VERSION 5.8 ;
BUSBITCHARS "[]" ;
DIVIDERCHAR "/" ;
UNITS
    DATABASE MICRONS 1000 ;
END UNITS

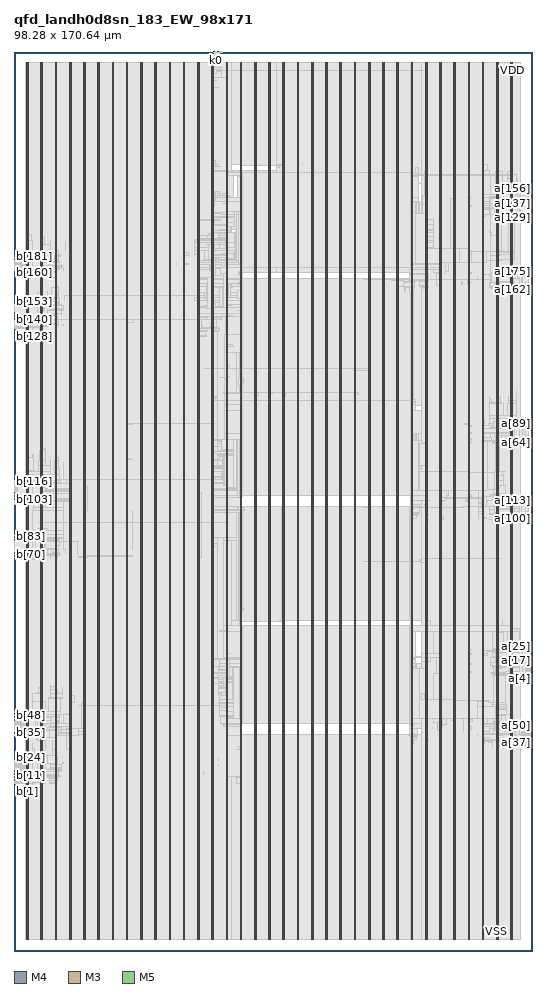
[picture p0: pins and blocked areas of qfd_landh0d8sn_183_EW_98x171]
MACRO qfd_landh0d8sn_183_EW_98x171
  FOREIGN qfd_landh0d8sn_183_EW_98x171 0 0 ;
  CLASS BLOCK ;
  SIZE 98.28 BY 170.64 ;
  PIN a[0]
    DIRECTION INPUT ;
    USE SIGNAL ;
    PORT
      LAYER M4 ;
        RECT  98.196 52.56 98.28 52.584 ;
    END
  END a[0]
  PIN a[100]
    DIRECTION INPUT ;
    USE SIGNAL ;
    PORT
      LAYER M4 ;
        RECT  98.196 81.936 98.28 81.96 ;
    END
  END a[100]
  PIN a[101]
    DIRECTION INPUT ;
    USE SIGNAL ;
    PORT
      LAYER M4 ;
        RECT  98.196 82.08 98.28 82.104 ;
    END
  END a[101]
  PIN a[102]
    DIRECTION INPUT ;
    USE SIGNAL ;
    PORT
      LAYER M4 ;
        RECT  98.196 82.224 98.28 82.248 ;
    END
  END a[102]
  PIN a[103]
    DIRECTION INPUT ;
    USE SIGNAL ;
    PORT
      LAYER M4 ;
        RECT  98.196 82.368 98.28 82.392 ;
    END
  END a[103]
  PIN a[104]
    DIRECTION INPUT ;
    USE SIGNAL ;
    PORT
      LAYER M4 ;
        RECT  98.196 82.512 98.28 82.536 ;
    END
  END a[104]
  PIN a[105]
    DIRECTION INPUT ;
    USE SIGNAL ;
    PORT
      LAYER M4 ;
        RECT  98.196 82.656 98.28 82.68 ;
    END
  END a[105]
  PIN a[106]
    DIRECTION INPUT ;
    USE SIGNAL ;
    PORT
      LAYER M4 ;
        RECT  98.196 82.8 98.28 82.824 ;
    END
  END a[106]
  PIN a[107]
    DIRECTION INPUT ;
    USE SIGNAL ;
    PORT
      LAYER M4 ;
        RECT  98.196 82.944 98.28 82.968 ;
    END
  END a[107]
  PIN a[108]
    DIRECTION INPUT ;
    USE SIGNAL ;
    PORT
      LAYER M4 ;
        RECT  98.196 83.088 98.28 83.112 ;
    END
  END a[108]
  PIN a[109]
    DIRECTION INPUT ;
    USE SIGNAL ;
    PORT
      LAYER M4 ;
        RECT  98.196 83.232 98.28 83.256 ;
    END
  END a[109]
  PIN a[10]
    DIRECTION INPUT ;
    USE SIGNAL ;
    PORT
      LAYER M4 ;
        RECT  98.196 54 98.28 54.024 ;
    END
  END a[10]
  PIN a[110]
    DIRECTION INPUT ;
    USE SIGNAL ;
    PORT
      LAYER M4 ;
        RECT  98.196 83.376 98.28 83.4 ;
    END
  END a[110]
  PIN a[111]
    DIRECTION INPUT ;
    USE SIGNAL ;
    PORT
      LAYER M4 ;
        RECT  98.196 83.52 98.28 83.544 ;
    END
  END a[111]
  PIN a[112]
    DIRECTION INPUT ;
    USE SIGNAL ;
    PORT
      LAYER M4 ;
        RECT  98.196 83.664 98.28 83.688 ;
    END
  END a[112]
  PIN a[113]
    DIRECTION INPUT ;
    USE SIGNAL ;
    PORT
      LAYER M4 ;
        RECT  98.196 83.808 98.28 83.832 ;
    END
  END a[113]
  PIN a[114]
    DIRECTION INPUT ;
    USE SIGNAL ;
    PORT
      LAYER M4 ;
        RECT  98.196 83.952 98.28 83.976 ;
    END
  END a[114]
  PIN a[115]
    DIRECTION INPUT ;
    USE SIGNAL ;
    PORT
      LAYER M4 ;
        RECT  98.196 84.096 98.28 84.12 ;
    END
  END a[115]
  PIN a[116]
    DIRECTION INPUT ;
    USE SIGNAL ;
    PORT
      LAYER M4 ;
        RECT  98.196 84.24 98.28 84.264 ;
    END
  END a[116]
  PIN a[117]
    DIRECTION INPUT ;
    USE SIGNAL ;
    PORT
      LAYER M4 ;
        RECT  98.196 84.384 98.28 84.408 ;
    END
  END a[117]
  PIN a[118]
    DIRECTION INPUT ;
    USE SIGNAL ;
    PORT
      LAYER M4 ;
        RECT  98.196 84.528 98.28 84.552 ;
    END
  END a[118]
  PIN a[119]
    DIRECTION INPUT ;
    USE SIGNAL ;
    PORT
      LAYER M4 ;
        RECT  98.196 84.672 98.28 84.696 ;
    END
  END a[119]
  PIN a[11]
    DIRECTION INPUT ;
    USE SIGNAL ;
    PORT
      LAYER M4 ;
        RECT  98.196 54.144 98.28 54.168 ;
    END
  END a[11]
  PIN a[120]
    DIRECTION INPUT ;
    USE SIGNAL ;
    PORT
      LAYER M4 ;
        RECT  98.196 84.816 98.28 84.84 ;
    END
  END a[120]
  PIN a[121]
    DIRECTION INPUT ;
    USE SIGNAL ;
    PORT
      LAYER M4 ;
        RECT  98.196 84.96 98.28 84.984 ;
    END
  END a[121]
  PIN a[122]
    DIRECTION INPUT ;
    USE SIGNAL ;
    PORT
      LAYER M4 ;
        RECT  98.196 85.104 98.28 85.128 ;
    END
  END a[122]
  PIN a[123]
    DIRECTION INPUT ;
    USE SIGNAL ;
    PORT
      LAYER M4 ;
        RECT  98.196 85.248 98.28 85.272 ;
    END
  END a[123]
  PIN a[124]
    DIRECTION INPUT ;
    USE SIGNAL ;
    PORT
      LAYER M4 ;
        RECT  98.196 85.392 98.28 85.416 ;
    END
  END a[124]
  PIN a[125]
    DIRECTION INPUT ;
    USE SIGNAL ;
    PORT
      LAYER M4 ;
        RECT  98.196 85.536 98.28 85.56 ;
    END
  END a[125]
  PIN a[126]
    DIRECTION INPUT ;
    USE SIGNAL ;
    PORT
      LAYER M4 ;
        RECT  98.196 85.68 98.28 85.704 ;
    END
  END a[126]
  PIN a[127]
    DIRECTION INPUT ;
    USE SIGNAL ;
    PORT
      LAYER M4 ;
        RECT  98.196 85.824 98.28 85.848 ;
    END
  END a[127]
  PIN a[128]
    DIRECTION INPUT ;
    USE SIGNAL ;
    PORT
      LAYER M4 ;
        RECT  98.196 138.96 98.28 138.984 ;
    END
  END a[128]
  PIN a[129]
    DIRECTION INPUT ;
    USE SIGNAL ;
    PORT
      LAYER M4 ;
        RECT  98.196 139.104 98.28 139.128 ;
    END
  END a[129]
  PIN a[12]
    DIRECTION INPUT ;
    USE SIGNAL ;
    PORT
      LAYER M4 ;
        RECT  98.196 54.288 98.28 54.312 ;
    END
  END a[12]
  PIN a[130]
    DIRECTION INPUT ;
    USE SIGNAL ;
    PORT
      LAYER M4 ;
        RECT  98.196 139.248 98.28 139.272 ;
    END
  END a[130]
  PIN a[131]
    DIRECTION INPUT ;
    USE SIGNAL ;
    PORT
      LAYER M4 ;
        RECT  98.196 139.392 98.28 139.416 ;
    END
  END a[131]
  PIN a[132]
    DIRECTION INPUT ;
    USE SIGNAL ;
    PORT
      LAYER M4 ;
        RECT  98.196 139.536 98.28 139.56 ;
    END
  END a[132]
  PIN a[133]
    DIRECTION INPUT ;
    USE SIGNAL ;
    PORT
      LAYER M4 ;
        RECT  98.196 139.68 98.28 139.704 ;
    END
  END a[133]
  PIN a[134]
    DIRECTION INPUT ;
    USE SIGNAL ;
    PORT
      LAYER M4 ;
        RECT  98.196 139.824 98.28 139.848 ;
    END
  END a[134]
  PIN a[135]
    DIRECTION INPUT ;
    USE SIGNAL ;
    PORT
      LAYER M4 ;
        RECT  98.196 139.968 98.28 139.992 ;
    END
  END a[135]
  PIN a[136]
    DIRECTION INPUT ;
    USE SIGNAL ;
    PORT
      LAYER M4 ;
        RECT  98.196 140.112 98.28 140.136 ;
    END
  END a[136]
  PIN a[137]
    DIRECTION INPUT ;
    USE SIGNAL ;
    PORT
      LAYER M4 ;
        RECT  98.196 140.256 98.28 140.28 ;
    END
  END a[137]
  PIN a[138]
    DIRECTION INPUT ;
    USE SIGNAL ;
    PORT
      LAYER M4 ;
        RECT  98.196 140.4 98.28 140.424 ;
    END
  END a[138]
  PIN a[139]
    DIRECTION INPUT ;
    USE SIGNAL ;
    PORT
      LAYER M4 ;
        RECT  98.196 140.544 98.28 140.568 ;
    END
  END a[139]
  PIN a[13]
    DIRECTION INPUT ;
    USE SIGNAL ;
    PORT
      LAYER M4 ;
        RECT  98.196 54.432 98.28 54.456 ;
    END
  END a[13]
  PIN a[140]
    DIRECTION INPUT ;
    USE SIGNAL ;
    PORT
      LAYER M4 ;
        RECT  98.196 140.688 98.28 140.712 ;
    END
  END a[140]
  PIN a[141]
    DIRECTION INPUT ;
    USE SIGNAL ;
    PORT
      LAYER M4 ;
        RECT  98.196 140.832 98.28 140.856 ;
    END
  END a[141]
  PIN a[142]
    DIRECTION INPUT ;
    USE SIGNAL ;
    PORT
      LAYER M4 ;
        RECT  98.196 140.976 98.28 141 ;
    END
  END a[142]
  PIN a[143]
    DIRECTION INPUT ;
    USE SIGNAL ;
    PORT
      LAYER M4 ;
        RECT  98.196 141.12 98.28 141.144 ;
    END
  END a[143]
  PIN a[144]
    DIRECTION INPUT ;
    USE SIGNAL ;
    PORT
      LAYER M4 ;
        RECT  98.196 141.264 98.28 141.288 ;
    END
  END a[144]
  PIN a[145]
    DIRECTION INPUT ;
    USE SIGNAL ;
    PORT
      LAYER M4 ;
        RECT  98.196 141.408 98.28 141.432 ;
    END
  END a[145]
  PIN a[146]
    DIRECTION INPUT ;
    USE SIGNAL ;
    PORT
      LAYER M4 ;
        RECT  98.196 141.552 98.28 141.576 ;
    END
  END a[146]
  PIN a[147]
    DIRECTION INPUT ;
    USE SIGNAL ;
    PORT
      LAYER M4 ;
        RECT  98.196 141.696 98.28 141.72 ;
    END
  END a[147]
  PIN a[148]
    DIRECTION INPUT ;
    USE SIGNAL ;
    PORT
      LAYER M4 ;
        RECT  98.196 141.84 98.28 141.864 ;
    END
  END a[148]
  PIN a[149]
    DIRECTION INPUT ;
    USE SIGNAL ;
    PORT
      LAYER M4 ;
        RECT  98.196 141.984 98.28 142.008 ;
    END
  END a[149]
  PIN a[14]
    DIRECTION INPUT ;
    USE SIGNAL ;
    PORT
      LAYER M4 ;
        RECT  98.196 54.576 98.28 54.6 ;
    END
  END a[14]
  PIN a[150]
    DIRECTION INPUT ;
    USE SIGNAL ;
    PORT
      LAYER M4 ;
        RECT  98.196 142.128 98.28 142.152 ;
    END
  END a[150]
  PIN a[151]
    DIRECTION INPUT ;
    USE SIGNAL ;
    PORT
      LAYER M4 ;
        RECT  98.196 142.272 98.28 142.296 ;
    END
  END a[151]
  PIN a[152]
    DIRECTION INPUT ;
    USE SIGNAL ;
    PORT
      LAYER M4 ;
        RECT  98.196 142.416 98.28 142.44 ;
    END
  END a[152]
  PIN a[153]
    DIRECTION INPUT ;
    USE SIGNAL ;
    PORT
      LAYER M4 ;
        RECT  98.196 142.56 98.28 142.584 ;
    END
  END a[153]
  PIN a[154]
    DIRECTION INPUT ;
    USE SIGNAL ;
    PORT
      LAYER M4 ;
        RECT  98.196 142.704 98.28 142.728 ;
    END
  END a[154]
  PIN a[155]
    DIRECTION INPUT ;
    USE SIGNAL ;
    PORT
      LAYER M4 ;
        RECT  98.196 142.848 98.28 142.872 ;
    END
  END a[155]
  PIN a[156]
    DIRECTION INPUT ;
    USE SIGNAL ;
    PORT
      LAYER M4 ;
        RECT  98.196 142.992 98.28 143.016 ;
    END
  END a[156]
  PIN a[157]
    DIRECTION INPUT ;
    USE SIGNAL ;
    PORT
      LAYER M4 ;
        RECT  98.196 143.136 98.28 143.16 ;
    END
  END a[157]
  PIN a[158]
    DIRECTION INPUT ;
    USE SIGNAL ;
    PORT
      LAYER M4 ;
        RECT  98.196 143.28 98.28 143.304 ;
    END
  END a[158]
  PIN a[159]
    DIRECTION INPUT ;
    USE SIGNAL ;
    PORT
      LAYER M4 ;
        RECT  98.196 143.424 98.28 143.448 ;
    END
  END a[159]
  PIN a[15]
    DIRECTION INPUT ;
    USE SIGNAL ;
    PORT
      LAYER M4 ;
        RECT  98.196 54.72 98.28 54.744 ;
    END
  END a[15]
  PIN a[160]
    DIRECTION INPUT ;
    USE SIGNAL ;
    PORT
      LAYER M4 ;
        RECT  98.196 125.136 98.28 125.16 ;
    END
  END a[160]
  PIN a[161]
    DIRECTION INPUT ;
    USE SIGNAL ;
    PORT
      LAYER M4 ;
        RECT  98.196 125.28 98.28 125.304 ;
    END
  END a[161]
  PIN a[162]
    DIRECTION INPUT ;
    USE SIGNAL ;
    PORT
      LAYER M4 ;
        RECT  98.196 125.424 98.28 125.448 ;
    END
  END a[162]
  PIN a[163]
    DIRECTION INPUT ;
    USE SIGNAL ;
    PORT
      LAYER M4 ;
        RECT  98.196 125.568 98.28 125.592 ;
    END
  END a[163]
  PIN a[164]
    DIRECTION INPUT ;
    USE SIGNAL ;
    PORT
      LAYER M4 ;
        RECT  98.196 125.712 98.28 125.736 ;
    END
  END a[164]
  PIN a[165]
    DIRECTION INPUT ;
    USE SIGNAL ;
    PORT
      LAYER M4 ;
        RECT  98.196 125.856 98.28 125.88 ;
    END
  END a[165]
  PIN a[166]
    DIRECTION INPUT ;
    USE SIGNAL ;
    PORT
      LAYER M4 ;
        RECT  98.196 126 98.28 126.024 ;
    END
  END a[166]
  PIN a[167]
    DIRECTION INPUT ;
    USE SIGNAL ;
    PORT
      LAYER M4 ;
        RECT  98.196 126.144 98.28 126.168 ;
    END
  END a[167]
  PIN a[168]
    DIRECTION INPUT ;
    USE SIGNAL ;
    PORT
      LAYER M4 ;
        RECT  98.196 126.288 98.28 126.312 ;
    END
  END a[168]
  PIN a[169]
    DIRECTION INPUT ;
    USE SIGNAL ;
    PORT
      LAYER M4 ;
        RECT  98.196 126.432 98.28 126.456 ;
    END
  END a[169]
  PIN a[16]
    DIRECTION INPUT ;
    USE SIGNAL ;
    PORT
      LAYER M4 ;
        RECT  98.196 54.864 98.28 54.888 ;
    END
  END a[16]
  PIN a[170]
    DIRECTION INPUT ;
    USE SIGNAL ;
    PORT
      LAYER M4 ;
        RECT  98.196 126.576 98.28 126.6 ;
    END
  END a[170]
  PIN a[171]
    DIRECTION INPUT ;
    USE SIGNAL ;
    PORT
      LAYER M4 ;
        RECT  98.196 126.72 98.28 126.744 ;
    END
  END a[171]
  PIN a[172]
    DIRECTION INPUT ;
    USE SIGNAL ;
    PORT
      LAYER M4 ;
        RECT  98.196 126.864 98.28 126.888 ;
    END
  END a[172]
  PIN a[173]
    DIRECTION INPUT ;
    USE SIGNAL ;
    PORT
      LAYER M4 ;
        RECT  98.196 127.008 98.28 127.032 ;
    END
  END a[173]
  PIN a[174]
    DIRECTION INPUT ;
    USE SIGNAL ;
    PORT
      LAYER M4 ;
        RECT  98.196 127.152 98.28 127.176 ;
    END
  END a[174]
  PIN a[175]
    DIRECTION INPUT ;
    USE SIGNAL ;
    PORT
      LAYER M4 ;
        RECT  98.196 127.296 98.28 127.32 ;
    END
  END a[175]
  PIN a[176]
    DIRECTION INPUT ;
    USE SIGNAL ;
    PORT
      LAYER M4 ;
        RECT  98.196 127.44 98.28 127.464 ;
    END
  END a[176]
  PIN a[177]
    DIRECTION INPUT ;
    USE SIGNAL ;
    PORT
      LAYER M4 ;
        RECT  98.196 127.584 98.28 127.608 ;
    END
  END a[177]
  PIN a[178]
    DIRECTION INPUT ;
    USE SIGNAL ;
    PORT
      LAYER M4 ;
        RECT  98.196 127.728 98.28 127.752 ;
    END
  END a[178]
  PIN a[179]
    DIRECTION INPUT ;
    USE SIGNAL ;
    PORT
      LAYER M4 ;
        RECT  98.196 127.872 98.28 127.896 ;
    END
  END a[179]
  PIN a[17]
    DIRECTION INPUT ;
    USE SIGNAL ;
    PORT
      LAYER M4 ;
        RECT  98.196 55.008 98.28 55.032 ;
    END
  END a[17]
  PIN a[180]
    DIRECTION INPUT ;
    USE SIGNAL ;
    PORT
      LAYER M4 ;
        RECT  98.196 128.016 98.28 128.04 ;
    END
  END a[180]
  PIN a[181]
    DIRECTION INPUT ;
    USE SIGNAL ;
    PORT
      LAYER M4 ;
        RECT  98.196 128.16 98.28 128.184 ;
    END
  END a[181]
  PIN a[182]
    DIRECTION INPUT ;
    USE SIGNAL ;
    PORT
      LAYER M4 ;
        RECT  98.196 128.304 98.28 128.328 ;
    END
  END a[182]
  PIN a[18]
    DIRECTION INPUT ;
    USE SIGNAL ;
    PORT
      LAYER M4 ;
        RECT  98.196 55.152 98.28 55.176 ;
    END
  END a[18]
  PIN a[19]
    DIRECTION INPUT ;
    USE SIGNAL ;
    PORT
      LAYER M4 ;
        RECT  98.196 55.296 98.28 55.32 ;
    END
  END a[19]
  PIN a[1]
    DIRECTION INPUT ;
    USE SIGNAL ;
    PORT
      LAYER M4 ;
        RECT  98.196 52.704 98.28 52.728 ;
    END
  END a[1]
  PIN a[20]
    DIRECTION INPUT ;
    USE SIGNAL ;
    PORT
      LAYER M4 ;
        RECT  98.196 55.44 98.28 55.464 ;
    END
  END a[20]
  PIN a[21]
    DIRECTION INPUT ;
    USE SIGNAL ;
    PORT
      LAYER M4 ;
        RECT  98.196 55.584 98.28 55.608 ;
    END
  END a[21]
  PIN a[22]
    DIRECTION INPUT ;
    USE SIGNAL ;
    PORT
      LAYER M4 ;
        RECT  98.196 55.728 98.28 55.752 ;
    END
  END a[22]
  PIN a[23]
    DIRECTION INPUT ;
    USE SIGNAL ;
    PORT
      LAYER M4 ;
        RECT  98.196 55.872 98.28 55.896 ;
    END
  END a[23]
  PIN a[24]
    DIRECTION INPUT ;
    USE SIGNAL ;
    PORT
      LAYER M4 ;
        RECT  98.196 56.016 98.28 56.04 ;
    END
  END a[24]
  PIN a[25]
    DIRECTION INPUT ;
    USE SIGNAL ;
    PORT
      LAYER M4 ;
        RECT  98.196 56.16 98.28 56.184 ;
    END
  END a[25]
  PIN a[26]
    DIRECTION INPUT ;
    USE SIGNAL ;
    PORT
      LAYER M4 ;
        RECT  98.196 56.304 98.28 56.328 ;
    END
  END a[26]
  PIN a[27]
    DIRECTION INPUT ;
    USE SIGNAL ;
    PORT
      LAYER M4 ;
        RECT  98.196 56.448 98.28 56.472 ;
    END
  END a[27]
  PIN a[28]
    DIRECTION INPUT ;
    USE SIGNAL ;
    PORT
      LAYER M4 ;
        RECT  98.196 56.592 98.28 56.616 ;
    END
  END a[28]
  PIN a[29]
    DIRECTION INPUT ;
    USE SIGNAL ;
    PORT
      LAYER M4 ;
        RECT  98.196 56.736 98.28 56.76 ;
    END
  END a[29]
  PIN a[2]
    DIRECTION INPUT ;
    USE SIGNAL ;
    PORT
      LAYER M4 ;
        RECT  98.196 52.848 98.28 52.872 ;
    END
  END a[2]
  PIN a[30]
    DIRECTION INPUT ;
    USE SIGNAL ;
    PORT
      LAYER M4 ;
        RECT  98.196 56.88 98.28 56.904 ;
    END
  END a[30]
  PIN a[31]
    DIRECTION INPUT ;
    USE SIGNAL ;
    PORT
      LAYER M4 ;
        RECT  98.196 57.024 98.28 57.048 ;
    END
  END a[31]
  PIN a[32]
    DIRECTION INPUT ;
    USE SIGNAL ;
    PORT
      LAYER M4 ;
        RECT  98.196 38.736 98.28 38.76 ;
    END
  END a[32]
  PIN a[33]
    DIRECTION INPUT ;
    USE SIGNAL ;
    PORT
      LAYER M4 ;
        RECT  98.196 38.88 98.28 38.904 ;
    END
  END a[33]
  PIN a[34]
    DIRECTION INPUT ;
    USE SIGNAL ;
    PORT
      LAYER M4 ;
        RECT  98.196 39.024 98.28 39.048 ;
    END
  END a[34]
  PIN a[35]
    DIRECTION INPUT ;
    USE SIGNAL ;
    PORT
      LAYER M4 ;
        RECT  98.196 39.168 98.28 39.192 ;
    END
  END a[35]
  PIN a[36]
    DIRECTION INPUT ;
    USE SIGNAL ;
    PORT
      LAYER M4 ;
        RECT  98.196 39.312 98.28 39.336 ;
    END
  END a[36]
  PIN a[37]
    DIRECTION INPUT ;
    USE SIGNAL ;
    PORT
      LAYER M4 ;
        RECT  98.196 39.456 98.28 39.48 ;
    END
  END a[37]
  PIN a[38]
    DIRECTION INPUT ;
    USE SIGNAL ;
    PORT
      LAYER M4 ;
        RECT  98.196 39.6 98.28 39.624 ;
    END
  END a[38]
  PIN a[39]
    DIRECTION INPUT ;
    USE SIGNAL ;
    PORT
      LAYER M4 ;
        RECT  98.196 39.744 98.28 39.768 ;
    END
  END a[39]
  PIN a[3]
    DIRECTION INPUT ;
    USE SIGNAL ;
    PORT
      LAYER M4 ;
        RECT  98.196 52.992 98.28 53.016 ;
    END
  END a[3]
  PIN a[40]
    DIRECTION INPUT ;
    USE SIGNAL ;
    PORT
      LAYER M4 ;
        RECT  98.196 39.888 98.28 39.912 ;
    END
  END a[40]
  PIN a[41]
    DIRECTION INPUT ;
    USE SIGNAL ;
    PORT
      LAYER M4 ;
        RECT  98.196 40.032 98.28 40.056 ;
    END
  END a[41]
  PIN a[42]
    DIRECTION INPUT ;
    USE SIGNAL ;
    PORT
      LAYER M4 ;
        RECT  98.196 40.176 98.28 40.2 ;
    END
  END a[42]
  PIN a[43]
    DIRECTION INPUT ;
    USE SIGNAL ;
    PORT
      LAYER M4 ;
        RECT  98.196 40.32 98.28 40.344 ;
    END
  END a[43]
  PIN a[44]
    DIRECTION INPUT ;
    USE SIGNAL ;
    PORT
      LAYER M4 ;
        RECT  98.196 40.464 98.28 40.488 ;
    END
  END a[44]
  PIN a[45]
    DIRECTION INPUT ;
    USE SIGNAL ;
    PORT
      LAYER M4 ;
        RECT  98.196 40.608 98.28 40.632 ;
    END
  END a[45]
  PIN a[46]
    DIRECTION INPUT ;
    USE SIGNAL ;
    PORT
      LAYER M4 ;
        RECT  98.196 40.752 98.28 40.776 ;
    END
  END a[46]
  PIN a[47]
    DIRECTION INPUT ;
    USE SIGNAL ;
    PORT
      LAYER M4 ;
        RECT  98.196 40.896 98.28 40.92 ;
    END
  END a[47]
  PIN a[48]
    DIRECTION INPUT ;
    USE SIGNAL ;
    PORT
      LAYER M4 ;
        RECT  98.196 41.04 98.28 41.064 ;
    END
  END a[48]
  PIN a[49]
    DIRECTION INPUT ;
    USE SIGNAL ;
    PORT
      LAYER M4 ;
        RECT  98.196 41.184 98.28 41.208 ;
    END
  END a[49]
  PIN a[4]
    DIRECTION INPUT ;
    USE SIGNAL ;
    PORT
      LAYER M4 ;
        RECT  98.196 53.136 98.28 53.16 ;
    END
  END a[4]
  PIN a[50]
    DIRECTION INPUT ;
    USE SIGNAL ;
    PORT
      LAYER M4 ;
        RECT  98.196 41.328 98.28 41.352 ;
    END
  END a[50]
  PIN a[51]
    DIRECTION INPUT ;
    USE SIGNAL ;
    PORT
      LAYER M4 ;
        RECT  98.196 41.472 98.28 41.496 ;
    END
  END a[51]
  PIN a[52]
    DIRECTION INPUT ;
    USE SIGNAL ;
    PORT
      LAYER M4 ;
        RECT  98.196 41.616 98.28 41.64 ;
    END
  END a[52]
  PIN a[53]
    DIRECTION INPUT ;
    USE SIGNAL ;
    PORT
      LAYER M4 ;
        RECT  98.196 41.76 98.28 41.784 ;
    END
  END a[53]
  PIN a[54]
    DIRECTION INPUT ;
    USE SIGNAL ;
    PORT
      LAYER M4 ;
        RECT  98.196 41.904 98.28 41.928 ;
    END
  END a[54]
  PIN a[55]
    DIRECTION INPUT ;
    USE SIGNAL ;
    PORT
      LAYER M4 ;
        RECT  98.196 42.048 98.28 42.072 ;
    END
  END a[55]
  PIN a[56]
    DIRECTION INPUT ;
    USE SIGNAL ;
    PORT
      LAYER M4 ;
        RECT  98.196 42.192 98.28 42.216 ;
    END
  END a[56]
  PIN a[57]
    DIRECTION INPUT ;
    USE SIGNAL ;
    PORT
      LAYER M4 ;
        RECT  98.196 42.336 98.28 42.36 ;
    END
  END a[57]
  PIN a[58]
    DIRECTION INPUT ;
    USE SIGNAL ;
    PORT
      LAYER M4 ;
        RECT  98.196 42.48 98.28 42.504 ;
    END
  END a[58]
  PIN a[59]
    DIRECTION INPUT ;
    USE SIGNAL ;
    PORT
      LAYER M4 ;
        RECT  98.196 42.624 98.28 42.648 ;
    END
  END a[59]
  PIN a[5]
    DIRECTION INPUT ;
    USE SIGNAL ;
    PORT
      LAYER M4 ;
        RECT  98.196 53.28 98.28 53.304 ;
    END
  END a[5]
  PIN a[60]
    DIRECTION INPUT ;
    USE SIGNAL ;
    PORT
      LAYER M4 ;
        RECT  98.196 42.768 98.28 42.792 ;
    END
  END a[60]
  PIN a[61]
    DIRECTION INPUT ;
    USE SIGNAL ;
    PORT
      LAYER M4 ;
        RECT  98.196 42.912 98.28 42.936 ;
    END
  END a[61]
  PIN a[62]
    DIRECTION INPUT ;
    USE SIGNAL ;
    PORT
      LAYER M4 ;
        RECT  98.196 43.056 98.28 43.08 ;
    END
  END a[62]
  PIN a[63]
    DIRECTION INPUT ;
    USE SIGNAL ;
    PORT
      LAYER M4 ;
        RECT  98.196 43.2 98.28 43.224 ;
    END
  END a[63]
  PIN a[64]
    DIRECTION INPUT ;
    USE SIGNAL ;
    PORT
      LAYER M4 ;
        RECT  98.196 96.336 98.28 96.36 ;
    END
  END a[64]
  PIN a[65]
    DIRECTION INPUT ;
    USE SIGNAL ;
    PORT
      LAYER M4 ;
        RECT  98.196 96.48 98.28 96.504 ;
    END
  END a[65]
  PIN a[66]
    DIRECTION INPUT ;
    USE SIGNAL ;
    PORT
      LAYER M4 ;
        RECT  98.196 96.624 98.28 96.648 ;
    END
  END a[66]
  PIN a[67]
    DIRECTION INPUT ;
    USE SIGNAL ;
    PORT
      LAYER M4 ;
        RECT  98.196 96.768 98.28 96.792 ;
    END
  END a[67]
  PIN a[68]
    DIRECTION INPUT ;
    USE SIGNAL ;
    PORT
      LAYER M4 ;
        RECT  98.196 96.912 98.28 96.936 ;
    END
  END a[68]
  PIN a[69]
    DIRECTION INPUT ;
    USE SIGNAL ;
    PORT
      LAYER M4 ;
        RECT  98.196 97.056 98.28 97.08 ;
    END
  END a[69]
  PIN a[6]
    DIRECTION INPUT ;
    USE SIGNAL ;
    PORT
      LAYER M4 ;
        RECT  98.196 53.424 98.28 53.448 ;
    END
  END a[6]
  PIN a[70]
    DIRECTION INPUT ;
    USE SIGNAL ;
    PORT
      LAYER M4 ;
        RECT  98.196 97.2 98.28 97.224 ;
    END
  END a[70]
  PIN a[71]
    DIRECTION INPUT ;
    USE SIGNAL ;
    PORT
      LAYER M4 ;
        RECT  98.196 97.344 98.28 97.368 ;
    END
  END a[71]
  PIN a[72]
    DIRECTION INPUT ;
    USE SIGNAL ;
    PORT
      LAYER M4 ;
        RECT  98.196 97.488 98.28 97.512 ;
    END
  END a[72]
  PIN a[73]
    DIRECTION INPUT ;
    USE SIGNAL ;
    PORT
      LAYER M4 ;
        RECT  98.196 97.632 98.28 97.656 ;
    END
  END a[73]
  PIN a[74]
    DIRECTION INPUT ;
    USE SIGNAL ;
    PORT
      LAYER M4 ;
        RECT  98.196 97.776 98.28 97.8 ;
    END
  END a[74]
  PIN a[75]
    DIRECTION INPUT ;
    USE SIGNAL ;
    PORT
      LAYER M4 ;
        RECT  98.196 97.92 98.28 97.944 ;
    END
  END a[75]
  PIN a[76]
    DIRECTION INPUT ;
    USE SIGNAL ;
    PORT
      LAYER M4 ;
        RECT  98.196 98.064 98.28 98.088 ;
    END
  END a[76]
  PIN a[77]
    DIRECTION INPUT ;
    USE SIGNAL ;
    PORT
      LAYER M4 ;
        RECT  98.196 98.208 98.28 98.232 ;
    END
  END a[77]
  PIN a[78]
    DIRECTION INPUT ;
    USE SIGNAL ;
    PORT
      LAYER M4 ;
        RECT  98.196 98.352 98.28 98.376 ;
    END
  END a[78]
  PIN a[79]
    DIRECTION INPUT ;
    USE SIGNAL ;
    PORT
      LAYER M4 ;
        RECT  98.196 98.496 98.28 98.52 ;
    END
  END a[79]
  PIN a[7]
    DIRECTION INPUT ;
    USE SIGNAL ;
    PORT
      LAYER M4 ;
        RECT  98.196 53.568 98.28 53.592 ;
    END
  END a[7]
  PIN a[80]
    DIRECTION INPUT ;
    USE SIGNAL ;
    PORT
      LAYER M4 ;
        RECT  98.196 98.64 98.28 98.664 ;
    END
  END a[80]
  PIN a[81]
    DIRECTION INPUT ;
    USE SIGNAL ;
    PORT
      LAYER M4 ;
        RECT  98.196 98.784 98.28 98.808 ;
    END
  END a[81]
  PIN a[82]
    DIRECTION INPUT ;
    USE SIGNAL ;
    PORT
      LAYER M4 ;
        RECT  98.196 98.928 98.28 98.952 ;
    END
  END a[82]
  PIN a[83]
    DIRECTION INPUT ;
    USE SIGNAL ;
    PORT
      LAYER M4 ;
        RECT  98.196 99.072 98.28 99.096 ;
    END
  END a[83]
  PIN a[84]
    DIRECTION INPUT ;
    USE SIGNAL ;
    PORT
      LAYER M4 ;
        RECT  98.196 99.216 98.28 99.24 ;
    END
  END a[84]
  PIN a[85]
    DIRECTION INPUT ;
    USE SIGNAL ;
    PORT
      LAYER M4 ;
        RECT  98.196 99.36 98.28 99.384 ;
    END
  END a[85]
  PIN a[86]
    DIRECTION INPUT ;
    USE SIGNAL ;
    PORT
      LAYER M4 ;
        RECT  98.196 99.504 98.28 99.528 ;
    END
  END a[86]
  PIN a[87]
    DIRECTION INPUT ;
    USE SIGNAL ;
    PORT
      LAYER M4 ;
        RECT  98.196 99.648 98.28 99.672 ;
    END
  END a[87]
  PIN a[88]
    DIRECTION INPUT ;
    USE SIGNAL ;
    PORT
      LAYER M4 ;
        RECT  98.196 99.792 98.28 99.816 ;
    END
  END a[88]
  PIN a[89]
    DIRECTION INPUT ;
    USE SIGNAL ;
    PORT
      LAYER M4 ;
        RECT  98.196 99.936 98.28 99.96 ;
    END
  END a[89]
  PIN a[8]
    DIRECTION INPUT ;
    USE SIGNAL ;
    PORT
      LAYER M4 ;
        RECT  98.196 53.712 98.28 53.736 ;
    END
  END a[8]
  PIN a[90]
    DIRECTION INPUT ;
    USE SIGNAL ;
    PORT
      LAYER M4 ;
        RECT  98.196 100.08 98.28 100.104 ;
    END
  END a[90]
  PIN a[91]
    DIRECTION INPUT ;
    USE SIGNAL ;
    PORT
      LAYER M4 ;
        RECT  98.196 100.224 98.28 100.248 ;
    END
  END a[91]
  PIN a[92]
    DIRECTION INPUT ;
    USE SIGNAL ;
    PORT
      LAYER M4 ;
        RECT  98.196 100.368 98.28 100.392 ;
    END
  END a[92]
  PIN a[93]
    DIRECTION INPUT ;
    USE SIGNAL ;
    PORT
      LAYER M4 ;
        RECT  98.196 100.512 98.28 100.536 ;
    END
  END a[93]
  PIN a[94]
    DIRECTION INPUT ;
    USE SIGNAL ;
    PORT
      LAYER M4 ;
        RECT  98.196 100.656 98.28 100.68 ;
    END
  END a[94]
  PIN a[95]
    DIRECTION INPUT ;
    USE SIGNAL ;
    PORT
      LAYER M4 ;
        RECT  98.196 100.8 98.28 100.824 ;
    END
  END a[95]
  PIN a[96]
    DIRECTION INPUT ;
    USE SIGNAL ;
    PORT
      LAYER M4 ;
        RECT  98.196 81.36 98.28 81.384 ;
    END
  END a[96]
  PIN a[97]
    DIRECTION INPUT ;
    USE SIGNAL ;
    PORT
      LAYER M4 ;
        RECT  98.196 81.504 98.28 81.528 ;
    END
  END a[97]
  PIN a[98]
    DIRECTION INPUT ;
    USE SIGNAL ;
    PORT
      LAYER M4 ;
        RECT  98.196 81.648 98.28 81.672 ;
    END
  END a[98]
  PIN a[99]
    DIRECTION INPUT ;
    USE SIGNAL ;
    PORT
      LAYER M4 ;
        RECT  98.196 81.792 98.28 81.816 ;
    END
  END a[99]
  PIN a[9]
    DIRECTION INPUT ;
    USE SIGNAL ;
    PORT
      LAYER M4 ;
        RECT  98.196 53.856 98.28 53.88 ;
    END
  END a[9]
  PIN b[0]
    DIRECTION OUTPUT ;
    USE SIGNAL ;
    PORT
      LAYER M4 ;
        RECT  0 31.68 0.084 31.704 ;
    END
  END b[0]
  PIN b[100]
    DIRECTION OUTPUT ;
    USE SIGNAL ;
    PORT
      LAYER M4 ;
        RECT  0 85.248 0.084 85.272 ;
    END
  END b[100]
  PIN b[101]
    DIRECTION OUTPUT ;
    USE SIGNAL ;
    PORT
      LAYER M4 ;
        RECT  0 85.392 0.084 85.416 ;
    END
  END b[101]
  PIN b[102]
    DIRECTION OUTPUT ;
    USE SIGNAL ;
    PORT
      LAYER M4 ;
        RECT  0 85.536 0.084 85.56 ;
    END
  END b[102]
  PIN b[103]
    DIRECTION OUTPUT ;
    USE SIGNAL ;
    PORT
      LAYER M4 ;
        RECT  0 85.68 0.084 85.704 ;
    END
  END b[103]
  PIN b[104]
    DIRECTION OUTPUT ;
    USE SIGNAL ;
    PORT
      LAYER M4 ;
        RECT  0 85.824 0.084 85.848 ;
    END
  END b[104]
  PIN b[105]
    DIRECTION OUTPUT ;
    USE SIGNAL ;
    PORT
      LAYER M4 ;
        RECT  0 85.968 0.084 85.992 ;
    END
  END b[105]
  PIN b[106]
    DIRECTION OUTPUT ;
    USE SIGNAL ;
    PORT
      LAYER M4 ;
        RECT  0 86.112 0.084 86.136 ;
    END
  END b[106]
  PIN b[107]
    DIRECTION OUTPUT ;
    USE SIGNAL ;
    PORT
      LAYER M4 ;
        RECT  0 86.256 0.084 86.28 ;
    END
  END b[107]
  PIN b[108]
    DIRECTION OUTPUT ;
    USE SIGNAL ;
    PORT
      LAYER M4 ;
        RECT  0 86.4 0.084 86.424 ;
    END
  END b[108]
  PIN b[109]
    DIRECTION OUTPUT ;
    USE SIGNAL ;
    PORT
      LAYER M4 ;
        RECT  0 86.544 0.084 86.568 ;
    END
  END b[109]
  PIN b[10]
    DIRECTION OUTPUT ;
    USE SIGNAL ;
    PORT
      LAYER M4 ;
        RECT  0 33.12 0.084 33.144 ;
    END
  END b[10]
  PIN b[110]
    DIRECTION OUTPUT ;
    USE SIGNAL ;
    PORT
      LAYER M4 ;
        RECT  0 86.688 0.084 86.712 ;
    END
  END b[110]
  PIN b[111]
    DIRECTION OUTPUT ;
    USE SIGNAL ;
    PORT
      LAYER M4 ;
        RECT  0 86.832 0.084 86.856 ;
    END
  END b[111]
  PIN b[112]
    DIRECTION OUTPUT ;
    USE SIGNAL ;
    PORT
      LAYER M4 ;
        RECT  0 86.976 0.084 87 ;
    END
  END b[112]
  PIN b[113]
    DIRECTION OUTPUT ;
    USE SIGNAL ;
    PORT
      LAYER M4 ;
        RECT  0 87.12 0.084 87.144 ;
    END
  END b[113]
  PIN b[114]
    DIRECTION OUTPUT ;
    USE SIGNAL ;
    PORT
      LAYER M4 ;
        RECT  0 87.264 0.084 87.288 ;
    END
  END b[114]
  PIN b[115]
    DIRECTION OUTPUT ;
    USE SIGNAL ;
    PORT
      LAYER M4 ;
        RECT  0 87.408 0.084 87.432 ;
    END
  END b[115]
  PIN b[116]
    DIRECTION OUTPUT ;
    USE SIGNAL ;
    PORT
      LAYER M4 ;
        RECT  0 87.552 0.084 87.576 ;
    END
  END b[116]
  PIN b[117]
    DIRECTION OUTPUT ;
    USE SIGNAL ;
    PORT
      LAYER M4 ;
        RECT  0 87.696 0.084 87.72 ;
    END
  END b[117]
  PIN b[118]
    DIRECTION OUTPUT ;
    USE SIGNAL ;
    PORT
      LAYER M4 ;
        RECT  0 87.84 0.084 87.864 ;
    END
  END b[118]
  PIN b[119]
    DIRECTION OUTPUT ;
    USE SIGNAL ;
    PORT
      LAYER M4 ;
        RECT  0 87.984 0.084 88.008 ;
    END
  END b[119]
  PIN b[11]
    DIRECTION OUTPUT ;
    USE SIGNAL ;
    PORT
      LAYER M4 ;
        RECT  0 33.264 0.084 33.288 ;
    END
  END b[11]
  PIN b[120]
    DIRECTION OUTPUT ;
    USE SIGNAL ;
    PORT
      LAYER M4 ;
        RECT  0 88.128 0.084 88.152 ;
    END
  END b[120]
  PIN b[121]
    DIRECTION OUTPUT ;
    USE SIGNAL ;
    PORT
      LAYER M4 ;
        RECT  0 88.272 0.084 88.296 ;
    END
  END b[121]
  PIN b[122]
    DIRECTION OUTPUT ;
    USE SIGNAL ;
    PORT
      LAYER M4 ;
        RECT  0 88.416 0.084 88.44 ;
    END
  END b[122]
  PIN b[123]
    DIRECTION OUTPUT ;
    USE SIGNAL ;
    PORT
      LAYER M4 ;
        RECT  0 88.56 0.084 88.584 ;
    END
  END b[123]
  PIN b[124]
    DIRECTION OUTPUT ;
    USE SIGNAL ;
    PORT
      LAYER M4 ;
        RECT  0 88.704 0.084 88.728 ;
    END
  END b[124]
  PIN b[125]
    DIRECTION OUTPUT ;
    USE SIGNAL ;
    PORT
      LAYER M4 ;
        RECT  0 88.848 0.084 88.872 ;
    END
  END b[125]
  PIN b[126]
    DIRECTION OUTPUT ;
    USE SIGNAL ;
    PORT
      LAYER M4 ;
        RECT  0 88.992 0.084 89.016 ;
    END
  END b[126]
  PIN b[127]
    DIRECTION OUTPUT ;
    USE SIGNAL ;
    PORT
      LAYER M4 ;
        RECT  0 89.136 0.084 89.16 ;
    END
  END b[127]
  PIN b[128]
    DIRECTION OUTPUT ;
    USE SIGNAL ;
    PORT
      LAYER M4 ;
        RECT  0 118.08 0.084 118.104 ;
    END
  END b[128]
  PIN b[129]
    DIRECTION OUTPUT ;
    USE SIGNAL ;
    PORT
      LAYER M4 ;
        RECT  0 118.224 0.084 118.248 ;
    END
  END b[129]
  PIN b[12]
    DIRECTION OUTPUT ;
    USE SIGNAL ;
    PORT
      LAYER M4 ;
        RECT  0 33.408 0.084 33.432 ;
    END
  END b[12]
  PIN b[130]
    DIRECTION OUTPUT ;
    USE SIGNAL ;
    PORT
      LAYER M4 ;
        RECT  0 118.368 0.084 118.392 ;
    END
  END b[130]
  PIN b[131]
    DIRECTION OUTPUT ;
    USE SIGNAL ;
    PORT
      LAYER M4 ;
        RECT  0 118.512 0.084 118.536 ;
    END
  END b[131]
  PIN b[132]
    DIRECTION OUTPUT ;
    USE SIGNAL ;
    PORT
      LAYER M4 ;
        RECT  0 118.656 0.084 118.68 ;
    END
  END b[132]
  PIN b[133]
    DIRECTION OUTPUT ;
    USE SIGNAL ;
    PORT
      LAYER M4 ;
        RECT  0 118.8 0.084 118.824 ;
    END
  END b[133]
  PIN b[134]
    DIRECTION OUTPUT ;
    USE SIGNAL ;
    PORT
      LAYER M4 ;
        RECT  0 118.944 0.084 118.968 ;
    END
  END b[134]
  PIN b[135]
    DIRECTION OUTPUT ;
    USE SIGNAL ;
    PORT
      LAYER M4 ;
        RECT  0 119.088 0.084 119.112 ;
    END
  END b[135]
  PIN b[136]
    DIRECTION OUTPUT ;
    USE SIGNAL ;
    PORT
      LAYER M4 ;
        RECT  0 119.232 0.084 119.256 ;
    END
  END b[136]
  PIN b[137]
    DIRECTION OUTPUT ;
    USE SIGNAL ;
    PORT
      LAYER M4 ;
        RECT  0 119.376 0.084 119.4 ;
    END
  END b[137]
  PIN b[138]
    DIRECTION OUTPUT ;
    USE SIGNAL ;
    PORT
      LAYER M4 ;
        RECT  0 119.52 0.084 119.544 ;
    END
  END b[138]
  PIN b[139]
    DIRECTION OUTPUT ;
    USE SIGNAL ;
    PORT
      LAYER M4 ;
        RECT  0 119.664 0.084 119.688 ;
    END
  END b[139]
  PIN b[13]
    DIRECTION OUTPUT ;
    USE SIGNAL ;
    PORT
      LAYER M4 ;
        RECT  0 33.552 0.084 33.576 ;
    END
  END b[13]
  PIN b[140]
    DIRECTION OUTPUT ;
    USE SIGNAL ;
    PORT
      LAYER M4 ;
        RECT  0 119.808 0.084 119.832 ;
    END
  END b[140]
  PIN b[141]
    DIRECTION OUTPUT ;
    USE SIGNAL ;
    PORT
      LAYER M4 ;
        RECT  0 119.952 0.084 119.976 ;
    END
  END b[141]
  PIN b[142]
    DIRECTION OUTPUT ;
    USE SIGNAL ;
    PORT
      LAYER M4 ;
        RECT  0 120.096 0.084 120.12 ;
    END
  END b[142]
  PIN b[143]
    DIRECTION OUTPUT ;
    USE SIGNAL ;
    PORT
      LAYER M4 ;
        RECT  0 120.24 0.084 120.264 ;
    END
  END b[143]
  PIN b[144]
    DIRECTION OUTPUT ;
    USE SIGNAL ;
    PORT
      LAYER M4 ;
        RECT  0 120.384 0.084 120.408 ;
    END
  END b[144]
  PIN b[145]
    DIRECTION OUTPUT ;
    USE SIGNAL ;
    PORT
      LAYER M4 ;
        RECT  0 120.528 0.084 120.552 ;
    END
  END b[145]
  PIN b[146]
    DIRECTION OUTPUT ;
    USE SIGNAL ;
    PORT
      LAYER M4 ;
        RECT  0 120.672 0.084 120.696 ;
    END
  END b[146]
  PIN b[147]
    DIRECTION OUTPUT ;
    USE SIGNAL ;
    PORT
      LAYER M4 ;
        RECT  0 120.816 0.084 120.84 ;
    END
  END b[147]
  PIN b[148]
    DIRECTION OUTPUT ;
    USE SIGNAL ;
    PORT
      LAYER M4 ;
        RECT  0 120.96 0.084 120.984 ;
    END
  END b[148]
  PIN b[149]
    DIRECTION OUTPUT ;
    USE SIGNAL ;
    PORT
      LAYER M4 ;
        RECT  0 121.104 0.084 121.128 ;
    END
  END b[149]
  PIN b[14]
    DIRECTION OUTPUT ;
    USE SIGNAL ;
    PORT
      LAYER M4 ;
        RECT  0 33.696 0.084 33.72 ;
    END
  END b[14]
  PIN b[150]
    DIRECTION OUTPUT ;
    USE SIGNAL ;
    PORT
      LAYER M4 ;
        RECT  0 121.248 0.084 121.272 ;
    END
  END b[150]
  PIN b[151]
    DIRECTION OUTPUT ;
    USE SIGNAL ;
    PORT
      LAYER M4 ;
        RECT  0 121.392 0.084 121.416 ;
    END
  END b[151]
  PIN b[152]
    DIRECTION OUTPUT ;
    USE SIGNAL ;
    PORT
      LAYER M4 ;
        RECT  0 121.536 0.084 121.56 ;
    END
  END b[152]
  PIN b[153]
    DIRECTION OUTPUT ;
    USE SIGNAL ;
    PORT
      LAYER M4 ;
        RECT  0 121.68 0.084 121.704 ;
    END
  END b[153]
  PIN b[154]
    DIRECTION OUTPUT ;
    USE SIGNAL ;
    PORT
      LAYER M4 ;
        RECT  0 121.824 0.084 121.848 ;
    END
  END b[154]
  PIN b[155]
    DIRECTION OUTPUT ;
    USE SIGNAL ;
    PORT
      LAYER M4 ;
        RECT  0 121.968 0.084 121.992 ;
    END
  END b[155]
  PIN b[156]
    DIRECTION OUTPUT ;
    USE SIGNAL ;
    PORT
      LAYER M4 ;
        RECT  0 122.112 0.084 122.136 ;
    END
  END b[156]
  PIN b[157]
    DIRECTION OUTPUT ;
    USE SIGNAL ;
    PORT
      LAYER M4 ;
        RECT  0 122.256 0.084 122.28 ;
    END
  END b[157]
  PIN b[158]
    DIRECTION OUTPUT ;
    USE SIGNAL ;
    PORT
      LAYER M4 ;
        RECT  0 122.4 0.084 122.424 ;
    END
  END b[158]
  PIN b[159]
    DIRECTION OUTPUT ;
    USE SIGNAL ;
    PORT
      LAYER M4 ;
        RECT  0 122.544 0.084 122.568 ;
    END
  END b[159]
  PIN b[15]
    DIRECTION OUTPUT ;
    USE SIGNAL ;
    PORT
      LAYER M4 ;
        RECT  0 33.84 0.084 33.864 ;
    END
  END b[15]
  PIN b[160]
    DIRECTION OUTPUT ;
    USE SIGNAL ;
    PORT
      LAYER M4 ;
        RECT  0 128.592 0.084 128.616 ;
    END
  END b[160]
  PIN b[161]
    DIRECTION OUTPUT ;
    USE SIGNAL ;
    PORT
      LAYER M4 ;
        RECT  0 128.736 0.084 128.76 ;
    END
  END b[161]
  PIN b[162]
    DIRECTION OUTPUT ;
    USE SIGNAL ;
    PORT
      LAYER M4 ;
        RECT  0 128.88 0.084 128.904 ;
    END
  END b[162]
  PIN b[163]
    DIRECTION OUTPUT ;
    USE SIGNAL ;
    PORT
      LAYER M4 ;
        RECT  0 129.024 0.084 129.048 ;
    END
  END b[163]
  PIN b[164]
    DIRECTION OUTPUT ;
    USE SIGNAL ;
    PORT
      LAYER M4 ;
        RECT  0 129.168 0.084 129.192 ;
    END
  END b[164]
  PIN b[165]
    DIRECTION OUTPUT ;
    USE SIGNAL ;
    PORT
      LAYER M4 ;
        RECT  0 129.312 0.084 129.336 ;
    END
  END b[165]
  PIN b[166]
    DIRECTION OUTPUT ;
    USE SIGNAL ;
    PORT
      LAYER M4 ;
        RECT  0 129.456 0.084 129.48 ;
    END
  END b[166]
  PIN b[167]
    DIRECTION OUTPUT ;
    USE SIGNAL ;
    PORT
      LAYER M4 ;
        RECT  0 129.6 0.084 129.624 ;
    END
  END b[167]
  PIN b[168]
    DIRECTION OUTPUT ;
    USE SIGNAL ;
    PORT
      LAYER M4 ;
        RECT  0 129.744 0.084 129.768 ;
    END
  END b[168]
  PIN b[169]
    DIRECTION OUTPUT ;
    USE SIGNAL ;
    PORT
      LAYER M4 ;
        RECT  0 129.888 0.084 129.912 ;
    END
  END b[169]
  PIN b[16]
    DIRECTION OUTPUT ;
    USE SIGNAL ;
    PORT
      LAYER M4 ;
        RECT  0 33.984 0.084 34.008 ;
    END
  END b[16]
  PIN b[170]
    DIRECTION OUTPUT ;
    USE SIGNAL ;
    PORT
      LAYER M4 ;
        RECT  0 130.032 0.084 130.056 ;
    END
  END b[170]
  PIN b[171]
    DIRECTION OUTPUT ;
    USE SIGNAL ;
    PORT
      LAYER M4 ;
        RECT  0 130.176 0.084 130.2 ;
    END
  END b[171]
  PIN b[172]
    DIRECTION OUTPUT ;
    USE SIGNAL ;
    PORT
      LAYER M4 ;
        RECT  0 130.32 0.084 130.344 ;
    END
  END b[172]
  PIN b[173]
    DIRECTION OUTPUT ;
    USE SIGNAL ;
    PORT
      LAYER M4 ;
        RECT  0 130.464 0.084 130.488 ;
    END
  END b[173]
  PIN b[174]
    DIRECTION OUTPUT ;
    USE SIGNAL ;
    PORT
      LAYER M4 ;
        RECT  0 130.608 0.084 130.632 ;
    END
  END b[174]
  PIN b[175]
    DIRECTION OUTPUT ;
    USE SIGNAL ;
    PORT
      LAYER M4 ;
        RECT  0 130.752 0.084 130.776 ;
    END
  END b[175]
  PIN b[176]
    DIRECTION OUTPUT ;
    USE SIGNAL ;
    PORT
      LAYER M4 ;
        RECT  0 130.896 0.084 130.92 ;
    END
  END b[176]
  PIN b[177]
    DIRECTION OUTPUT ;
    USE SIGNAL ;
    PORT
      LAYER M4 ;
        RECT  0 131.04 0.084 131.064 ;
    END
  END b[177]
  PIN b[178]
    DIRECTION OUTPUT ;
    USE SIGNAL ;
    PORT
      LAYER M4 ;
        RECT  0 131.184 0.084 131.208 ;
    END
  END b[178]
  PIN b[179]
    DIRECTION OUTPUT ;
    USE SIGNAL ;
    PORT
      LAYER M4 ;
        RECT  0 131.328 0.084 131.352 ;
    END
  END b[179]
  PIN b[17]
    DIRECTION OUTPUT ;
    USE SIGNAL ;
    PORT
      LAYER M4 ;
        RECT  0 34.128 0.084 34.152 ;
    END
  END b[17]
  PIN b[180]
    DIRECTION OUTPUT ;
    USE SIGNAL ;
    PORT
      LAYER M4 ;
        RECT  0 131.472 0.084 131.496 ;
    END
  END b[180]
  PIN b[181]
    DIRECTION OUTPUT ;
    USE SIGNAL ;
    PORT
      LAYER M4 ;
        RECT  0 131.616 0.084 131.64 ;
    END
  END b[181]
  PIN b[182]
    DIRECTION OUTPUT ;
    USE SIGNAL ;
    PORT
      LAYER M4 ;
        RECT  0 131.76 0.084 131.784 ;
    END
  END b[182]
  PIN b[18]
    DIRECTION OUTPUT ;
    USE SIGNAL ;
    PORT
      LAYER M4 ;
        RECT  0 34.272 0.084 34.296 ;
    END
  END b[18]
  PIN b[19]
    DIRECTION OUTPUT ;
    USE SIGNAL ;
    PORT
      LAYER M4 ;
        RECT  0 34.416 0.084 34.44 ;
    END
  END b[19]
  PIN b[1]
    DIRECTION OUTPUT ;
    USE SIGNAL ;
    PORT
      LAYER M4 ;
        RECT  0 31.824 0.084 31.848 ;
    END
  END b[1]
  PIN b[20]
    DIRECTION OUTPUT ;
    USE SIGNAL ;
    PORT
      LAYER M4 ;
        RECT  0 34.56 0.084 34.584 ;
    END
  END b[20]
  PIN b[21]
    DIRECTION OUTPUT ;
    USE SIGNAL ;
    PORT
      LAYER M4 ;
        RECT  0 34.704 0.084 34.728 ;
    END
  END b[21]
  PIN b[22]
    DIRECTION OUTPUT ;
    USE SIGNAL ;
    PORT
      LAYER M4 ;
        RECT  0 34.848 0.084 34.872 ;
    END
  END b[22]
  PIN b[23]
    DIRECTION OUTPUT ;
    USE SIGNAL ;
    PORT
      LAYER M4 ;
        RECT  0 34.992 0.084 35.016 ;
    END
  END b[23]
  PIN b[24]
    DIRECTION OUTPUT ;
    USE SIGNAL ;
    PORT
      LAYER M4 ;
        RECT  0 35.136 0.084 35.16 ;
    END
  END b[24]
  PIN b[25]
    DIRECTION OUTPUT ;
    USE SIGNAL ;
    PORT
      LAYER M4 ;
        RECT  0 35.28 0.084 35.304 ;
    END
  END b[25]
  PIN b[26]
    DIRECTION OUTPUT ;
    USE SIGNAL ;
    PORT
      LAYER M4 ;
        RECT  0 35.424 0.084 35.448 ;
    END
  END b[26]
  PIN b[27]
    DIRECTION OUTPUT ;
    USE SIGNAL ;
    PORT
      LAYER M4 ;
        RECT  0 35.568 0.084 35.592 ;
    END
  END b[27]
  PIN b[28]
    DIRECTION OUTPUT ;
    USE SIGNAL ;
    PORT
      LAYER M4 ;
        RECT  0 35.712 0.084 35.736 ;
    END
  END b[28]
  PIN b[29]
    DIRECTION OUTPUT ;
    USE SIGNAL ;
    PORT
      LAYER M4 ;
        RECT  0 35.856 0.084 35.88 ;
    END
  END b[29]
  PIN b[2]
    DIRECTION OUTPUT ;
    USE SIGNAL ;
    PORT
      LAYER M4 ;
        RECT  0 31.968 0.084 31.992 ;
    END
  END b[2]
  PIN b[30]
    DIRECTION OUTPUT ;
    USE SIGNAL ;
    PORT
      LAYER M4 ;
        RECT  0 36 0.084 36.024 ;
    END
  END b[30]
  PIN b[31]
    DIRECTION OUTPUT ;
    USE SIGNAL ;
    PORT
      LAYER M4 ;
        RECT  0 36.144 0.084 36.168 ;
    END
  END b[31]
  PIN b[32]
    DIRECTION OUTPUT ;
    USE SIGNAL ;
    PORT
      LAYER M4 ;
        RECT  0 40.896 0.084 40.92 ;
    END
  END b[32]
  PIN b[33]
    DIRECTION OUTPUT ;
    USE SIGNAL ;
    PORT
      LAYER M4 ;
        RECT  0 41.04 0.084 41.064 ;
    END
  END b[33]
  PIN b[34]
    DIRECTION OUTPUT ;
    USE SIGNAL ;
    PORT
      LAYER M4 ;
        RECT  0 41.184 0.084 41.208 ;
    END
  END b[34]
  PIN b[35]
    DIRECTION OUTPUT ;
    USE SIGNAL ;
    PORT
      LAYER M4 ;
        RECT  0 41.328 0.084 41.352 ;
    END
  END b[35]
  PIN b[36]
    DIRECTION OUTPUT ;
    USE SIGNAL ;
    PORT
      LAYER M4 ;
        RECT  0 41.472 0.084 41.496 ;
    END
  END b[36]
  PIN b[37]
    DIRECTION OUTPUT ;
    USE SIGNAL ;
    PORT
      LAYER M4 ;
        RECT  0 41.616 0.084 41.64 ;
    END
  END b[37]
  PIN b[38]
    DIRECTION OUTPUT ;
    USE SIGNAL ;
    PORT
      LAYER M4 ;
        RECT  0 41.76 0.084 41.784 ;
    END
  END b[38]
  PIN b[39]
    DIRECTION OUTPUT ;
    USE SIGNAL ;
    PORT
      LAYER M4 ;
        RECT  0 41.904 0.084 41.928 ;
    END
  END b[39]
  PIN b[3]
    DIRECTION OUTPUT ;
    USE SIGNAL ;
    PORT
      LAYER M4 ;
        RECT  0 32.112 0.084 32.136 ;
    END
  END b[3]
  PIN b[40]
    DIRECTION OUTPUT ;
    USE SIGNAL ;
    PORT
      LAYER M4 ;
        RECT  0 42.048 0.084 42.072 ;
    END
  END b[40]
  PIN b[41]
    DIRECTION OUTPUT ;
    USE SIGNAL ;
    PORT
      LAYER M4 ;
        RECT  0 42.192 0.084 42.216 ;
    END
  END b[41]
  PIN b[42]
    DIRECTION OUTPUT ;
    USE SIGNAL ;
    PORT
      LAYER M4 ;
        RECT  0 42.336 0.084 42.36 ;
    END
  END b[42]
  PIN b[43]
    DIRECTION OUTPUT ;
    USE SIGNAL ;
    PORT
      LAYER M4 ;
        RECT  0 42.48 0.084 42.504 ;
    END
  END b[43]
  PIN b[44]
    DIRECTION OUTPUT ;
    USE SIGNAL ;
    PORT
      LAYER M4 ;
        RECT  0 42.624 0.084 42.648 ;
    END
  END b[44]
  PIN b[45]
    DIRECTION OUTPUT ;
    USE SIGNAL ;
    PORT
      LAYER M4 ;
        RECT  0 42.768 0.084 42.792 ;
    END
  END b[45]
  PIN b[46]
    DIRECTION OUTPUT ;
    USE SIGNAL ;
    PORT
      LAYER M4 ;
        RECT  0 42.912 0.084 42.936 ;
    END
  END b[46]
  PIN b[47]
    DIRECTION OUTPUT ;
    USE SIGNAL ;
    PORT
      LAYER M4 ;
        RECT  0 43.056 0.084 43.08 ;
    END
  END b[47]
  PIN b[48]
    DIRECTION OUTPUT ;
    USE SIGNAL ;
    PORT
      LAYER M4 ;
        RECT  0 43.2 0.084 43.224 ;
    END
  END b[48]
  PIN b[49]
    DIRECTION OUTPUT ;
    USE SIGNAL ;
    PORT
      LAYER M4 ;
        RECT  0 43.344 0.084 43.368 ;
    END
  END b[49]
  PIN b[4]
    DIRECTION OUTPUT ;
    USE SIGNAL ;
    PORT
      LAYER M4 ;
        RECT  0 32.256 0.084 32.28 ;
    END
  END b[4]
  PIN b[50]
    DIRECTION OUTPUT ;
    USE SIGNAL ;
    PORT
      LAYER M4 ;
        RECT  0 43.488 0.084 43.512 ;
    END
  END b[50]
  PIN b[51]
    DIRECTION OUTPUT ;
    USE SIGNAL ;
    PORT
      LAYER M4 ;
        RECT  0 43.632 0.084 43.656 ;
    END
  END b[51]
  PIN b[52]
    DIRECTION OUTPUT ;
    USE SIGNAL ;
    PORT
      LAYER M4 ;
        RECT  0 43.776 0.084 43.8 ;
    END
  END b[52]
  PIN b[53]
    DIRECTION OUTPUT ;
    USE SIGNAL ;
    PORT
      LAYER M4 ;
        RECT  0 43.92 0.084 43.944 ;
    END
  END b[53]
  PIN b[54]
    DIRECTION OUTPUT ;
    USE SIGNAL ;
    PORT
      LAYER M4 ;
        RECT  0 44.064 0.084 44.088 ;
    END
  END b[54]
  PIN b[55]
    DIRECTION OUTPUT ;
    USE SIGNAL ;
    PORT
      LAYER M4 ;
        RECT  0 44.208 0.084 44.232 ;
    END
  END b[55]
  PIN b[56]
    DIRECTION OUTPUT ;
    USE SIGNAL ;
    PORT
      LAYER M4 ;
        RECT  0 44.352 0.084 44.376 ;
    END
  END b[56]
  PIN b[57]
    DIRECTION OUTPUT ;
    USE SIGNAL ;
    PORT
      LAYER M4 ;
        RECT  0 44.496 0.084 44.52 ;
    END
  END b[57]
  PIN b[58]
    DIRECTION OUTPUT ;
    USE SIGNAL ;
    PORT
      LAYER M4 ;
        RECT  0 44.64 0.084 44.664 ;
    END
  END b[58]
  PIN b[59]
    DIRECTION OUTPUT ;
    USE SIGNAL ;
    PORT
      LAYER M4 ;
        RECT  0 44.784 0.084 44.808 ;
    END
  END b[59]
  PIN b[5]
    DIRECTION OUTPUT ;
    USE SIGNAL ;
    PORT
      LAYER M4 ;
        RECT  0 32.4 0.084 32.424 ;
    END
  END b[5]
  PIN b[60]
    DIRECTION OUTPUT ;
    USE SIGNAL ;
    PORT
      LAYER M4 ;
        RECT  0 44.928 0.084 44.952 ;
    END
  END b[60]
  PIN b[61]
    DIRECTION OUTPUT ;
    USE SIGNAL ;
    PORT
      LAYER M4 ;
        RECT  0 45.072 0.084 45.096 ;
    END
  END b[61]
  PIN b[62]
    DIRECTION OUTPUT ;
    USE SIGNAL ;
    PORT
      LAYER M4 ;
        RECT  0 45.216 0.084 45.24 ;
    END
  END b[62]
  PIN b[63]
    DIRECTION OUTPUT ;
    USE SIGNAL ;
    PORT
      LAYER M4 ;
        RECT  0 45.36 0.084 45.384 ;
    END
  END b[63]
  PIN b[64]
    DIRECTION OUTPUT ;
    USE SIGNAL ;
    PORT
      LAYER M4 ;
        RECT  0 74.304 0.084 74.328 ;
    END
  END b[64]
  PIN b[65]
    DIRECTION OUTPUT ;
    USE SIGNAL ;
    PORT
      LAYER M4 ;
        RECT  0 74.448 0.084 74.472 ;
    END
  END b[65]
  PIN b[66]
    DIRECTION OUTPUT ;
    USE SIGNAL ;
    PORT
      LAYER M4 ;
        RECT  0 74.592 0.084 74.616 ;
    END
  END b[66]
  PIN b[67]
    DIRECTION OUTPUT ;
    USE SIGNAL ;
    PORT
      LAYER M4 ;
        RECT  0 74.736 0.084 74.76 ;
    END
  END b[67]
  PIN b[68]
    DIRECTION OUTPUT ;
    USE SIGNAL ;
    PORT
      LAYER M4 ;
        RECT  0 74.88 0.084 74.904 ;
    END
  END b[68]
  PIN b[69]
    DIRECTION OUTPUT ;
    USE SIGNAL ;
    PORT
      LAYER M4 ;
        RECT  0 75.024 0.084 75.048 ;
    END
  END b[69]
  PIN b[6]
    DIRECTION OUTPUT ;
    USE SIGNAL ;
    PORT
      LAYER M4 ;
        RECT  0 32.544 0.084 32.568 ;
    END
  END b[6]
  PIN b[70]
    DIRECTION OUTPUT ;
    USE SIGNAL ;
    PORT
      LAYER M4 ;
        RECT  0 75.168 0.084 75.192 ;
    END
  END b[70]
  PIN b[71]
    DIRECTION OUTPUT ;
    USE SIGNAL ;
    PORT
      LAYER M4 ;
        RECT  0 75.312 0.084 75.336 ;
    END
  END b[71]
  PIN b[72]
    DIRECTION OUTPUT ;
    USE SIGNAL ;
    PORT
      LAYER M4 ;
        RECT  0 75.456 0.084 75.48 ;
    END
  END b[72]
  PIN b[73]
    DIRECTION OUTPUT ;
    USE SIGNAL ;
    PORT
      LAYER M4 ;
        RECT  0 75.6 0.084 75.624 ;
    END
  END b[73]
  PIN b[74]
    DIRECTION OUTPUT ;
    USE SIGNAL ;
    PORT
      LAYER M4 ;
        RECT  0 75.744 0.084 75.768 ;
    END
  END b[74]
  PIN b[75]
    DIRECTION OUTPUT ;
    USE SIGNAL ;
    PORT
      LAYER M4 ;
        RECT  0 75.888 0.084 75.912 ;
    END
  END b[75]
  PIN b[76]
    DIRECTION OUTPUT ;
    USE SIGNAL ;
    PORT
      LAYER M4 ;
        RECT  0 76.032 0.084 76.056 ;
    END
  END b[76]
  PIN b[77]
    DIRECTION OUTPUT ;
    USE SIGNAL ;
    PORT
      LAYER M4 ;
        RECT  0 76.176 0.084 76.2 ;
    END
  END b[77]
  PIN b[78]
    DIRECTION OUTPUT ;
    USE SIGNAL ;
    PORT
      LAYER M4 ;
        RECT  0 76.32 0.084 76.344 ;
    END
  END b[78]
  PIN b[79]
    DIRECTION OUTPUT ;
    USE SIGNAL ;
    PORT
      LAYER M4 ;
        RECT  0 76.464 0.084 76.488 ;
    END
  END b[79]
  PIN b[7]
    DIRECTION OUTPUT ;
    USE SIGNAL ;
    PORT
      LAYER M4 ;
        RECT  0 32.688 0.084 32.712 ;
    END
  END b[7]
  PIN b[80]
    DIRECTION OUTPUT ;
    USE SIGNAL ;
    PORT
      LAYER M4 ;
        RECT  0 76.608 0.084 76.632 ;
    END
  END b[80]
  PIN b[81]
    DIRECTION OUTPUT ;
    USE SIGNAL ;
    PORT
      LAYER M4 ;
        RECT  0 76.752 0.084 76.776 ;
    END
  END b[81]
  PIN b[82]
    DIRECTION OUTPUT ;
    USE SIGNAL ;
    PORT
      LAYER M4 ;
        RECT  0 76.896 0.084 76.92 ;
    END
  END b[82]
  PIN b[83]
    DIRECTION OUTPUT ;
    USE SIGNAL ;
    PORT
      LAYER M4 ;
        RECT  0 77.04 0.084 77.064 ;
    END
  END b[83]
  PIN b[84]
    DIRECTION OUTPUT ;
    USE SIGNAL ;
    PORT
      LAYER M4 ;
        RECT  0 77.184 0.084 77.208 ;
    END
  END b[84]
  PIN b[85]
    DIRECTION OUTPUT ;
    USE SIGNAL ;
    PORT
      LAYER M4 ;
        RECT  0 77.328 0.084 77.352 ;
    END
  END b[85]
  PIN b[86]
    DIRECTION OUTPUT ;
    USE SIGNAL ;
    PORT
      LAYER M4 ;
        RECT  0 77.472 0.084 77.496 ;
    END
  END b[86]
  PIN b[87]
    DIRECTION OUTPUT ;
    USE SIGNAL ;
    PORT
      LAYER M4 ;
        RECT  0 77.616 0.084 77.64 ;
    END
  END b[87]
  PIN b[88]
    DIRECTION OUTPUT ;
    USE SIGNAL ;
    PORT
      LAYER M4 ;
        RECT  0 77.76 0.084 77.784 ;
    END
  END b[88]
  PIN b[89]
    DIRECTION OUTPUT ;
    USE SIGNAL ;
    PORT
      LAYER M4 ;
        RECT  0 77.904 0.084 77.928 ;
    END
  END b[89]
  PIN b[8]
    DIRECTION OUTPUT ;
    USE SIGNAL ;
    PORT
      LAYER M4 ;
        RECT  0 32.832 0.084 32.856 ;
    END
  END b[8]
  PIN b[90]
    DIRECTION OUTPUT ;
    USE SIGNAL ;
    PORT
      LAYER M4 ;
        RECT  0 78.048 0.084 78.072 ;
    END
  END b[90]
  PIN b[91]
    DIRECTION OUTPUT ;
    USE SIGNAL ;
    PORT
      LAYER M4 ;
        RECT  0 78.192 0.084 78.216 ;
    END
  END b[91]
  PIN b[92]
    DIRECTION OUTPUT ;
    USE SIGNAL ;
    PORT
      LAYER M4 ;
        RECT  0 78.336 0.084 78.36 ;
    END
  END b[92]
  PIN b[93]
    DIRECTION OUTPUT ;
    USE SIGNAL ;
    PORT
      LAYER M4 ;
        RECT  0 78.48 0.084 78.504 ;
    END
  END b[93]
  PIN b[94]
    DIRECTION OUTPUT ;
    USE SIGNAL ;
    PORT
      LAYER M4 ;
        RECT  0 78.624 0.084 78.648 ;
    END
  END b[94]
  PIN b[95]
    DIRECTION OUTPUT ;
    USE SIGNAL ;
    PORT
      LAYER M4 ;
        RECT  0 78.768 0.084 78.792 ;
    END
  END b[95]
  PIN b[96]
    DIRECTION OUTPUT ;
    USE SIGNAL ;
    PORT
      LAYER M4 ;
        RECT  0 84.672 0.084 84.696 ;
    END
  END b[96]
  PIN b[97]
    DIRECTION OUTPUT ;
    USE SIGNAL ;
    PORT
      LAYER M4 ;
        RECT  0 84.816 0.084 84.84 ;
    END
  END b[97]
  PIN b[98]
    DIRECTION OUTPUT ;
    USE SIGNAL ;
    PORT
      LAYER M4 ;
        RECT  0 84.96 0.084 84.984 ;
    END
  END b[98]
  PIN b[99]
    DIRECTION OUTPUT ;
    USE SIGNAL ;
    PORT
      LAYER M4 ;
        RECT  0 85.104 0.084 85.128 ;
    END
  END b[99]
  PIN b[9]
    DIRECTION OUTPUT ;
    USE SIGNAL ;
    PORT
      LAYER M4 ;
        RECT  0 32.976 0.084 33 ;
    END
  END b[9]
  PIN ck
    DIRECTION INPUT ;
    USE SIGNAL ;
    PORT
      LAYER M3 ;
        RECT  37.908 170.603 37.926 170.64 ;
    END
  END ck
  PIN ck_s
    DIRECTION INPUT ;
    USE SIGNAL ;
    PORT
      LAYER M3 ;
        RECT  38.016 170.603 38.034 170.64 ;
    END
  END ck_s
  PIN en
    DIRECTION INPUT ;
    USE SIGNAL ;
    PORT
      LAYER M3 ;
        RECT  38.124 170.603 38.142 170.64 ;
    END
  END en
  PIN fault
    DIRECTION OUTPUT ;
    USE SIGNAL ;
    PORT
      LAYER M3 ;
        RECT  38.232 170.603 38.25 170.64 ;
    END
  END fault
  PIN k0
    DIRECTION INPUT ;
    USE SIGNAL ;
    PORT
      LAYER M3 ;
        RECT  38.34 170.603 38.358 170.64 ;
    END
  END k0
  PIN k1
    DIRECTION INPUT ;
    USE SIGNAL ;
    PORT
      LAYER M3 ;
        RECT  38.448 170.603 38.466 170.64 ;
    END
  END k1
  PIN k2
    DIRECTION INPUT ;
    USE SIGNAL ;
    PORT
      LAYER M3 ;
        RECT  38.556 170.603 38.574 170.64 ;
    END
  END k2
  PIN k3
    DIRECTION INPUT ;
    USE SIGNAL ;
    PORT
      LAYER M3 ;
        RECT  38.664 170.603 38.682 170.64 ;
    END
  END k3
  PIN rs
    DIRECTION INPUT ;
    USE SIGNAL ;
    PORT
      LAYER M3 ;
        RECT  38.772 170.603 38.79 170.64 ;
    END
  END rs
  PIN tie_hi
    DIRECTION OUTPUT ;
    USE SIGNAL ;
    PORT
      LAYER M3 ;
        RECT  38.88 170.603 38.898 170.64 ;
    END
  END tie_hi
  PIN tie_lo
    DIRECTION OUTPUT ;
    USE SIGNAL ;
    PORT
      LAYER M3 ;
        RECT  38.988 170.603 39.006 170.64 ;
    END
  END tie_lo
  PIN VDD
    DIRECTION INOUT ;
    USE POWER ;
    PORT
      LAYER M5 ;
        RECT  94.392 2.151 94.512 168.489 ;
        RECT  91.692 2.151 91.812 168.489 ;
        RECT  88.992 2.151 89.112 168.489 ;
        RECT  86.292 2.151 86.412 168.489 ;
        RECT  83.592 2.151 83.712 168.489 ;
        RECT  80.892 2.151 81.012 168.489 ;
        RECT  78.192 2.151 78.312 168.489 ;
        RECT  75.492 2.151 75.612 168.489 ;
        RECT  72.792 2.151 72.912 168.489 ;
        RECT  70.092 2.151 70.212 168.489 ;
        RECT  67.392 2.151 67.512 168.489 ;
        RECT  64.692 2.151 64.812 168.489 ;
        RECT  61.992 2.151 62.112 168.489 ;
        RECT  59.292 2.151 59.412 168.489 ;
        RECT  56.592 2.151 56.712 168.489 ;
        RECT  53.892 2.151 54.012 168.489 ;
        RECT  51.192 2.151 51.312 168.489 ;
        RECT  48.492 2.151 48.612 168.489 ;
        RECT  45.792 2.151 45.912 168.489 ;
        RECT  43.092 2.151 43.212 168.489 ;
        RECT  40.392 2.151 40.512 168.489 ;
        RECT  37.692 2.151 37.812 168.489 ;
        RECT  34.992 2.151 35.112 168.489 ;
        RECT  32.292 2.151 32.412 168.489 ;
        RECT  29.592 2.151 29.712 168.489 ;
        RECT  26.892 2.151 27.012 168.489 ;
        RECT  24.192 2.151 24.312 168.489 ;
        RECT  21.492 2.151 21.612 168.489 ;
        RECT  18.792 2.151 18.912 168.489 ;
        RECT  16.092 2.151 16.212 168.489 ;
        RECT  13.392 2.151 13.512 168.489 ;
        RECT  10.692 2.151 10.812 168.489 ;
        RECT  7.992 2.151 8.112 168.489 ;
        RECT  5.292 2.151 5.412 168.489 ;
        RECT  2.592 2.151 2.712 168.489 ;
    END
  END VDD
  PIN VSS
    DIRECTION INOUT ;
    USE GROUND ;
    PORT
      LAYER M5 ;
        RECT  94.2 2.137 94.32 168.503 ;
        RECT  91.5 2.137 91.62 168.503 ;
        RECT  88.8 2.137 88.92 168.503 ;
        RECT  86.1 2.137 86.22 168.503 ;
        RECT  83.4 2.137 83.52 168.503 ;
        RECT  80.7 2.137 80.82 168.503 ;
        RECT  78 2.137 78.12 168.503 ;
        RECT  75.3 2.137 75.42 168.503 ;
        RECT  72.6 2.137 72.72 168.503 ;
        RECT  69.9 2.137 70.02 168.503 ;
        RECT  67.2 2.137 67.32 168.503 ;
        RECT  64.5 2.137 64.62 168.503 ;
        RECT  61.8 2.137 61.92 168.503 ;
        RECT  59.1 2.137 59.22 168.503 ;
        RECT  56.4 2.137 56.52 168.503 ;
        RECT  53.7 2.137 53.82 168.503 ;
        RECT  51 2.137 51.12 168.503 ;
        RECT  48.3 2.137 48.42 168.503 ;
        RECT  45.6 2.137 45.72 168.503 ;
        RECT  42.9 2.137 43.02 168.503 ;
        RECT  40.2 2.137 40.32 168.503 ;
        RECT  37.5 2.137 37.62 168.503 ;
        RECT  34.8 2.137 34.92 168.503 ;
        RECT  32.1 2.137 32.22 168.503 ;
        RECT  29.4 2.137 29.52 168.503 ;
        RECT  26.7 2.137 26.82 168.503 ;
        RECT  24 2.137 24.12 168.503 ;
        RECT  21.3 2.137 21.42 168.503 ;
        RECT  18.6 2.137 18.72 168.503 ;
        RECT  15.9 2.137 16.02 168.503 ;
        RECT  13.2 2.137 13.32 168.503 ;
        RECT  10.5 2.137 10.62 168.503 ;
        RECT  7.8 2.137 7.92 168.503 ;
        RECT  5.1 2.137 5.22 168.503 ;
        RECT  2.4 2.137 2.52 168.503 ;
    END
  END VSS
  # OT_OBS_CLOSED layer=M5 d_um=1.536 added=70
  OBS
    LAYER RVTN ;
     RECT  2.16 2.16 96.12 2.295 ;
     RECT  2.16 2.565 96.12 2.835 ;
     RECT  2.16 3.105 96.12 3.375 ;
     RECT  2.16 3.645 96.12 3.915 ;
     RECT  2.16 4.185 96.12 4.455 ;
     RECT  2.16 4.725 96.12 4.995 ;
     RECT  2.16 5.265 96.12 5.535 ;
     RECT  2.16 5.805 96.12 6.075 ;
     RECT  2.16 6.345 96.12 6.615 ;
     RECT  2.16 6.885 96.12 7.155 ;
     RECT  2.16 7.425 96.12 7.695 ;
     RECT  2.16 7.965 96.12 8.235 ;
     RECT  2.16 8.505 96.12 8.775 ;
     RECT  2.16 9.045 96.12 9.315 ;
     RECT  2.16 9.585 96.12 9.855 ;
     RECT  2.16 10.125 96.12 10.395 ;
     RECT  2.16 10.665 96.12 10.935 ;
     RECT  2.16 11.205 96.12 11.475 ;
     RECT  2.16 11.745 96.12 12.015 ;
     RECT  2.16 12.285 96.12 12.555 ;
     RECT  2.16 12.825 96.12 13.095 ;
     RECT  2.16 13.365 96.12 13.635 ;
     RECT  2.16 13.905 96.12 14.175 ;
     RECT  2.16 14.445 96.12 14.715 ;
     RECT  2.16 14.985 96.12 15.255 ;
     RECT  2.16 15.525 96.12 15.795 ;
     RECT  2.16 16.065 96.12 16.335 ;
     RECT  2.16 16.605 96.12 16.875 ;
     RECT  2.16 17.145 96.12 17.415 ;
     RECT  2.16 17.685 96.12 17.955 ;
     RECT  2.16 18.225 96.12 18.495 ;
     RECT  2.16 18.765 96.12 19.035 ;
     RECT  2.16 19.305 96.12 19.575 ;
     RECT  2.16 19.845 96.12 20.115 ;
     RECT  2.16 20.385 96.12 20.655 ;
     RECT  2.16 20.925 96.12 21.195 ;
     RECT  2.16 21.465 96.12 21.735 ;
     RECT  2.16 22.005 96.12 22.275 ;
     RECT  2.16 22.545 96.12 22.815 ;
     RECT  2.16 23.085 96.12 23.355 ;
     RECT  2.16 23.625 96.12 23.895 ;
     RECT  2.16 24.165 96.12 24.435 ;
     RECT  2.16 24.705 96.12 24.975 ;
     RECT  2.16 25.245 96.12 25.515 ;
     RECT  2.16 25.785 96.12 26.055 ;
     RECT  2.16 26.325 96.12 26.595 ;
     RECT  2.16 26.865 96.12 27.135 ;
     RECT  2.16 27.405 96.12 27.675 ;
     RECT  2.16 27.945 96.12 28.215 ;
     RECT  2.16 28.485 96.12 28.755 ;
     RECT  2.16 29.025 96.12 29.295 ;
     RECT  2.16 29.565 96.12 29.835 ;
     RECT  2.16 30.105 96.12 30.375 ;
     RECT  2.16 30.645 96.12 30.915 ;
     RECT  2.16 31.185 96.12 31.455 ;
     RECT  2.16 31.725 96.12 31.995 ;
     RECT  2.16 32.265 96.12 32.535 ;
     RECT  2.16 32.805 96.12 33.075 ;
     RECT  2.16 33.345 96.12 33.615 ;
     RECT  2.16 33.885 96.12 34.155 ;
     RECT  2.16 34.425 96.12 34.695 ;
     RECT  2.16 34.965 96.12 35.235 ;
     RECT  2.16 35.505 96.12 35.775 ;
     RECT  2.16 36.045 96.12 36.315 ;
     RECT  2.16 36.585 96.12 36.855 ;
     RECT  2.16 37.125 96.12 37.395 ;
     RECT  2.16 37.665 96.12 37.935 ;
     RECT  2.16 38.205 96.12 38.475 ;
     RECT  2.16 38.745 96.12 39.015 ;
     RECT  2.16 39.285 96.12 39.555 ;
     RECT  2.16 39.825 96.12 40.095 ;
     RECT  2.16 40.365 96.12 40.635 ;
     RECT  2.16 40.905 96.12 41.04 ;
     RECT  2.16 41.04 41.148 41.175 ;
     RECT  77.22 41.04 96.12 41.175 ;
     RECT  2.16 41.445 41.148 41.715 ;
     RECT  77.22 41.445 96.12 41.715 ;
     RECT  2.16 41.985 41.148 42.255 ;
     RECT  77.22 41.985 96.12 42.255 ;
     RECT  2.16 42.525 41.148 42.795 ;
     RECT  77.22 42.525 96.12 42.795 ;
     RECT  2.16 43.065 41.148 43.335 ;
     RECT  77.22 43.065 96.12 43.335 ;
     RECT  2.16 43.605 41.148 43.875 ;
     RECT  77.22 43.605 96.12 43.875 ;
     RECT  2.16 44.145 41.148 44.415 ;
     RECT  77.22 44.145 96.12 44.415 ;
     RECT  2.16 44.685 41.148 44.955 ;
     RECT  77.22 44.685 96.12 44.955 ;
     RECT  2.16 45.225 41.148 45.495 ;
     RECT  77.22 45.225 96.12 45.495 ;
     RECT  2.16 45.765 41.148 46.035 ;
     RECT  77.22 45.765 96.12 46.035 ;
     RECT  2.16 46.305 41.148 46.575 ;
     RECT  77.22 46.305 96.12 46.575 ;
     RECT  2.16 46.845 41.148 47.115 ;
     RECT  77.22 46.845 96.12 47.115 ;
     RECT  2.16 47.385 41.148 47.655 ;
     RECT  77.22 47.385 96.12 47.655 ;
     RECT  2.16 47.925 41.148 48.195 ;
     RECT  77.22 47.925 96.12 48.195 ;
     RECT  2.16 48.465 41.148 48.735 ;
     RECT  77.22 48.465 96.12 48.735 ;
     RECT  2.16 49.005 41.148 49.275 ;
     RECT  77.22 49.005 96.12 49.275 ;
     RECT  2.16 49.545 41.148 49.815 ;
     RECT  77.22 49.545 96.12 49.815 ;
     RECT  2.16 50.085 41.148 50.355 ;
     RECT  77.22 50.085 96.12 50.355 ;
     RECT  2.16 50.625 41.148 50.895 ;
     RECT  77.22 50.625 96.12 50.895 ;
     RECT  2.16 51.165 41.148 51.435 ;
     RECT  77.22 51.165 96.12 51.435 ;
     RECT  2.16 51.705 41.148 51.975 ;
     RECT  77.22 51.705 96.12 51.975 ;
     RECT  2.16 52.245 41.148 52.515 ;
     RECT  77.22 52.245 96.12 52.515 ;
     RECT  2.16 52.785 41.148 53.055 ;
     RECT  77.22 52.785 96.12 53.055 ;
     RECT  2.16 53.325 41.148 53.595 ;
     RECT  77.22 53.325 96.12 53.595 ;
     RECT  2.16 53.865 41.148 54.135 ;
     RECT  77.22 53.865 96.12 54.135 ;
     RECT  2.16 54.405 41.148 54.675 ;
     RECT  77.22 54.405 96.12 54.675 ;
     RECT  2.16 54.945 41.148 55.215 ;
     RECT  77.22 54.945 96.12 55.215 ;
     RECT  2.16 55.485 41.148 55.755 ;
     RECT  77.22 55.485 96.12 55.755 ;
     RECT  2.16 56.025 41.148 56.295 ;
     RECT  77.22 56.025 96.12 56.295 ;
     RECT  2.16 56.565 41.148 56.835 ;
     RECT  77.22 56.565 96.12 56.835 ;
     RECT  2.16 57.105 41.148 57.375 ;
     RECT  77.22 57.105 96.12 57.375 ;
     RECT  2.16 57.645 41.148 57.915 ;
     RECT  77.22 57.645 96.12 57.915 ;
     RECT  2.16 58.185 41.148 58.455 ;
     RECT  77.22 58.185 96.12 58.455 ;
     RECT  2.16 58.725 41.148 58.995 ;
     RECT  77.22 58.725 96.12 58.995 ;
     RECT  2.16 59.265 41.148 59.535 ;
     RECT  77.22 59.265 96.12 59.535 ;
     RECT  2.16 59.805 41.148 60.075 ;
     RECT  77.22 59.805 96.12 60.075 ;
     RECT  2.16 60.345 41.148 60.615 ;
     RECT  77.22 60.345 96.12 60.615 ;
     RECT  2.16 60.885 41.148 61.155 ;
     RECT  77.22 60.885 96.12 61.155 ;
     RECT  2.16 61.425 41.148 61.695 ;
     RECT  77.22 61.425 96.12 61.695 ;
     RECT  2.16 61.965 41.148 62.235 ;
     RECT  77.22 61.965 96.12 62.235 ;
     RECT  2.16 62.505 41.148 62.64 ;
     RECT  77.22 62.505 96.12 62.64 ;
     RECT  2.16 62.64 96.12 62.775 ;
     RECT  2.16 63.045 96.12 63.315 ;
     RECT  2.16 63.585 96.12 63.855 ;
     RECT  2.16 64.125 96.12 64.395 ;
     RECT  2.16 64.665 96.12 64.935 ;
     RECT  2.16 65.205 96.12 65.475 ;
     RECT  2.16 65.745 96.12 66.015 ;
     RECT  2.16 66.285 96.12 66.555 ;
     RECT  2.16 66.825 96.12 67.095 ;
     RECT  2.16 67.365 96.12 67.635 ;
     RECT  2.16 67.905 96.12 68.175 ;
     RECT  2.16 68.445 96.12 68.715 ;
     RECT  2.16 68.985 96.12 69.255 ;
     RECT  2.16 69.525 96.12 69.795 ;
     RECT  2.16 70.065 96.12 70.335 ;
     RECT  2.16 70.605 96.12 70.875 ;
     RECT  2.16 71.145 96.12 71.415 ;
     RECT  2.16 71.685 96.12 71.955 ;
     RECT  2.16 72.225 96.12 72.495 ;
     RECT  2.16 72.765 96.12 73.035 ;
     RECT  2.16 73.305 96.12 73.575 ;
     RECT  2.16 73.845 96.12 74.115 ;
     RECT  2.16 74.385 96.12 74.655 ;
     RECT  2.16 74.925 96.12 75.195 ;
     RECT  2.16 75.465 96.12 75.735 ;
     RECT  2.16 76.005 96.12 76.275 ;
     RECT  2.16 76.545 96.12 76.815 ;
     RECT  2.16 77.085 96.12 77.355 ;
     RECT  2.16 77.625 96.12 77.895 ;
     RECT  2.16 78.165 96.12 78.435 ;
     RECT  2.16 78.705 96.12 78.975 ;
     RECT  2.16 79.245 96.12 79.515 ;
     RECT  2.16 79.785 96.12 80.055 ;
     RECT  2.16 80.325 96.12 80.595 ;
     RECT  2.16 80.865 96.12 81.135 ;
     RECT  2.16 81.405 96.12 81.675 ;
     RECT  2.16 81.945 96.12 82.215 ;
     RECT  2.16 82.485 96.12 82.755 ;
     RECT  2.16 83.025 96.12 83.295 ;
     RECT  2.16 83.565 96.12 83.835 ;
     RECT  2.16 84.105 96.12 84.24 ;
     RECT  2.16 84.24 41.148 84.375 ;
     RECT  77.22 84.24 96.12 84.375 ;
     RECT  2.16 84.645 41.148 84.915 ;
     RECT  77.22 84.645 96.12 84.915 ;
     RECT  2.16 85.185 41.148 85.455 ;
     RECT  77.22 85.185 96.12 85.455 ;
     RECT  2.16 85.725 41.148 85.995 ;
     RECT  77.22 85.725 96.12 85.995 ;
     RECT  2.16 86.265 41.148 86.535 ;
     RECT  77.22 86.265 96.12 86.535 ;
     RECT  2.16 86.805 41.148 87.075 ;
     RECT  77.22 86.805 96.12 87.075 ;
     RECT  2.16 87.345 41.148 87.615 ;
     RECT  77.22 87.345 96.12 87.615 ;
     RECT  2.16 87.885 41.148 88.155 ;
     RECT  77.22 87.885 96.12 88.155 ;
     RECT  2.16 88.425 41.148 88.695 ;
     RECT  77.22 88.425 96.12 88.695 ;
     RECT  2.16 88.965 41.148 89.235 ;
     RECT  77.22 88.965 96.12 89.235 ;
     RECT  2.16 89.505 41.148 89.775 ;
     RECT  77.22 89.505 96.12 89.775 ;
     RECT  2.16 90.045 41.148 90.315 ;
     RECT  77.22 90.045 96.12 90.315 ;
     RECT  2.16 90.585 41.148 90.855 ;
     RECT  77.22 90.585 96.12 90.855 ;
     RECT  2.16 91.125 41.148 91.395 ;
     RECT  77.22 91.125 96.12 91.395 ;
     RECT  2.16 91.665 41.148 91.935 ;
     RECT  77.22 91.665 96.12 91.935 ;
     RECT  2.16 92.205 41.148 92.475 ;
     RECT  77.22 92.205 96.12 92.475 ;
     RECT  2.16 92.745 41.148 93.015 ;
     RECT  77.22 92.745 96.12 93.015 ;
     RECT  2.16 93.285 41.148 93.555 ;
     RECT  77.22 93.285 96.12 93.555 ;
     RECT  2.16 93.825 41.148 94.095 ;
     RECT  77.22 93.825 96.12 94.095 ;
     RECT  2.16 94.365 41.148 94.635 ;
     RECT  77.22 94.365 96.12 94.635 ;
     RECT  2.16 94.905 41.148 95.175 ;
     RECT  77.22 94.905 96.12 95.175 ;
     RECT  2.16 95.445 41.148 95.715 ;
     RECT  77.22 95.445 96.12 95.715 ;
     RECT  2.16 95.985 41.148 96.255 ;
     RECT  77.22 95.985 96.12 96.255 ;
     RECT  2.16 96.525 41.148 96.795 ;
     RECT  77.22 96.525 96.12 96.795 ;
     RECT  2.16 97.065 41.148 97.335 ;
     RECT  77.22 97.065 96.12 97.335 ;
     RECT  2.16 97.605 41.148 97.875 ;
     RECT  77.22 97.605 96.12 97.875 ;
     RECT  2.16 98.145 41.148 98.415 ;
     RECT  77.22 98.145 96.12 98.415 ;
     RECT  2.16 98.685 41.148 98.955 ;
     RECT  77.22 98.685 96.12 98.955 ;
     RECT  2.16 99.225 41.148 99.495 ;
     RECT  77.22 99.225 96.12 99.495 ;
     RECT  2.16 99.765 41.148 100.035 ;
     RECT  77.22 99.765 96.12 100.035 ;
     RECT  2.16 100.305 41.148 100.575 ;
     RECT  77.22 100.305 96.12 100.575 ;
     RECT  2.16 100.845 41.148 101.115 ;
     RECT  77.22 100.845 96.12 101.115 ;
     RECT  2.16 101.385 41.148 101.655 ;
     RECT  77.22 101.385 96.12 101.655 ;
     RECT  2.16 101.925 41.148 102.195 ;
     RECT  77.22 101.925 96.12 102.195 ;
     RECT  2.16 102.465 41.148 102.735 ;
     RECT  77.22 102.465 96.12 102.735 ;
     RECT  2.16 103.005 41.148 103.275 ;
     RECT  77.22 103.005 96.12 103.275 ;
     RECT  2.16 103.545 41.148 103.815 ;
     RECT  77.22 103.545 96.12 103.815 ;
     RECT  2.16 104.085 41.148 104.355 ;
     RECT  77.22 104.085 96.12 104.355 ;
     RECT  2.16 104.625 41.148 104.895 ;
     RECT  77.22 104.625 96.12 104.895 ;
     RECT  2.16 105.165 41.148 105.435 ;
     RECT  77.22 105.165 96.12 105.435 ;
     RECT  2.16 105.705 41.148 105.84 ;
     RECT  77.22 105.705 96.12 105.84 ;
     RECT  2.16 105.84 96.12 105.975 ;
     RECT  2.16 106.245 96.12 106.515 ;
     RECT  2.16 106.785 96.12 107.055 ;
     RECT  2.16 107.325 96.12 107.595 ;
     RECT  2.16 107.865 96.12 108.135 ;
     RECT  2.16 108.405 96.12 108.675 ;
     RECT  2.16 108.945 96.12 109.215 ;
     RECT  2.16 109.485 96.12 109.755 ;
     RECT  2.16 110.025 96.12 110.295 ;
     RECT  2.16 110.565 96.12 110.835 ;
     RECT  2.16 111.105 96.12 111.375 ;
     RECT  2.16 111.645 96.12 111.915 ;
     RECT  2.16 112.185 96.12 112.455 ;
     RECT  2.16 112.725 96.12 112.995 ;
     RECT  2.16 113.265 96.12 113.535 ;
     RECT  2.16 113.805 96.12 114.075 ;
     RECT  2.16 114.345 96.12 114.615 ;
     RECT  2.16 114.885 96.12 115.155 ;
     RECT  2.16 115.425 96.12 115.695 ;
     RECT  2.16 115.965 96.12 116.235 ;
     RECT  2.16 116.505 96.12 116.775 ;
     RECT  2.16 117.045 96.12 117.315 ;
     RECT  2.16 117.585 96.12 117.855 ;
     RECT  2.16 118.125 96.12 118.395 ;
     RECT  2.16 118.665 96.12 118.935 ;
     RECT  2.16 119.205 96.12 119.475 ;
     RECT  2.16 119.745 96.12 120.015 ;
     RECT  2.16 120.285 96.12 120.555 ;
     RECT  2.16 120.825 96.12 121.095 ;
     RECT  2.16 121.365 96.12 121.635 ;
     RECT  2.16 121.905 96.12 122.175 ;
     RECT  2.16 122.445 96.12 122.715 ;
     RECT  2.16 122.985 96.12 123.255 ;
     RECT  2.16 123.525 96.12 123.795 ;
     RECT  2.16 124.065 96.12 124.335 ;
     RECT  2.16 124.605 96.12 124.875 ;
     RECT  2.16 125.145 96.12 125.415 ;
     RECT  2.16 125.685 96.12 125.955 ;
     RECT  2.16 126.225 96.12 126.495 ;
     RECT  2.16 126.765 96.12 127.035 ;
     RECT  2.16 127.305 96.12 127.44 ;
     RECT  2.16 127.44 41.148 127.575 ;
     RECT  77.22 127.44 96.12 127.575 ;
     RECT  2.16 127.845 41.148 128.115 ;
     RECT  77.22 127.845 96.12 128.115 ;
     RECT  2.16 128.385 41.148 128.655 ;
     RECT  77.22 128.385 96.12 128.655 ;
     RECT  2.16 128.925 41.148 129.195 ;
     RECT  77.22 128.925 96.12 129.195 ;
     RECT  2.16 129.465 41.148 129.735 ;
     RECT  77.22 129.465 96.12 129.735 ;
     RECT  2.16 130.005 41.148 130.275 ;
     RECT  77.22 130.005 96.12 130.275 ;
     RECT  2.16 130.545 41.148 130.815 ;
     RECT  77.22 130.545 96.12 130.815 ;
     RECT  2.16 131.085 41.148 131.355 ;
     RECT  77.22 131.085 96.12 131.355 ;
     RECT  2.16 131.625 41.148 131.895 ;
     RECT  77.22 131.625 96.12 131.895 ;
     RECT  2.16 132.165 41.148 132.435 ;
     RECT  77.22 132.165 96.12 132.435 ;
     RECT  2.16 132.705 41.148 132.975 ;
     RECT  77.22 132.705 96.12 132.975 ;
     RECT  2.16 133.245 41.148 133.515 ;
     RECT  77.22 133.245 96.12 133.515 ;
     RECT  2.16 133.785 41.148 134.055 ;
     RECT  77.22 133.785 96.12 134.055 ;
     RECT  2.16 134.325 41.148 134.595 ;
     RECT  77.22 134.325 96.12 134.595 ;
     RECT  2.16 134.865 41.148 135.135 ;
     RECT  77.22 134.865 96.12 135.135 ;
     RECT  2.16 135.405 41.148 135.675 ;
     RECT  77.22 135.405 96.12 135.675 ;
     RECT  2.16 135.945 41.148 136.215 ;
     RECT  77.22 135.945 96.12 136.215 ;
     RECT  2.16 136.485 41.148 136.755 ;
     RECT  77.22 136.485 96.12 136.755 ;
     RECT  2.16 137.025 41.148 137.295 ;
     RECT  77.22 137.025 96.12 137.295 ;
     RECT  2.16 137.565 41.148 137.835 ;
     RECT  77.22 137.565 96.12 137.835 ;
     RECT  2.16 138.105 41.148 138.375 ;
     RECT  77.22 138.105 96.12 138.375 ;
     RECT  2.16 138.645 41.148 138.915 ;
     RECT  77.22 138.645 96.12 138.915 ;
     RECT  2.16 139.185 41.148 139.455 ;
     RECT  77.22 139.185 96.12 139.455 ;
     RECT  2.16 139.725 41.148 139.995 ;
     RECT  77.22 139.725 96.12 139.995 ;
     RECT  2.16 140.265 41.148 140.535 ;
     RECT  77.22 140.265 96.12 140.535 ;
     RECT  2.16 140.805 41.148 141.075 ;
     RECT  77.22 140.805 96.12 141.075 ;
     RECT  2.16 141.345 41.148 141.615 ;
     RECT  77.22 141.345 96.12 141.615 ;
     RECT  2.16 141.885 41.148 142.155 ;
     RECT  77.22 141.885 96.12 142.155 ;
     RECT  2.16 142.425 41.148 142.695 ;
     RECT  77.22 142.425 96.12 142.695 ;
     RECT  2.16 142.965 41.148 143.235 ;
     RECT  77.22 142.965 96.12 143.235 ;
     RECT  2.16 143.505 41.148 143.775 ;
     RECT  77.22 143.505 96.12 143.775 ;
     RECT  2.16 144.045 41.148 144.315 ;
     RECT  77.22 144.045 96.12 144.315 ;
     RECT  2.16 144.585 41.148 144.855 ;
     RECT  77.22 144.585 96.12 144.855 ;
     RECT  2.16 145.125 41.148 145.395 ;
     RECT  77.22 145.125 96.12 145.395 ;
     RECT  2.16 145.665 41.148 145.935 ;
     RECT  77.22 145.665 96.12 145.935 ;
     RECT  2.16 146.205 41.148 146.475 ;
     RECT  77.22 146.205 96.12 146.475 ;
     RECT  2.16 146.745 41.148 147.015 ;
     RECT  77.22 146.745 96.12 147.015 ;
     RECT  2.16 147.285 41.148 147.555 ;
     RECT  77.22 147.285 96.12 147.555 ;
     RECT  2.16 147.825 41.148 148.095 ;
     RECT  77.22 147.825 96.12 148.095 ;
     RECT  2.16 148.365 41.148 148.635 ;
     RECT  77.22 148.365 96.12 148.635 ;
     RECT  2.16 148.905 41.148 149.04 ;
     RECT  77.22 148.905 96.12 149.04 ;
     RECT  2.16 149.04 96.12 149.175 ;
     RECT  2.16 149.445 96.12 149.715 ;
     RECT  2.16 149.985 96.12 150.255 ;
     RECT  2.16 150.525 96.12 150.795 ;
     RECT  2.16 151.065 96.12 151.335 ;
     RECT  2.16 151.605 96.12 151.875 ;
     RECT  2.16 152.145 96.12 152.415 ;
     RECT  2.16 152.685 96.12 152.955 ;
     RECT  2.16 153.225 96.12 153.495 ;
     RECT  2.16 153.765 96.12 154.035 ;
     RECT  2.16 154.305 96.12 154.575 ;
     RECT  2.16 154.845 96.12 155.115 ;
     RECT  2.16 155.385 96.12 155.655 ;
     RECT  2.16 155.925 96.12 156.195 ;
     RECT  2.16 156.465 96.12 156.735 ;
     RECT  2.16 157.005 96.12 157.275 ;
     RECT  2.16 157.545 96.12 157.815 ;
     RECT  2.16 158.085 96.12 158.355 ;
     RECT  2.16 158.625 96.12 158.895 ;
     RECT  2.16 159.165 96.12 159.435 ;
     RECT  2.16 159.705 96.12 159.975 ;
     RECT  2.16 160.245 96.12 160.515 ;
     RECT  2.16 160.785 96.12 161.055 ;
     RECT  2.16 161.325 96.12 161.595 ;
     RECT  2.16 161.865 96.12 162.135 ;
     RECT  2.16 162.405 96.12 162.675 ;
     RECT  2.16 162.945 96.12 163.215 ;
     RECT  2.16 163.485 96.12 163.755 ;
     RECT  2.16 164.025 96.12 164.295 ;
     RECT  2.16 164.565 96.12 164.835 ;
     RECT  2.16 165.105 96.12 165.375 ;
     RECT  2.16 165.645 96.12 165.915 ;
     RECT  2.16 166.185 96.12 166.455 ;
     RECT  2.16 166.725 96.12 166.995 ;
     RECT  2.16 167.265 96.12 167.535 ;
     RECT  2.16 167.805 96.12 168.075 ;
     RECT  2.16 168.345 96.12 168.48 ;
    LAYER RVTP ;
     RECT  2.16 2.295 96.12 2.565 ;
     RECT  2.16 2.835 96.12 3.105 ;
     RECT  2.16 3.375 96.12 3.645 ;
     RECT  2.16 3.915 96.12 4.185 ;
     RECT  2.16 4.455 96.12 4.725 ;
     RECT  2.16 4.995 96.12 5.265 ;
     RECT  2.16 5.535 96.12 5.805 ;
     RECT  2.16 6.075 96.12 6.345 ;
     RECT  2.16 6.615 96.12 6.885 ;
     RECT  2.16 7.155 96.12 7.425 ;
     RECT  2.16 7.695 96.12 7.965 ;
     RECT  2.16 8.235 96.12 8.505 ;
     RECT  2.16 8.775 96.12 9.045 ;
     RECT  2.16 9.315 96.12 9.585 ;
     RECT  2.16 9.855 96.12 10.125 ;
     RECT  2.16 10.395 96.12 10.665 ;
     RECT  2.16 10.935 96.12 11.205 ;
     RECT  2.16 11.475 96.12 11.745 ;
     RECT  2.16 12.015 96.12 12.285 ;
     RECT  2.16 12.555 96.12 12.825 ;
     RECT  2.16 13.095 96.12 13.365 ;
     RECT  2.16 13.635 96.12 13.905 ;
     RECT  2.16 14.175 96.12 14.445 ;
     RECT  2.16 14.715 96.12 14.985 ;
     RECT  2.16 15.255 96.12 15.525 ;
     RECT  2.16 15.795 96.12 16.065 ;
     RECT  2.16 16.335 96.12 16.605 ;
     RECT  2.16 16.875 96.12 17.145 ;
     RECT  2.16 17.415 96.12 17.685 ;
     RECT  2.16 17.955 96.12 18.225 ;
     RECT  2.16 18.495 96.12 18.765 ;
     RECT  2.16 19.035 96.12 19.305 ;
     RECT  2.16 19.575 96.12 19.845 ;
     RECT  2.16 20.115 96.12 20.385 ;
     RECT  2.16 20.655 96.12 20.925 ;
     RECT  2.16 21.195 96.12 21.465 ;
     RECT  2.16 21.735 96.12 22.005 ;
     RECT  2.16 22.275 96.12 22.545 ;
     RECT  2.16 22.815 96.12 23.085 ;
     RECT  2.16 23.355 96.12 23.625 ;
     RECT  2.16 23.895 96.12 24.165 ;
     RECT  2.16 24.435 96.12 24.705 ;
     RECT  2.16 24.975 96.12 25.245 ;
     RECT  2.16 25.515 96.12 25.785 ;
     RECT  2.16 26.055 96.12 26.325 ;
     RECT  2.16 26.595 96.12 26.865 ;
     RECT  2.16 27.135 96.12 27.405 ;
     RECT  2.16 27.675 96.12 27.945 ;
     RECT  2.16 28.215 96.12 28.485 ;
     RECT  2.16 28.755 96.12 29.025 ;
     RECT  2.16 29.295 96.12 29.565 ;
     RECT  2.16 29.835 96.12 30.105 ;
     RECT  2.16 30.375 96.12 30.645 ;
     RECT  2.16 30.915 96.12 31.185 ;
     RECT  2.16 31.455 96.12 31.725 ;
     RECT  2.16 31.995 96.12 32.265 ;
     RECT  2.16 32.535 96.12 32.805 ;
     RECT  2.16 33.075 96.12 33.345 ;
     RECT  2.16 33.615 96.12 33.885 ;
     RECT  2.16 34.155 96.12 34.425 ;
     RECT  2.16 34.695 96.12 34.965 ;
     RECT  2.16 35.235 96.12 35.505 ;
     RECT  2.16 35.775 96.12 36.045 ;
     RECT  2.16 36.315 96.12 36.585 ;
     RECT  2.16 36.855 96.12 37.125 ;
     RECT  2.16 37.395 96.12 37.665 ;
     RECT  2.16 37.935 96.12 38.205 ;
     RECT  2.16 38.475 96.12 38.745 ;
     RECT  2.16 39.015 96.12 39.285 ;
     RECT  2.16 39.555 96.12 39.825 ;
     RECT  2.16 40.095 96.12 40.365 ;
     RECT  2.16 40.635 96.12 40.905 ;
     RECT  2.16 41.175 41.148 41.445 ;
     RECT  77.22 41.175 96.12 41.445 ;
     RECT  2.16 41.715 41.148 41.985 ;
     RECT  77.22 41.715 96.12 41.985 ;
     RECT  2.16 42.255 41.148 42.525 ;
     RECT  77.22 42.255 96.12 42.525 ;
     RECT  2.16 42.795 41.148 43.065 ;
     RECT  77.22 42.795 96.12 43.065 ;
     RECT  2.16 43.335 41.148 43.605 ;
     RECT  77.22 43.335 96.12 43.605 ;
     RECT  2.16 43.875 41.148 44.145 ;
     RECT  77.22 43.875 96.12 44.145 ;
     RECT  2.16 44.415 41.148 44.685 ;
     RECT  77.22 44.415 96.12 44.685 ;
     RECT  2.16 44.955 41.148 45.225 ;
     RECT  77.22 44.955 96.12 45.225 ;
     RECT  2.16 45.495 41.148 45.765 ;
     RECT  77.22 45.495 96.12 45.765 ;
     RECT  2.16 46.035 41.148 46.305 ;
     RECT  77.22 46.035 96.12 46.305 ;
     RECT  2.16 46.575 41.148 46.845 ;
     RECT  77.22 46.575 96.12 46.845 ;
     RECT  2.16 47.115 41.148 47.385 ;
     RECT  77.22 47.115 96.12 47.385 ;
     RECT  2.16 47.655 41.148 47.925 ;
     RECT  77.22 47.655 96.12 47.925 ;
     RECT  2.16 48.195 41.148 48.465 ;
     RECT  77.22 48.195 96.12 48.465 ;
     RECT  2.16 48.735 41.148 49.005 ;
     RECT  77.22 48.735 96.12 49.005 ;
     RECT  2.16 49.275 41.148 49.545 ;
     RECT  77.22 49.275 96.12 49.545 ;
     RECT  2.16 49.815 41.148 50.085 ;
     RECT  77.22 49.815 96.12 50.085 ;
     RECT  2.16 50.355 41.148 50.625 ;
     RECT  77.22 50.355 96.12 50.625 ;
     RECT  2.16 50.895 41.148 51.165 ;
     RECT  77.22 50.895 96.12 51.165 ;
     RECT  2.16 51.435 41.148 51.705 ;
     RECT  77.22 51.435 96.12 51.705 ;
     RECT  2.16 51.975 41.148 52.245 ;
     RECT  77.22 51.975 96.12 52.245 ;
     RECT  2.16 52.515 41.148 52.785 ;
     RECT  77.22 52.515 96.12 52.785 ;
     RECT  2.16 53.055 41.148 53.325 ;
     RECT  77.22 53.055 96.12 53.325 ;
     RECT  2.16 53.595 41.148 53.865 ;
     RECT  77.22 53.595 96.12 53.865 ;
     RECT  2.16 54.135 41.148 54.405 ;
     RECT  77.22 54.135 96.12 54.405 ;
     RECT  2.16 54.675 41.148 54.945 ;
     RECT  77.22 54.675 96.12 54.945 ;
     RECT  2.16 55.215 41.148 55.485 ;
     RECT  77.22 55.215 96.12 55.485 ;
     RECT  2.16 55.755 41.148 56.025 ;
     RECT  77.22 55.755 96.12 56.025 ;
     RECT  2.16 56.295 41.148 56.565 ;
     RECT  77.22 56.295 96.12 56.565 ;
     RECT  2.16 56.835 41.148 57.105 ;
     RECT  77.22 56.835 96.12 57.105 ;
     RECT  2.16 57.375 41.148 57.645 ;
     RECT  77.22 57.375 96.12 57.645 ;
     RECT  2.16 57.915 41.148 58.185 ;
     RECT  77.22 57.915 96.12 58.185 ;
     RECT  2.16 58.455 41.148 58.725 ;
     RECT  77.22 58.455 96.12 58.725 ;
     RECT  2.16 58.995 41.148 59.265 ;
     RECT  77.22 58.995 96.12 59.265 ;
     RECT  2.16 59.535 41.148 59.805 ;
     RECT  77.22 59.535 96.12 59.805 ;
     RECT  2.16 60.075 41.148 60.345 ;
     RECT  77.22 60.075 96.12 60.345 ;
     RECT  2.16 60.615 41.148 60.885 ;
     RECT  77.22 60.615 96.12 60.885 ;
     RECT  2.16 61.155 41.148 61.425 ;
     RECT  77.22 61.155 96.12 61.425 ;
     RECT  2.16 61.695 41.148 61.965 ;
     RECT  77.22 61.695 96.12 61.965 ;
     RECT  2.16 62.235 41.148 62.505 ;
     RECT  77.22 62.235 96.12 62.505 ;
     RECT  2.16 62.775 96.12 63.045 ;
     RECT  2.16 63.315 96.12 63.585 ;
     RECT  2.16 63.855 96.12 64.125 ;
     RECT  2.16 64.395 96.12 64.665 ;
     RECT  2.16 64.935 96.12 65.205 ;
     RECT  2.16 65.475 96.12 65.745 ;
     RECT  2.16 66.015 96.12 66.285 ;
     RECT  2.16 66.555 96.12 66.825 ;
     RECT  2.16 67.095 96.12 67.365 ;
     RECT  2.16 67.635 96.12 67.905 ;
     RECT  2.16 68.175 96.12 68.445 ;
     RECT  2.16 68.715 96.12 68.985 ;
     RECT  2.16 69.255 96.12 69.525 ;
     RECT  2.16 69.795 96.12 70.065 ;
     RECT  2.16 70.335 96.12 70.605 ;
     RECT  2.16 70.875 96.12 71.145 ;
     RECT  2.16 71.415 96.12 71.685 ;
     RECT  2.16 71.955 96.12 72.225 ;
     RECT  2.16 72.495 96.12 72.765 ;
     RECT  2.16 73.035 96.12 73.305 ;
     RECT  2.16 73.575 96.12 73.845 ;
     RECT  2.16 74.115 96.12 74.385 ;
     RECT  2.16 74.655 96.12 74.925 ;
     RECT  2.16 75.195 96.12 75.465 ;
     RECT  2.16 75.735 96.12 76.005 ;
     RECT  2.16 76.275 96.12 76.545 ;
     RECT  2.16 76.815 96.12 77.085 ;
     RECT  2.16 77.355 96.12 77.625 ;
     RECT  2.16 77.895 96.12 78.165 ;
     RECT  2.16 78.435 96.12 78.705 ;
     RECT  2.16 78.975 96.12 79.245 ;
     RECT  2.16 79.515 96.12 79.785 ;
     RECT  2.16 80.055 96.12 80.325 ;
     RECT  2.16 80.595 96.12 80.865 ;
     RECT  2.16 81.135 96.12 81.405 ;
     RECT  2.16 81.675 96.12 81.945 ;
     RECT  2.16 82.215 96.12 82.485 ;
     RECT  2.16 82.755 96.12 83.025 ;
     RECT  2.16 83.295 96.12 83.565 ;
     RECT  2.16 83.835 96.12 84.105 ;
     RECT  2.16 84.375 41.148 84.645 ;
     RECT  77.22 84.375 96.12 84.645 ;
     RECT  2.16 84.915 41.148 85.185 ;
     RECT  77.22 84.915 96.12 85.185 ;
     RECT  2.16 85.455 41.148 85.725 ;
     RECT  77.22 85.455 96.12 85.725 ;
     RECT  2.16 85.995 41.148 86.265 ;
     RECT  77.22 85.995 96.12 86.265 ;
     RECT  2.16 86.535 41.148 86.805 ;
     RECT  77.22 86.535 96.12 86.805 ;
     RECT  2.16 87.075 41.148 87.345 ;
     RECT  77.22 87.075 96.12 87.345 ;
     RECT  2.16 87.615 41.148 87.885 ;
     RECT  77.22 87.615 96.12 87.885 ;
     RECT  2.16 88.155 41.148 88.425 ;
     RECT  77.22 88.155 96.12 88.425 ;
     RECT  2.16 88.695 41.148 88.965 ;
     RECT  77.22 88.695 96.12 88.965 ;
     RECT  2.16 89.235 41.148 89.505 ;
     RECT  77.22 89.235 96.12 89.505 ;
     RECT  2.16 89.775 41.148 90.045 ;
     RECT  77.22 89.775 96.12 90.045 ;
     RECT  2.16 90.315 41.148 90.585 ;
     RECT  77.22 90.315 96.12 90.585 ;
     RECT  2.16 90.855 41.148 91.125 ;
     RECT  77.22 90.855 96.12 91.125 ;
     RECT  2.16 91.395 41.148 91.665 ;
     RECT  77.22 91.395 96.12 91.665 ;
     RECT  2.16 91.935 41.148 92.205 ;
     RECT  77.22 91.935 96.12 92.205 ;
     RECT  2.16 92.475 41.148 92.745 ;
     RECT  77.22 92.475 96.12 92.745 ;
     RECT  2.16 93.015 41.148 93.285 ;
     RECT  77.22 93.015 96.12 93.285 ;
     RECT  2.16 93.555 41.148 93.825 ;
     RECT  77.22 93.555 96.12 93.825 ;
     RECT  2.16 94.095 41.148 94.365 ;
     RECT  77.22 94.095 96.12 94.365 ;
     RECT  2.16 94.635 41.148 94.905 ;
     RECT  77.22 94.635 96.12 94.905 ;
     RECT  2.16 95.175 41.148 95.445 ;
     RECT  77.22 95.175 96.12 95.445 ;
     RECT  2.16 95.715 41.148 95.985 ;
     RECT  77.22 95.715 96.12 95.985 ;
     RECT  2.16 96.255 41.148 96.525 ;
     RECT  77.22 96.255 96.12 96.525 ;
     RECT  2.16 96.795 41.148 97.065 ;
     RECT  77.22 96.795 96.12 97.065 ;
     RECT  2.16 97.335 41.148 97.605 ;
     RECT  77.22 97.335 96.12 97.605 ;
     RECT  2.16 97.875 41.148 98.145 ;
     RECT  77.22 97.875 96.12 98.145 ;
     RECT  2.16 98.415 41.148 98.685 ;
     RECT  77.22 98.415 96.12 98.685 ;
     RECT  2.16 98.955 41.148 99.225 ;
     RECT  77.22 98.955 96.12 99.225 ;
     RECT  2.16 99.495 41.148 99.765 ;
     RECT  77.22 99.495 96.12 99.765 ;
     RECT  2.16 100.035 41.148 100.305 ;
     RECT  77.22 100.035 96.12 100.305 ;
     RECT  2.16 100.575 41.148 100.845 ;
     RECT  77.22 100.575 96.12 100.845 ;
     RECT  2.16 101.115 41.148 101.385 ;
     RECT  77.22 101.115 96.12 101.385 ;
     RECT  2.16 101.655 41.148 101.925 ;
     RECT  77.22 101.655 96.12 101.925 ;
     RECT  2.16 102.195 41.148 102.465 ;
     RECT  77.22 102.195 96.12 102.465 ;
     RECT  2.16 102.735 41.148 103.005 ;
     RECT  77.22 102.735 96.12 103.005 ;
     RECT  2.16 103.275 41.148 103.545 ;
     RECT  77.22 103.275 96.12 103.545 ;
     RECT  2.16 103.815 41.148 104.085 ;
     RECT  77.22 103.815 96.12 104.085 ;
     RECT  2.16 104.355 41.148 104.625 ;
     RECT  77.22 104.355 96.12 104.625 ;
     RECT  2.16 104.895 41.148 105.165 ;
     RECT  77.22 104.895 96.12 105.165 ;
     RECT  2.16 105.435 41.148 105.705 ;
     RECT  77.22 105.435 96.12 105.705 ;
     RECT  2.16 105.975 96.12 106.245 ;
     RECT  2.16 106.515 96.12 106.785 ;
     RECT  2.16 107.055 96.12 107.325 ;
     RECT  2.16 107.595 96.12 107.865 ;
     RECT  2.16 108.135 96.12 108.405 ;
     RECT  2.16 108.675 96.12 108.945 ;
     RECT  2.16 109.215 96.12 109.485 ;
     RECT  2.16 109.755 96.12 110.025 ;
     RECT  2.16 110.295 96.12 110.565 ;
     RECT  2.16 110.835 96.12 111.105 ;
     RECT  2.16 111.375 96.12 111.645 ;
     RECT  2.16 111.915 96.12 112.185 ;
     RECT  2.16 112.455 96.12 112.725 ;
     RECT  2.16 112.995 96.12 113.265 ;
     RECT  2.16 113.535 96.12 113.805 ;
     RECT  2.16 114.075 96.12 114.345 ;
     RECT  2.16 114.615 96.12 114.885 ;
     RECT  2.16 115.155 96.12 115.425 ;
     RECT  2.16 115.695 96.12 115.965 ;
     RECT  2.16 116.235 96.12 116.505 ;
     RECT  2.16 116.775 96.12 117.045 ;
     RECT  2.16 117.315 96.12 117.585 ;
     RECT  2.16 117.855 96.12 118.125 ;
     RECT  2.16 118.395 96.12 118.665 ;
     RECT  2.16 118.935 96.12 119.205 ;
     RECT  2.16 119.475 96.12 119.745 ;
     RECT  2.16 120.015 96.12 120.285 ;
     RECT  2.16 120.555 96.12 120.825 ;
     RECT  2.16 121.095 96.12 121.365 ;
     RECT  2.16 121.635 96.12 121.905 ;
     RECT  2.16 122.175 96.12 122.445 ;
     RECT  2.16 122.715 96.12 122.985 ;
     RECT  2.16 123.255 96.12 123.525 ;
     RECT  2.16 123.795 96.12 124.065 ;
     RECT  2.16 124.335 96.12 124.605 ;
     RECT  2.16 124.875 96.12 125.145 ;
     RECT  2.16 125.415 96.12 125.685 ;
     RECT  2.16 125.955 96.12 126.225 ;
     RECT  2.16 126.495 96.12 126.765 ;
     RECT  2.16 127.035 96.12 127.305 ;
     RECT  2.16 127.575 41.148 127.845 ;
     RECT  77.22 127.575 96.12 127.845 ;
     RECT  2.16 128.115 41.148 128.385 ;
     RECT  77.22 128.115 96.12 128.385 ;
     RECT  2.16 128.655 41.148 128.925 ;
     RECT  77.22 128.655 96.12 128.925 ;
     RECT  2.16 129.195 41.148 129.465 ;
     RECT  77.22 129.195 96.12 129.465 ;
     RECT  2.16 129.735 41.148 130.005 ;
     RECT  77.22 129.735 96.12 130.005 ;
     RECT  2.16 130.275 41.148 130.545 ;
     RECT  77.22 130.275 96.12 130.545 ;
     RECT  2.16 130.815 41.148 131.085 ;
     RECT  77.22 130.815 96.12 131.085 ;
     RECT  2.16 131.355 41.148 131.625 ;
     RECT  77.22 131.355 96.12 131.625 ;
     RECT  2.16 131.895 41.148 132.165 ;
     RECT  77.22 131.895 96.12 132.165 ;
     RECT  2.16 132.435 41.148 132.705 ;
     RECT  77.22 132.435 96.12 132.705 ;
     RECT  2.16 132.975 41.148 133.245 ;
     RECT  77.22 132.975 96.12 133.245 ;
     RECT  2.16 133.515 41.148 133.785 ;
     RECT  77.22 133.515 96.12 133.785 ;
     RECT  2.16 134.055 41.148 134.325 ;
     RECT  77.22 134.055 96.12 134.325 ;
     RECT  2.16 134.595 41.148 134.865 ;
     RECT  77.22 134.595 96.12 134.865 ;
     RECT  2.16 135.135 41.148 135.405 ;
     RECT  77.22 135.135 96.12 135.405 ;
     RECT  2.16 135.675 41.148 135.945 ;
     RECT  77.22 135.675 96.12 135.945 ;
     RECT  2.16 136.215 41.148 136.485 ;
     RECT  77.22 136.215 96.12 136.485 ;
     RECT  2.16 136.755 41.148 137.025 ;
     RECT  77.22 136.755 96.12 137.025 ;
     RECT  2.16 137.295 41.148 137.565 ;
     RECT  77.22 137.295 96.12 137.565 ;
     RECT  2.16 137.835 41.148 138.105 ;
     RECT  77.22 137.835 96.12 138.105 ;
     RECT  2.16 138.375 41.148 138.645 ;
     RECT  77.22 138.375 96.12 138.645 ;
     RECT  2.16 138.915 41.148 139.185 ;
     RECT  77.22 138.915 96.12 139.185 ;
     RECT  2.16 139.455 41.148 139.725 ;
     RECT  77.22 139.455 96.12 139.725 ;
     RECT  2.16 139.995 41.148 140.265 ;
     RECT  77.22 139.995 96.12 140.265 ;
     RECT  2.16 140.535 41.148 140.805 ;
     RECT  77.22 140.535 96.12 140.805 ;
     RECT  2.16 141.075 41.148 141.345 ;
     RECT  77.22 141.075 96.12 141.345 ;
     RECT  2.16 141.615 41.148 141.885 ;
     RECT  77.22 141.615 96.12 141.885 ;
     RECT  2.16 142.155 41.148 142.425 ;
     RECT  77.22 142.155 96.12 142.425 ;
     RECT  2.16 142.695 41.148 142.965 ;
     RECT  77.22 142.695 96.12 142.965 ;
     RECT  2.16 143.235 41.148 143.505 ;
     RECT  77.22 143.235 96.12 143.505 ;
     RECT  2.16 143.775 41.148 144.045 ;
     RECT  77.22 143.775 96.12 144.045 ;
     RECT  2.16 144.315 41.148 144.585 ;
     RECT  77.22 144.315 96.12 144.585 ;
     RECT  2.16 144.855 41.148 145.125 ;
     RECT  77.22 144.855 96.12 145.125 ;
     RECT  2.16 145.395 41.148 145.665 ;
     RECT  77.22 145.395 96.12 145.665 ;
     RECT  2.16 145.935 41.148 146.205 ;
     RECT  77.22 145.935 96.12 146.205 ;
     RECT  2.16 146.475 41.148 146.745 ;
     RECT  77.22 146.475 96.12 146.745 ;
     RECT  2.16 147.015 41.148 147.285 ;
     RECT  77.22 147.015 96.12 147.285 ;
     RECT  2.16 147.555 41.148 147.825 ;
     RECT  77.22 147.555 96.12 147.825 ;
     RECT  2.16 148.095 41.148 148.365 ;
     RECT  77.22 148.095 96.12 148.365 ;
     RECT  2.16 148.635 41.148 148.905 ;
     RECT  77.22 148.635 96.12 148.905 ;
     RECT  2.16 149.175 96.12 149.445 ;
     RECT  2.16 149.715 96.12 149.985 ;
     RECT  2.16 150.255 96.12 150.525 ;
     RECT  2.16 150.795 96.12 151.065 ;
     RECT  2.16 151.335 96.12 151.605 ;
     RECT  2.16 151.875 96.12 152.145 ;
     RECT  2.16 152.415 96.12 152.685 ;
     RECT  2.16 152.955 96.12 153.225 ;
     RECT  2.16 153.495 96.12 153.765 ;
     RECT  2.16 154.035 96.12 154.305 ;
     RECT  2.16 154.575 96.12 154.845 ;
     RECT  2.16 155.115 96.12 155.385 ;
     RECT  2.16 155.655 96.12 155.925 ;
     RECT  2.16 156.195 96.12 156.465 ;
     RECT  2.16 156.735 96.12 157.005 ;
     RECT  2.16 157.275 96.12 157.545 ;
     RECT  2.16 157.815 96.12 158.085 ;
     RECT  2.16 158.355 96.12 158.625 ;
     RECT  2.16 158.895 96.12 159.165 ;
     RECT  2.16 159.435 96.12 159.705 ;
     RECT  2.16 159.975 96.12 160.245 ;
     RECT  2.16 160.515 96.12 160.785 ;
     RECT  2.16 161.055 96.12 161.325 ;
     RECT  2.16 161.595 96.12 161.865 ;
     RECT  2.16 162.135 96.12 162.405 ;
     RECT  2.16 162.675 96.12 162.945 ;
     RECT  2.16 163.215 96.12 163.485 ;
     RECT  2.16 163.755 96.12 164.025 ;
     RECT  2.16 164.295 96.12 164.565 ;
     RECT  2.16 164.835 96.12 165.105 ;
     RECT  2.16 165.375 96.12 165.645 ;
     RECT  2.16 165.915 96.12 166.185 ;
     RECT  2.16 166.455 96.12 166.725 ;
     RECT  2.16 166.995 96.12 167.265 ;
     RECT  2.16 167.535 96.12 167.805 ;
     RECT  2.16 168.075 96.12 168.345 ;
    LAYER M1 ;
     RECT  2.16 2.151 96.12 41.049 ;
     RECT  43.2 43.2 75.192 60.504 ;
     RECT  2.16 41.049 41.148 62.631 ;
     RECT  77.22 41.049 96.12 62.631 ;
     RECT  2.16 62.631 96.12 84.249 ;
     RECT  43.2 86.4 75.192 103.704 ;
     RECT  2.16 84.249 41.148 105.831 ;
     RECT  77.22 84.249 96.12 105.831 ;
     RECT  2.16 105.831 96.12 127.449 ;
     RECT  43.2 129.6 75.192 146.904 ;
     RECT  2.16 127.449 41.148 149.031 ;
     RECT  77.22 127.449 96.12 149.031 ;
     RECT  2.16 149.031 96.12 168.489 ;
    LAYER M2 ;
     RECT  0.103 32.346 0.139 33.606 ;
     RECT  0.103 118.206 0.139 118.224 ;
     RECT  0.103 74.736 0.175 74.754 ;
     RECT  0.175 74.628 0.203 74.754 ;
     RECT  0.103 76.086 0.211 76.806 ;
     RECT  0.211 76.086 0.239 76.914 ;
     RECT  0.203 74.628 0.275 74.646 ;
     RECT  0.239 76.896 0.311 76.914 ;
     RECT  0.103 85.536 0.535 85.554 ;
     RECT  0.103 87.156 2.047 88.254 ;
     RECT  0.139 31.806 2.16 33.606 ;
     RECT  0.103 35.316 2.16 35.874 ;
     RECT  0.103 42.426 2.16 42.444 ;
     RECT  0.103 43.308 2.16 44.784 ;
     RECT  1.723 74.628 2.16 74.646 ;
     RECT  0.239 76.086 2.16 76.104 ;
     RECT  0.535 77.166 2.16 77.184 ;
     RECT  0.103 77.976 2.16 78.534 ;
     RECT  0.535 84.726 2.16 84.744 ;
     RECT  0.535 85.536 2.16 85.824 ;
     RECT  2.047 87.156 2.16 88.794 ;
     RECT  0.139 118.026 2.16 118.224 ;
     RECT  0.103 119.556 2.16 120.114 ;
     RECT  0.103 121.176 2.16 121.194 ;
     RECT  0.103 129.276 2.16 129.834 ;
     RECT  0.103 131.058 2.16 131.652 ;
     RECT  37.831 170.586 37.903 170.604 ;
     RECT  37.903 170.514 38.219 170.604 ;
     RECT  2.16 2.151 41.148 168.489 ;
     RECT  41.148 105.831 41.171 127.674 ;
     RECT  41.148 87.156 41.207 93.114 ;
     RECT  41.148 128.466 41.207 129.456 ;
     RECT  41.148 59.706 41.351 59.724 ;
     RECT  41.148 132.678 41.351 135.396 ;
     RECT  41.148 143.676 41.351 143.694 ;
     RECT  41.148 45.162 41.387 45.414 ;
     RECT  41.148 47.628 41.387 56.214 ;
     RECT  41.207 128.466 41.387 129.294 ;
     RECT  41.387 55.656 41.423 56.214 ;
     RECT  41.423 55.926 41.459 56.214 ;
     RECT  41.148 97.416 41.459 99.756 ;
     RECT  41.459 97.416 41.531 99.684 ;
     RECT  41.387 47.628 41.603 54.864 ;
     RECT  41.207 92.718 41.603 93.006 ;
     RECT  41.531 97.416 41.603 99.522 ;
     RECT  41.603 47.628 41.639 54.702 ;
     RECT  41.351 132.75 41.639 135.396 ;
     RECT  41.639 47.7 41.711 54.702 ;
     RECT  41.603 92.952 41.711 93.006 ;
     RECT  41.711 47.7 41.747 48.564 ;
     RECT  41.603 99.504 41.819 99.522 ;
     RECT  41.148 130.32 41.819 131.076 ;
     RECT  41.711 49.788 41.891 54.702 ;
     RECT  41.603 97.416 41.891 98.604 ;
     RECT  41.387 128.664 41.891 129.294 ;
     RECT  41.819 130.32 41.927 130.914 ;
     RECT  41.639 132.75 41.963 135.36 ;
     RECT  41.171 105.831 42.079 127.449 ;
     RECT  41.148 139.896 42.107 142.884 ;
     RECT  41.891 49.788 42.143 54.432 ;
     RECT  41.148 93.906 42.143 96.444 ;
     RECT  41.148 136.764 42.143 139.104 ;
     RECT  42.107 140.166 42.143 142.884 ;
     RECT  42.143 49.788 42.179 52.776 ;
     RECT  42.143 136.764 42.179 137.556 ;
     RECT  42.143 138.546 42.179 139.104 ;
     RECT  42.143 140.706 42.179 142.884 ;
     RECT  41.387 45.162 42.215 45.18 ;
     RECT  41.747 47.7 42.215 48.456 ;
     RECT  42.179 49.788 42.215 52.344 ;
     RECT  41.207 87.156 42.215 91.926 ;
     RECT  42.143 93.906 42.215 96.084 ;
     RECT  41.963 132.75 42.215 133.704 ;
     RECT  41.963 134.64 42.215 135.36 ;
     RECT  42.179 136.764 42.215 136.782 ;
     RECT  42.179 137.538 42.215 137.556 ;
     RECT  42.215 47.862 42.251 48.186 ;
     RECT  42.215 50.022 42.251 52.344 ;
     RECT  42.215 89.208 42.251 91.926 ;
     RECT  42.215 134.64 42.251 135.09 ;
     RECT  42.079 105.831 42.259 127.494 ;
     RECT  42.251 48.168 42.287 48.186 ;
     RECT  42.251 134.874 42.287 135.09 ;
     RECT  42.287 134.874 42.323 134.892 ;
     RECT  42.251 50.436 42.467 52.344 ;
     RECT  42.215 94.914 42.467 96.084 ;
     RECT  42.215 132.75 42.467 133.344 ;
     RECT  42.179 138.996 42.467 139.104 ;
     RECT  41.148 60.552 42.619 61.65 ;
     RECT  41.148 62.631 42.619 84.249 ;
     RECT  41.148 103.752 42.691 104.922 ;
     RECT  42.259 105.831 42.691 127.53 ;
     RECT  42.619 60.552 42.719 84.249 ;
     RECT  41.891 128.736 42.727 129.294 ;
     RECT  41.891 98.046 42.979 98.604 ;
     RECT  42.179 140.976 42.979 142.254 ;
     RECT  41.148 149.031 43.051 168.489 ;
     RECT  43.051 148.986 43.087 168.489 ;
     RECT  41.148 43.146 43.2 43.164 ;
     RECT  42.467 50.436 43.2 52.272 ;
     RECT  42.143 53.766 43.2 54.432 ;
     RECT  41.459 55.926 43.2 55.944 ;
     RECT  41.148 57.276 43.2 57.294 ;
     RECT  42.719 60.552 43.2 61.65 ;
     RECT  42.215 87.156 43.2 88.344 ;
     RECT  42.251 89.856 43.2 89.874 ;
     RECT  42.251 90.864 43.2 91.926 ;
     RECT  41.711 92.988 43.2 93.006 ;
     RECT  42.215 93.906 43.2 93.924 ;
     RECT  42.467 94.914 43.2 95.364 ;
     RECT  42.979 98.046 43.2 98.712 ;
     RECT  42.691 103.752 43.2 127.53 ;
     RECT  42.727 128.736 43.2 129.564 ;
     RECT  41.927 130.32 43.2 130.536 ;
     RECT  42.467 132.75 43.2 132.768 ;
     RECT  43.051 134.496 43.2 134.514 ;
     RECT  42.467 139.086 43.2 139.104 ;
     RECT  42.979 140.976 43.2 142.488 ;
     RECT  41.148 147.06 43.2 147.924 ;
     RECT  43.2 86.4 43.259 127.53 ;
     RECT  43.259 86.4 43.367 127.494 ;
     RECT  43.2 128.736 49.747 147.924 ;
     RECT  43.087 148.878 49.747 168.489 ;
     RECT  42.719 62.514 50.783 84.249 ;
     RECT  43.2 43.146 72.967 61.65 ;
     RECT  50.783 62.586 74.947 84.249 ;
     RECT  43.367 86.4 75.127 127.449 ;
     RECT  72.967 43.074 75.192 61.65 ;
     RECT  75.127 86.076 75.192 127.449 ;
     RECT  49.747 128.736 75.192 168.489 ;
     RECT  41.148 2.151 75.271 41.049 ;
     RECT  74.947 62.586 75.271 84.294 ;
     RECT  75.192 91.296 75.335 91.314 ;
     RECT  75.192 139.194 75.335 140.184 ;
     RECT  75.192 142.506 75.335 142.524 ;
     RECT  75.271 2.151 75.371 41.13 ;
     RECT  75.192 52.83 75.371 54.738 ;
     RECT  75.271 62.55 75.371 84.294 ;
     RECT  75.192 86.076 75.371 86.364 ;
     RECT  75.192 146.448 75.371 168.489 ;
     RECT  75.192 58.698 75.407 58.716 ;
     RECT  75.371 86.076 75.407 86.094 ;
     RECT  75.192 132.786 75.407 134.01 ;
     RECT  75.192 103.446 75.487 127.449 ;
     RECT  75.192 43.074 75.551 43.164 ;
     RECT  75.192 44.388 75.551 45.054 ;
     RECT  75.371 62.586 75.587 84.294 ;
     RECT  75.487 103.446 75.659 127.494 ;
     RECT  75.551 44.658 75.767 45.054 ;
     RECT  75.407 132.786 75.911 133.704 ;
     RECT  75.192 96.3 76.063 97.83 ;
     RECT  75.192 98.586 76.063 98.604 ;
     RECT  75.335 139.194 76.063 139.95 ;
     RECT  75.192 141.012 76.063 141.264 ;
     RECT  75.371 52.83 76.099 54.432 ;
     RECT  76.063 96.3 76.099 98.604 ;
     RECT  76.063 139.194 76.099 141.264 ;
     RECT  76.207 89.856 76.307 89.874 ;
     RECT  75.911 132.876 76.315 133.704 ;
     RECT  76.315 48.132 76.351 48.15 ;
     RECT  75.192 48.906 76.351 50.148 ;
     RECT  76.315 91.476 76.351 91.494 ;
     RECT  75.192 94.032 76.351 95.13 ;
     RECT  76.315 132.876 76.351 134.388 ;
     RECT  75.192 136.692 76.351 137.358 ;
     RECT  76.351 48.132 76.387 50.688 ;
     RECT  76.099 52.83 76.387 54.468 ;
     RECT  76.351 91.476 76.387 91.728 ;
     RECT  76.351 93.798 76.387 95.13 ;
     RECT  76.099 96.3 76.387 99.018 ;
     RECT  76.351 132.876 76.387 137.358 ;
     RECT  76.099 139.194 76.387 141.912 ;
     RECT  75.192 101.736 76.639 101.754 ;
     RECT  76.387 132.876 76.639 141.912 ;
     RECT  75.192 130.482 76.675 130.5 ;
     RECT  76.675 130.482 76.711 130.77 ;
     RECT  75.192 46.656 76.927 46.944 ;
     RECT  76.639 132.876 76.963 142.074 ;
     RECT  75.192 128.736 76.999 129.564 ;
     RECT  76.711 130.356 76.999 130.77 ;
     RECT  76.999 128.736 77.215 130.914 ;
     RECT  75.371 2.151 77.22 41.049 ;
     RECT  77.215 42.156 77.22 42.174 ;
     RECT  75.551 43.146 77.22 43.164 ;
     RECT  75.767 45.036 77.22 45.054 ;
     RECT  76.927 46.116 77.22 46.944 ;
     RECT  76.387 48.132 77.22 51.93 ;
     RECT  76.387 52.686 77.22 54.468 ;
     RECT  76.135 55.728 77.22 55.746 ;
     RECT  75.192 60.552 77.22 61.65 ;
     RECT  75.587 62.586 77.22 84.249 ;
     RECT  77.215 85.428 77.22 85.446 ;
     RECT  75.192 87.156 77.22 87.408 ;
     RECT  75.192 88.776 77.22 88.794 ;
     RECT  76.927 90.252 77.22 90.27 ;
     RECT  76.387 91.476 77.22 99.018 ;
     RECT  75.192 100.206 77.22 100.224 ;
     RECT  76.639 101.736 77.22 102.384 ;
     RECT  75.659 103.446 77.22 127.449 ;
     RECT  77.215 128.196 77.22 130.914 ;
     RECT  76.963 132.516 77.22 142.074 ;
     RECT  76.135 145.566 77.22 145.584 ;
     RECT  75.371 147.06 77.22 168.489 ;
     RECT  77.22 2.151 96.12 168.489 ;
     RECT  96.12 38.718 96.323 39.114 ;
     RECT  96.12 81.378 96.323 86.256 ;
     RECT  96.12 125.226 96.323 127.944 ;
     RECT  96.12 40.068 96.359 43.704 ;
     RECT  96.12 52.326 96.359 52.344 ;
     RECT  96.12 54.954 96.359 57.294 ;
     RECT  96.12 96.066 96.359 96.822 ;
     RECT  96.12 99.576 96.359 101.214 ;
     RECT  96.323 39.096 96.935 39.114 ;
     RECT  96.359 40.068 96.935 43.434 ;
     RECT  96.359 54.954 96.935 56.322 ;
     RECT  96.359 57.078 96.935 57.294 ;
     RECT  96.323 81.648 96.935 86.256 ;
     RECT  96.12 97.848 96.935 98.784 ;
     RECT  96.359 99.576 96.935 100.224 ;
     RECT  96.935 41.454 96.971 42.624 ;
     RECT  96.935 57.15 96.971 57.294 ;
     RECT  96.935 83.07 96.971 83.664 ;
     RECT  96.935 40.068 97.007 40.698 ;
     RECT  96.971 83.07 97.007 83.394 ;
     RECT  97.007 40.068 97.475 40.626 ;
     RECT  96.12 53.334 97.475 54.126 ;
     RECT  96.323 126.738 97.475 127.944 ;
     RECT  96.12 139.158 97.475 141.066 ;
     RECT  96.12 141.858 97.475 142.146 ;
     RECT  96.12 142.938 97.475 143.226 ;
     RECT  97.475 40.176 97.511 40.194 ;
     RECT  96.971 41.796 97.511 42.624 ;
     RECT  96.935 43.416 97.511 43.434 ;
     RECT  97.475 53.334 97.511 53.928 ;
     RECT  96.935 54.954 97.511 55.476 ;
     RECT  96.935 56.268 97.511 56.322 ;
     RECT  96.971 57.276 97.511 57.294 ;
     RECT  96.935 81.648 97.511 82.314 ;
     RECT  97.007 83.106 97.511 83.394 ;
     RECT  96.935 84.582 97.511 85.824 ;
     RECT  96.359 96.804 97.511 96.822 ;
     RECT  96.935 97.884 97.511 98.748 ;
     RECT  96.935 99.846 97.511 100.224 ;
     RECT  96.359 101.196 97.511 101.214 ;
     RECT  96.323 125.226 97.511 125.784 ;
     RECT  97.475 127.044 97.511 127.944 ;
     RECT  97.475 139.536 97.511 140.634 ;
     RECT  97.511 82.296 97.547 82.314 ;
     RECT  97.511 84.582 97.547 85.482 ;
     RECT  97.511 127.044 97.547 127.602 ;
     RECT  97.511 56.304 97.583 56.322 ;
     RECT  97.547 85.464 97.583 85.482 ;
     RECT  97.511 83.106 98.195 83.124 ;
     RECT  98.167 98.766 98.267 98.784 ;
    LAYER M3 ;
     RECT  2.415 2.143 2.505 2.413 ;
     RECT  5.115 2.143 5.205 2.413 ;
     RECT  7.815 2.143 7.905 2.413 ;
     RECT  10.515 2.143 10.605 2.413 ;
     RECT  13.215 2.143 13.305 2.413 ;
     RECT  15.915 2.143 16.005 2.413 ;
     RECT  18.615 2.143 18.705 2.413 ;
     RECT  21.315 2.143 21.405 2.413 ;
     RECT  24.015 2.143 24.105 2.413 ;
     RECT  26.715 2.143 26.805 2.413 ;
     RECT  29.415 2.143 29.505 2.413 ;
     RECT  32.115 2.143 32.205 2.413 ;
     RECT  34.815 2.143 34.905 2.413 ;
     RECT  37.515 2.143 37.605 2.413 ;
     RECT  40.215 2.143 40.305 2.413 ;
     RECT  42.915 2.143 43.005 2.413 ;
     RECT  45.615 2.143 45.705 2.413 ;
     RECT  48.315 2.143 48.405 2.413 ;
     RECT  51.015 2.143 51.105 2.413 ;
     RECT  53.715 2.143 53.805 2.413 ;
     RECT  56.415 2.143 56.505 2.413 ;
     RECT  59.115 2.143 59.205 2.413 ;
     RECT  61.815 2.143 61.905 2.413 ;
     RECT  64.515 2.143 64.605 2.413 ;
     RECT  67.215 2.143 67.305 2.413 ;
     RECT  69.915 2.143 70.005 2.413 ;
     RECT  72.615 2.143 72.705 2.413 ;
     RECT  75.315 2.143 75.405 2.413 ;
     RECT  78.015 2.143 78.105 2.413 ;
     RECT  80.715 2.143 80.805 2.413 ;
     RECT  83.415 2.143 83.505 2.413 ;
     RECT  86.115 2.143 86.205 2.413 ;
     RECT  88.815 2.143 88.905 2.413 ;
     RECT  91.515 2.143 91.605 2.413 ;
     RECT  94.215 2.143 94.305 2.413 ;
     RECT  7.815 2.413 8.097 31.729 ;
     RECT  5.115 2.413 5.397 31.765 ;
     RECT  3.528 31.621 3.618 31.801 ;
     RECT  5.115 31.765 5.994 31.801 ;
     RECT  42.915 2.413 43.197 31.801 ;
     RECT  5.04 31.801 5.994 31.919 ;
     RECT  3.528 31.801 3.87 31.963 ;
     RECT  5.04 31.919 5.922 31.963 ;
     RECT  2.415 2.413 2.697 32.059 ;
     RECT  2.415 32.059 2.79 32.071 ;
     RECT  3.528 31.963 5.922 32.071 ;
     RECT  0.144 31.801 0.162 32.251 ;
     RECT  0.108 32.251 0.162 32.299 ;
     RECT  6.732 31.729 8.097 32.341 ;
     RECT  6.732 32.341 8.226 32.737 ;
     RECT  0.108 32.299 0.198 32.827 ;
     RECT  2.415 32.071 5.922 32.845 ;
     RECT  6.732 32.737 8.262 32.845 ;
     RECT  42.264 31.801 43.197 32.881 ;
     RECT  0.108 32.827 0.342 33.005 ;
     RECT  40.215 2.413 40.497 33.007 ;
     RECT  40.215 33.007 41.094 33.043 ;
     RECT  42.012 32.881 43.197 33.043 ;
     RECT  2.415 32.845 8.262 33.151 ;
     RECT  2.415 33.151 8.802 33.269 ;
     RECT  2.415 33.269 8.478 33.403 ;
     RECT  0.108 33.005 0.126 33.611 ;
     RECT  10.515 2.413 10.797 33.889 ;
     RECT  10.515 33.889 10.818 33.989 ;
     RECT  35.928 33.547 35.946 33.989 ;
     RECT  0.144 33.979 0.162 34.109 ;
     RECT  2.304 33.403 8.478 34.123 ;
     RECT  2.304 34.123 8.982 34.259 ;
     RECT  3.456 34.259 8.982 34.349 ;
     RECT  6.768 34.349 8.982 34.619 ;
     RECT  6.84 34.619 8.982 34.771 ;
     RECT  0.144 34.843 0.162 34.973 ;
     RECT  38.772 34.969 38.79 35.195 ;
     RECT  6.84 34.771 9.018 35.303 ;
     RECT  3.456 34.349 5.994 35.311 ;
     RECT  3.42 35.311 5.994 35.509 ;
     RECT  6.84 35.303 8.298 35.509 ;
     RECT  2.304 34.259 2.697 35.563 ;
     RECT  3.42 35.509 8.298 35.563 ;
     RECT  2.304 35.563 8.298 35.597 ;
     RECT  9.288 35.509 9.306 35.807 ;
     RECT  0.108 35.131 0.126 35.879 ;
     RECT  38.772 36.049 38.79 36.121 ;
     RECT  2.304 35.597 8.154 36.173 ;
     RECT  2.304 36.173 3.87 36.239 ;
     RECT  2.304 36.239 2.697 36.269 ;
     RECT  38.772 36.121 38.826 36.347 ;
     RECT  38.808 36.347 38.826 36.419 ;
     RECT  5.04 36.173 8.154 36.625 ;
     RECT  5.04 36.625 8.262 36.701 ;
     RECT  9.18 36.661 9.198 36.851 ;
     RECT  5.04 36.701 8.097 37.049 ;
     RECT  7.092 37.049 8.097 37.157 ;
     RECT  5.04 37.049 6.246 37.589 ;
     RECT  3.42 36.239 3.87 37.661 ;
     RECT  10.515 33.989 10.797 38.173 ;
     RECT  7.272 37.157 8.097 38.201 ;
     RECT  3.456 37.661 3.87 38.309 ;
     RECT  94.215 2.413 94.497 38.551 ;
     RECT  96.3 38.713 96.318 38.765 ;
     RECT  94.215 38.551 95.202 38.785 ;
     RECT  94.215 38.785 95.31 38.821 ;
     RECT  93.708 38.821 95.382 38.911 ;
     RECT  91.515 2.413 91.797 38.947 ;
     RECT  93.708 38.911 95.922 38.947 ;
     RECT  75.315 2.413 75.597 39.217 ;
     RECT  75.315 39.217 75.726 39.289 ;
     RECT  88.815 2.413 89.097 39.361 ;
     RECT  3.456 38.309 3.474 39.389 ;
     RECT  88.815 39.361 89.19 39.451 ;
     RECT  90.648 38.785 90.666 39.595 ;
     RECT  88.815 39.451 89.262 39.631 ;
     RECT  90 39.595 90.738 39.631 ;
     RECT  7.308 38.201 8.097 39.659 ;
     RECT  91.515 38.947 95.922 39.829 ;
     RECT  75.24 39.289 75.726 39.865 ;
     RECT  88.815 39.631 90.738 39.865 ;
     RECT  91.515 39.829 95.994 39.865 ;
     RECT  88.815 39.865 95.994 39.869 ;
     RECT  96.912 39.091 96.93 39.883 ;
     RECT  88.815 39.869 95.778 39.917 ;
     RECT  5.04 37.589 5.922 39.979 ;
     RECT  78.015 2.413 78.297 39.991 ;
     RECT  78.015 39.991 78.642 40.091 ;
     RECT  88.815 39.917 95.706 40.091 ;
     RECT  75.168 39.865 75.762 40.135 ;
     RECT  4.5 39.979 5.922 40.171 ;
     RECT  96.912 39.883 97.47 40.171 ;
     RECT  4.176 40.171 5.922 40.199 ;
     RECT  96.912 40.171 97.506 40.349 ;
     RECT  75.168 40.135 76.23 40.441 ;
     RECT  75.168 40.441 76.338 40.567 ;
     RECT  38.772 40.603 38.79 40.703 ;
     RECT  75.168 40.567 76.374 40.711 ;
     RECT  40.215 33.043 43.197 40.787 ;
     RECT  45.615 2.413 45.897 40.787 ;
     RECT  48.315 2.413 48.597 40.787 ;
     RECT  51.015 2.413 51.297 40.787 ;
     RECT  53.715 2.413 53.997 40.787 ;
     RECT  56.415 2.413 56.697 40.787 ;
     RECT  59.115 2.413 59.397 40.787 ;
     RECT  61.815 2.413 62.097 40.787 ;
     RECT  64.515 2.413 64.797 40.787 ;
     RECT  67.215 2.413 67.497 40.787 ;
     RECT  69.915 2.413 70.197 40.787 ;
     RECT  72.615 2.413 72.897 40.787 ;
     RECT  78.015 40.091 78.297 40.837 ;
     RECT  75.096 40.711 76.446 40.873 ;
     RECT  96.912 40.349 97.47 40.891 ;
     RECT  78.015 40.837 78.678 40.937 ;
     RECT  96.3 40.891 97.47 40.937 ;
     RECT  74.844 40.873 76.446 40.973 ;
     RECT  3.42 40.891 3.438 40.981 ;
     RECT  4.176 40.199 5.397 40.981 ;
     RECT  12.168 40.843 12.186 40.981 ;
     RECT  13.215 2.413 13.497 40.981 ;
     RECT  75.024 40.973 76.446 40.981 ;
     RECT  88.815 40.091 95.346 40.981 ;
     RECT  12.168 40.981 13.497 41.021 ;
     RECT  2.415 36.269 2.697 41.035 ;
     RECT  45.615 40.787 45.705 41.057 ;
     RECT  48.315 40.787 48.405 41.057 ;
     RECT  51.015 40.787 51.105 41.057 ;
     RECT  53.715 40.787 53.805 41.057 ;
     RECT  56.415 40.787 56.505 41.057 ;
     RECT  59.115 40.787 59.205 41.057 ;
     RECT  61.815 40.787 61.905 41.057 ;
     RECT  64.515 40.787 64.605 41.057 ;
     RECT  67.215 40.787 67.305 41.057 ;
     RECT  69.915 40.787 70.005 41.057 ;
     RECT  72.615 40.787 72.705 41.057 ;
     RECT  7.815 39.659 8.097 41.083 ;
     RECT  12.24 41.021 13.497 41.099 ;
     RECT  7.272 41.083 8.37 41.107 ;
     RECT  87.804 40.837 87.822 41.135 ;
     RECT  3.42 40.981 5.397 41.143 ;
     RECT  7.128 41.107 8.37 41.179 ;
     RECT  96.912 40.937 97.47 41.179 ;
     RECT  7.056 41.179 8.37 41.251 ;
     RECT  9.936 38.173 10.797 41.251 ;
     RECT  88.815 40.981 95.778 41.279 ;
     RECT  2.304 41.035 2.697 41.323 ;
     RECT  3.42 41.143 5.706 41.323 ;
     RECT  2.304 41.323 5.706 41.369 ;
     RECT  6.804 41.251 10.797 41.369 ;
     RECT  3.492 41.369 5.706 41.411 ;
     RECT  12.24 41.099 12.258 41.597 ;
     RECT  3.636 41.411 5.706 41.611 ;
     RECT  80.715 2.413 80.997 41.791 ;
     RECT  2.304 41.369 2.754 41.909 ;
     RECT  3.636 41.611 5.886 41.989 ;
     RECT  6.804 41.369 9.09 41.989 ;
     RECT  9.936 41.369 10.797 41.995 ;
     RECT  86.115 2.413 86.397 42.025 ;
     RECT  90.9 41.279 95.778 42.043 ;
     RECT  13.215 41.099 13.497 42.061 ;
     RECT  75.024 40.981 76.554 42.151 ;
     RECT  9.936 41.995 10.818 42.173 ;
     RECT  90.9 42.043 95.922 42.187 ;
     RECT  96.912 41.179 97.506 42.187 ;
     RECT  79.344 42.151 79.362 42.359 ;
     RECT  0.108 42.331 0.126 42.449 ;
     RECT  3.636 41.989 9.09 42.449 ;
     RECT  85.176 41.647 85.194 42.529 ;
     RECT  86.115 42.025 86.67 42.557 ;
     RECT  40.215 40.787 43.074 42.565 ;
     RECT  80.244 41.791 80.997 42.565 ;
     RECT  6.804 42.449 9.09 42.593 ;
     RECT  6.84 42.593 9.09 42.601 ;
     RECT  9.936 42.173 10.797 42.601 ;
     RECT  88.815 41.279 90.126 42.601 ;
     RECT  90.9 42.187 97.506 42.601 ;
     RECT  2.304 41.909 2.697 42.691 ;
     RECT  3.636 42.449 5.958 42.691 ;
     RECT  80.244 42.565 81.162 42.871 ;
     RECT  80.244 42.871 81.918 42.961 ;
     RECT  80.244 42.961 81.99 42.989 ;
     RECT  88.815 42.601 97.506 42.989 ;
     RECT  39.744 42.565 43.074 43.033 ;
     RECT  6.84 42.601 10.797 43.061 ;
     RECT  39.6 43.033 43.074 43.069 ;
     RECT  88.815 42.989 94.878 43.133 ;
     RECT  95.652 42.989 97.506 43.133 ;
     RECT  2.304 42.691 5.958 43.169 ;
     RECT  39.204 43.069 43.074 43.2 ;
     RECT  72.972 43.069 72.99 43.2 ;
     RECT  75.024 42.151 77.238 43.2 ;
     RECT  90.684 43.133 94.878 43.259 ;
     RECT  79.488 43.141 79.506 43.303 ;
     RECT  80.244 42.989 81.234 43.303 ;
     RECT  90.684 43.259 94.734 43.331 ;
     RECT  6.84 43.061 8.586 43.339 ;
     RECT  97.488 43.133 97.506 43.439 ;
     RECT  6.732 43.339 8.586 43.501 ;
     RECT  86.115 42.557 86.397 43.501 ;
     RECT  90.9 43.331 94.734 43.529 ;
     RECT  95.652 43.133 96.354 43.529 ;
     RECT  2.415 43.169 5.958 43.609 ;
     RECT  6.696 43.501 8.586 43.609 ;
     RECT  83.415 2.413 83.697 43.681 ;
     RECT  96.336 43.529 96.354 43.709 ;
     RECT  86.115 43.501 86.886 43.799 ;
     RECT  93.204 43.529 94.734 43.799 ;
     RECT  86.115 43.799 86.778 43.835 ;
     RECT  93.24 43.799 94.497 43.907 ;
     RECT  90.9 43.529 92.466 44.059 ;
     RECT  88.815 43.133 89.766 44.107 ;
     RECT  2.415 43.609 8.586 44.203 ;
     RECT  2.304 44.203 8.586 44.249 ;
     RECT  78.015 40.937 78.297 44.347 ;
     RECT  78.015 44.347 78.318 44.443 ;
     RECT  88.815 44.107 90.09 44.519 ;
     RECT  2.415 44.249 8.586 44.525 ;
     RECT  39.204 43.2 77.238 44.539 ;
     RECT  78.015 44.443 78.426 44.539 ;
     RECT  39.204 44.539 78.426 44.669 ;
     RECT  88.815 44.519 89.766 44.717 ;
     RECT  39.204 44.669 78.297 44.725 ;
     RECT  3.42 44.525 8.586 44.761 ;
     RECT  9.324 43.061 10.797 44.761 ;
     RECT  90.828 44.059 92.466 44.761 ;
     RECT  93.24 43.907 93.402 44.761 ;
     RECT  0.108 43.195 0.126 44.813 ;
     RECT  3.42 44.761 10.797 44.879 ;
     RECT  9.936 44.879 10.797 45.059 ;
     RECT  0.144 45.067 0.162 45.197 ;
     RECT  2.415 44.525 2.697 45.355 ;
     RECT  2.304 45.355 2.697 45.419 ;
     RECT  3.42 44.879 8.838 45.419 ;
     RECT  39.024 44.725 78.297 45.691 ;
     RECT  86.115 43.835 86.397 45.691 ;
     RECT  90.828 44.761 93.402 45.841 ;
     RECT  90.54 45.841 93.402 45.959 ;
     RECT  86.115 45.691 86.67 45.967 ;
     RECT  81.972 42.989 81.99 45.979 ;
     RECT  82.908 43.681 83.697 45.979 ;
     RECT  86.04 45.967 86.67 46.067 ;
     RECT  81.972 45.979 83.697 46.109 ;
     RECT  39.024 45.691 78.678 46.205 ;
     RECT  88.815 44.717 89.097 46.267 ;
     RECT  85.176 42.529 85.302 46.301 ;
     RECT  90.612 45.959 93.402 46.301 ;
     RECT  88.704 46.267 89.097 46.397 ;
     RECT  76.932 46.205 78.678 46.493 ;
     RECT  85.212 46.301 85.302 46.679 ;
     RECT  77.796 46.493 78.678 46.747 ;
     RECT  79.488 43.303 81.234 46.747 ;
     RECT  90.648 46.301 93.402 46.769 ;
     RECT  77.796 46.747 81.234 46.877 ;
     RECT  86.04 46.067 86.397 46.877 ;
     RECT  39.024 46.205 75.87 46.921 ;
     RECT  79.488 46.877 81.234 46.949 ;
     RECT  90.648 46.769 93.186 47.039 ;
     RECT  10.515 45.059 10.797 47.047 ;
     RECT  90.648 47.039 91.926 47.047 ;
     RECT  87.768 46.777 87.786 47.069 ;
     RECT  90.036 47.047 91.926 47.083 ;
     RECT  12.816 42.061 13.497 47.111 ;
     RECT  38.772 46.921 75.87 47.111 ;
     RECT  81.972 46.109 81.99 47.117 ;
     RECT  89.964 47.083 91.926 47.147 ;
     RECT  85.212 46.679 85.23 47.165 ;
     RECT  3.42 45.419 5.886 47.219 ;
     RECT  77.796 46.877 78.39 47.219 ;
     RECT  79.488 46.949 81.09 47.219 ;
     RECT  94.14 43.907 94.497 47.219 ;
     RECT  89.964 47.147 90.054 47.405 ;
     RECT  90.036 47.405 90.054 47.453 ;
     RECT  38.88 47.111 75.87 47.645 ;
     RECT  82.908 46.109 83.697 47.645 ;
     RECT  6.624 45.419 8.838 47.893 ;
     RECT  6.624 47.893 9.162 48.029 ;
     RECT  43.2 47.645 75.87 48.125 ;
     RECT  76.932 46.493 76.95 48.127 ;
     RECT  10.515 47.047 11.43 48.389 ;
     RECT  38.88 47.645 42.282 48.631 ;
     RECT  76.32 48.127 76.95 48.701 ;
     RECT  3.42 47.219 5.397 48.731 ;
     RECT  38.772 48.631 42.282 48.797 ;
     RECT  6.876 48.029 9.162 48.803 ;
     RECT  77.796 47.219 78.297 48.811 ;
     RECT  4.032 48.731 5.397 48.839 ;
     RECT  43.2 48.125 75.33 48.901 ;
     RECT  76.32 48.701 76.41 48.901 ;
     RECT  34.815 2.413 35.097 49.045 ;
     RECT  4.212 48.839 5.397 49.073 ;
     RECT  77.724 48.811 78.297 49.339 ;
     RECT  34.776 49.045 35.097 49.343 ;
     RECT  77.652 49.339 78.297 49.531 ;
     RECT  77.616 49.531 78.297 49.577 ;
     RECT  6.876 48.803 8.154 49.649 ;
     RECT  38.772 48.797 42.174 49.783 ;
     RECT  4.68 49.073 5.397 49.883 ;
     RECT  9.144 48.803 9.162 49.919 ;
     RECT  38.772 49.783 42.21 50.017 ;
     RECT  6.876 49.649 8.097 50.189 ;
     RECT  6.876 50.189 6.894 50.279 ;
     RECT  43.2 48.901 76.41 50.333 ;
     RECT  38.772 50.017 42.246 50.431 ;
     RECT  43.2 50.333 75.192 50.431 ;
     RECT  77.688 49.577 78.297 50.431 ;
     RECT  38.772 50.431 75.192 50.629 ;
     RECT  77.652 50.431 78.297 50.665 ;
     RECT  38.628 50.629 75.192 50.669 ;
     RECT  76.356 50.333 76.41 50.813 ;
     RECT  38.808 50.669 75.192 50.855 ;
     RECT  38.844 50.855 75.192 51.101 ;
     RECT  38.844 51.101 42.246 51.485 ;
     RECT  37.515 2.413 37.797 51.709 ;
     RECT  38.844 51.485 42.174 51.709 ;
     RECT  77.58 50.665 78.297 51.736 ;
     RECT  37.515 51.709 42.174 51.773 ;
     RECT  43.092 51.101 75.192 51.835 ;
     RECT  43.056 51.835 75.192 52.219 ;
     RECT  38.52 51.773 42.174 52.249 ;
     RECT  43.02 52.219 75.192 52.249 ;
     RECT  90.828 47.147 91.926 52.321 ;
     RECT  93.168 47.039 93.186 52.321 ;
     RECT  94.215 47.219 94.497 52.321 ;
     RECT  95.76 52.249 95.778 52.321 ;
     RECT  77.544 51.736 78.297 52.411 ;
     RECT  90.828 52.321 93.186 52.483 ;
     RECT  90.648 52.483 93.186 52.519 ;
     RECT  94.068 52.321 94.986 52.519 ;
     RECT  95.76 52.321 96.354 52.519 ;
     RECT  37.515 51.773 37.797 52.555 ;
     RECT  38.52 52.249 75.192 52.555 ;
     RECT  90.648 52.519 96.354 52.555 ;
     RECT  90.468 52.555 96.354 52.589 ;
     RECT  79.488 47.219 80.997 52.619 ;
     RECT  77.4 52.411 78.297 52.789 ;
     RECT  86.115 46.877 86.397 52.789 ;
     RECT  37.515 52.555 75.192 52.825 ;
     RECT  86.115 52.789 86.706 52.825 ;
     RECT  90.468 52.589 95.958 52.825 ;
     RECT  90.324 52.825 95.958 52.877 ;
     RECT  86.115 52.825 86.778 52.979 ;
     RECT  76.392 50.813 76.41 52.987 ;
     RECT  77.22 52.789 78.297 52.987 ;
     RECT  76.392 52.987 78.297 53.015 ;
     RECT  37.515 52.825 75.51 53.179 ;
     RECT  37.515 53.179 75.834 53.261 ;
     RECT  38.772 53.261 75.834 53.429 ;
     RECT  76.968 53.015 78.297 53.555 ;
     RECT  97.488 53.275 97.506 53.563 ;
     RECT  96.876 53.563 97.506 53.6 ;
     RECT  90.828 52.877 95.958 53.761 ;
     RECT  38.988 53.429 75.834 53.905 ;
     RECT  97.452 53.6 97.506 53.933 ;
     RECT  90.792 53.761 95.958 53.941 ;
     RECT  97.452 53.933 97.47 54.131 ;
     RECT  90.792 53.941 96.354 54.211 ;
     RECT  86.115 52.979 86.397 54.409 ;
     RECT  38.988 53.905 76.086 54.445 ;
     RECT  86.115 54.409 86.67 54.509 ;
     RECT  90.36 54.211 96.354 54.749 ;
     RECT  77.22 53.555 78.297 54.949 ;
     RECT  37.515 53.261 37.797 55.291 ;
     RECT  38.988 54.445 76.122 55.291 ;
     RECT  37.515 55.291 76.122 55.409 ;
     RECT  37.515 55.409 38.538 55.445 ;
     RECT  90.36 54.749 95.958 55.579 ;
     RECT  90.36 55.579 96.354 55.679 ;
     RECT  77.22 54.949 78.93 55.687 ;
     RECT  80.064 52.619 80.997 55.687 ;
     RECT  90.72 55.679 96.354 55.717 ;
     RECT  97.488 54.859 97.506 55.717 ;
     RECT  39.708 55.409 76.122 55.723 ;
     RECT  90.72 55.717 97.506 55.757 ;
     RECT  88.815 46.397 89.097 56.065 ;
     RECT  97.488 55.757 97.506 56.155 ;
     RECT  86.115 54.509 86.397 56.227 ;
     RECT  86.115 56.227 86.67 56.327 ;
     RECT  97.488 56.155 97.578 56.327 ;
     RECT  88.815 56.065 89.766 56.429 ;
     RECT  77.22 55.687 80.997 56.489 ;
     RECT  90.72 55.757 96.39 56.587 ;
     RECT  97.488 56.327 97.506 56.587 ;
     RECT  90.72 56.587 97.506 57.001 ;
     RECT  90.648 57.001 97.506 57.029 ;
     RECT  88.815 56.429 89.226 57.053 ;
     RECT  86.115 56.327 86.397 57.109 ;
     RECT  90.648 57.029 92.754 57.173 ;
     RECT  93.6 57.029 97.506 57.173 ;
     RECT  86.115 57.109 86.67 57.209 ;
     RECT  93.6 57.173 96.39 57.209 ;
     RECT  90.72 57.173 92.754 57.299 ;
     RECT  97.488 57.173 97.506 57.299 ;
     RECT  93.6 57.209 95.958 58.721 ;
     RECT  91.515 57.299 92.754 60.449 ;
     RECT  39.708 55.723 76.158 60.504 ;
     RECT  93.6 58.721 95.886 60.605 ;
     RECT  91.515 60.449 92.682 60.611 ;
     RECT  70.704 60.504 70.794 60.647 ;
     RECT  70.704 60.647 70.722 60.809 ;
     RECT  86.115 57.209 86.397 61.051 ;
     RECT  93.6 60.605 94.914 61.079 ;
     RECT  95.868 60.605 95.886 61.085 ;
     RECT  93.6 61.079 94.497 61.115 ;
     RECT  91.515 60.611 92.61 61.151 ;
     RECT  74.664 60.504 76.158 61.181 ;
     RECT  86.115 61.051 86.67 61.181 ;
     RECT  77.22 56.489 79.506 61.187 ;
     RECT  75.204 61.181 76.158 61.223 ;
     RECT  75.204 61.223 76.086 61.259 ;
     RECT  75.204 61.259 75.654 61.349 ;
     RECT  77.436 61.187 79.506 61.421 ;
     RECT  75.204 61.349 75.582 61.457 ;
     RECT  90.72 57.299 90.738 61.619 ;
     RECT  39.708 60.504 42.75 61.655 ;
     RECT  78.015 61.421 79.506 61.655 ;
     RECT  93.78 61.115 94.497 61.661 ;
     RECT  50.76 62.509 50.778 62.545 ;
     RECT  41.22 61.655 42.75 62.573 ;
     RECT  50.508 62.545 50.778 62.581 ;
     RECT  78.015 61.655 78.93 62.609 ;
     RECT  50.4 62.581 50.778 62.623 ;
     RECT  75.204 61.457 75.366 62.623 ;
     RECT  50.4 62.623 51.105 62.699 ;
     RECT  92.592 61.151 92.61 62.699 ;
     RECT  50.76 62.699 51.105 62.879 ;
     RECT  42.915 62.623 43.005 62.893 ;
     RECT  45.615 62.623 45.705 62.893 ;
     RECT  48.315 62.623 48.405 62.893 ;
     RECT  51.015 62.879 51.105 62.893 ;
     RECT  53.715 62.623 53.805 62.893 ;
     RECT  56.415 62.623 56.505 62.893 ;
     RECT  59.115 62.623 59.205 62.893 ;
     RECT  61.815 62.623 61.905 62.893 ;
     RECT  64.515 62.623 64.605 62.893 ;
     RECT  67.215 62.623 67.305 62.893 ;
     RECT  69.915 62.623 70.005 62.893 ;
     RECT  72.615 62.623 72.705 62.893 ;
     RECT  75.204 62.623 75.405 62.893 ;
     RECT  75.204 62.893 75.597 63.275 ;
     RECT  42.915 62.893 43.197 64.561 ;
     RECT  42.915 64.561 43.542 64.859 ;
     RECT  42.915 64.859 43.398 70.673 ;
     RECT  77.184 73.723 77.202 73.769 ;
     RECT  3.888 74.083 3.906 74.191 ;
     RECT  2.415 45.419 2.697 74.281 ;
     RECT  3.42 74.191 3.906 74.281 ;
     RECT  76.86 73.813 76.878 74.309 ;
     RECT  2.415 74.281 4.302 74.443 ;
     RECT  5.115 49.883 5.397 74.461 ;
     RECT  2.304 74.443 4.302 74.489 ;
     RECT  5.115 74.461 5.634 74.551 ;
     RECT  7.815 50.189 8.097 74.551 ;
     RECT  34.815 49.343 35.097 74.587 ;
     RECT  0.18 74.587 0.198 74.623 ;
     RECT  2.304 74.489 3.546 74.623 ;
     RECT  4.284 74.489 4.302 74.623 ;
     RECT  5.115 74.551 5.706 74.623 ;
     RECT  42.915 70.673 43.326 74.659 ;
     RECT  0.18 74.623 0.27 74.669 ;
     RECT  13.215 47.111 13.497 74.683 ;
     RECT  0.18 74.669 0.198 74.731 ;
     RECT  0.108 74.731 0.198 74.768 ;
     RECT  13.215 74.683 13.842 74.849 ;
     RECT  1.728 74.623 3.546 74.909 ;
     RECT  4.284 74.623 5.706 74.929 ;
     RECT  6.912 74.461 6.93 74.929 ;
     RECT  4.284 74.929 6.93 74.971 ;
     RECT  7.815 74.551 8.154 74.971 ;
     RECT  4.284 74.971 8.154 75.001 ;
     RECT  0.18 74.768 0.198 75.053 ;
     RECT  2.415 74.909 3.546 75.271 ;
     RECT  4.284 75.001 8.55 75.271 ;
     RECT  2.415 75.271 8.55 75.389 ;
     RECT  7.38 75.389 8.55 75.569 ;
     RECT  0.144 75.595 0.162 75.883 ;
     RECT  0.144 75.883 0.198 76.027 ;
     RECT  9.684 75.361 9.702 76.081 ;
     RECT  9.396 76.081 9.702 76.109 ;
     RECT  2.415 75.389 4.014 76.171 ;
     RECT  4.752 75.389 6.39 76.171 ;
     RECT  2.304 76.171 6.39 76.207 ;
     RECT  7.38 75.569 8.442 76.207 ;
     RECT  2.304 76.207 8.442 76.208 ;
     RECT  0.108 76.027 0.198 76.603 ;
     RECT  37.515 55.445 37.797 76.621 ;
     RECT  38.52 55.445 38.538 76.621 ;
     RECT  0.108 76.603 0.342 76.811 ;
     RECT  2.415 76.208 8.442 76.891 ;
     RECT  0.216 76.811 0.342 76.928 ;
     RECT  2.415 76.891 8.586 76.928 ;
     RECT  0.54 77.161 0.558 77.213 ;
     RECT  37.515 76.621 38.538 77.287 ;
     RECT  2.415 76.928 8.442 77.791 ;
     RECT  39.708 61.655 40.497 77.791 ;
     RECT  41.22 62.573 42.174 77.791 ;
     RECT  11.988 75.091 12.006 77.819 ;
     RECT  0.108 77.755 0.126 77.947 ;
     RECT  2.415 77.791 8.478 77.971 ;
     RECT  2.415 77.971 8.622 78.205 ;
     RECT  9.396 76.109 9.414 78.205 ;
     RECT  37.515 77.287 38.574 78.367 ;
     RECT  39.708 77.791 42.174 78.367 ;
     RECT  2.415 78.205 9.414 78.475 ;
     RECT  0.108 77.947 0.162 78.539 ;
     RECT  0.144 78.539 0.162 78.797 ;
     RECT  2.304 78.475 9.414 78.971 ;
     RECT  2.304 78.971 2.697 79.079 ;
     RECT  3.42 78.971 9.414 79.681 ;
     RECT  94.215 61.661 94.497 81.211 ;
     RECT  91.515 61.151 91.797 81.571 ;
     RECT  78.015 62.609 78.297 81.607 ;
     RECT  90.648 81.067 90.666 81.635 ;
     RECT  93.24 81.607 93.258 81.637 ;
     RECT  91.515 81.571 91.854 81.643 ;
     RECT  96.3 81.355 96.318 81.707 ;
     RECT  91.404 81.643 91.854 81.751 ;
     RECT  92.628 81.637 93.258 81.751 ;
     RECT  94.215 81.211 94.77 81.751 ;
     RECT  78.015 81.607 78.642 81.779 ;
     RECT  94.212 81.751 95.382 81.787 ;
     RECT  94.212 81.787 95.922 81.869 ;
     RECT  80.715 56.489 80.997 81.877 ;
     RECT  90.108 81.739 90.126 81.905 ;
     RECT  91.404 81.751 93.258 81.913 ;
     RECT  97.488 81.499 97.506 81.931 ;
     RECT  94.212 81.869 95.382 81.977 ;
     RECT  75.315 63.275 75.597 82.021 ;
     RECT  88.815 57.053 89.097 82.021 ;
     RECT  91.404 81.913 93.33 82.021 ;
     RECT  94.212 81.977 95.13 82.021 ;
     RECT  86.115 61.181 86.397 82.147 ;
     RECT  88.815 82.021 89.514 82.175 ;
     RECT  96.912 81.931 97.506 82.219 ;
     RECT  86.115 82.147 86.634 82.283 ;
     RECT  91.404 82.021 95.13 82.291 ;
     RECT  80.715 81.877 81.522 82.319 ;
     RECT  96.912 82.219 97.542 82.319 ;
     RECT  96.912 82.319 97.002 82.507 ;
     RECT  75.315 82.021 76.266 82.525 ;
     RECT  96.3 82.507 97.002 82.553 ;
     RECT  42.915 74.659 43.398 82.589 ;
     RECT  75.24 82.525 76.266 82.651 ;
     RECT  78.015 81.779 78.297 82.687 ;
     RECT  90.9 82.291 95.13 82.723 ;
     RECT  78.015 82.687 78.642 82.787 ;
     RECT  75.24 82.651 76.698 82.831 ;
     RECT  90.18 82.723 95.13 82.949 ;
     RECT  75.132 82.831 76.734 82.957 ;
     RECT  88.056 81.751 88.074 82.993 ;
     RECT  88.815 82.175 89.097 82.993 ;
     RECT  75.132 82.957 76.806 83.101 ;
     RECT  95.976 82.831 95.994 83.101 ;
     RECT  98.172 82.939 98.19 83.129 ;
     RECT  37.515 78.367 42.174 83.191 ;
     RECT  42.915 82.589 43.326 83.191 ;
     RECT  75.132 83.101 76.878 83.219 ;
     RECT  95.76 83.101 95.994 83.219 ;
     RECT  96.912 82.553 97.002 83.371 ;
     RECT  88.056 82.993 89.097 83.399 ;
     RECT  13.215 74.849 13.497 83.533 ;
     RECT  3.42 79.681 9.45 83.561 ;
     RECT  22.5 76.207 22.518 83.561 ;
     RECT  37.515 83.191 43.326 83.563 ;
     RECT  37.515 83.563 43.614 83.759 ;
     RECT  95.76 83.219 95.922 83.759 ;
     RECT  90.18 82.949 94.95 83.795 ;
     RECT  90.684 83.795 94.95 83.839 ;
     RECT  95.76 83.759 95.778 83.839 ;
     RECT  45.615 62.893 45.897 83.987 ;
     RECT  48.315 62.893 48.597 83.987 ;
     RECT  51.015 62.893 51.297 83.987 ;
     RECT  53.715 62.893 53.997 83.987 ;
     RECT  56.415 62.893 56.697 83.987 ;
     RECT  59.115 62.893 59.397 83.987 ;
     RECT  61.815 62.893 62.097 83.987 ;
     RECT  64.515 62.893 64.797 83.987 ;
     RECT  67.215 62.893 67.497 83.987 ;
     RECT  69.915 62.893 70.197 83.987 ;
     RECT  72.615 62.893 72.897 83.987 ;
     RECT  3.744 83.561 9.45 84.101 ;
     RECT  66.276 84.073 66.294 84.125 ;
     RECT  4.716 84.101 9.45 84.137 ;
     RECT  75.132 83.219 76.806 84.145 ;
     RECT  88.056 83.399 88.074 84.181 ;
     RECT  88.815 83.399 89.097 84.181 ;
     RECT  37.515 83.759 43.542 84.209 ;
     RECT  96.912 83.371 97.506 84.209 ;
     RECT  37.515 84.209 43.005 84.257 ;
     RECT  45.615 83.987 45.705 84.257 ;
     RECT  48.315 83.987 48.405 84.257 ;
     RECT  51.015 83.987 51.105 84.257 ;
     RECT  53.715 83.987 53.805 84.257 ;
     RECT  56.415 83.987 56.505 84.257 ;
     RECT  59.115 83.987 59.205 84.257 ;
     RECT  61.815 83.987 61.905 84.257 ;
     RECT  64.515 83.987 64.746 84.257 ;
     RECT  67.215 83.987 67.305 84.257 ;
     RECT  69.915 83.987 70.005 84.257 ;
     RECT  72.615 83.987 72.705 84.257 ;
     RECT  74.952 84.145 76.806 84.299 ;
     RECT  85.104 84.043 85.122 84.299 ;
     RECT  90.684 83.839 95.778 84.299 ;
     RECT  64.728 84.257 64.746 84.365 ;
     RECT  84.96 84.331 84.978 84.371 ;
     RECT  90.684 84.299 94.554 84.371 ;
     RECT  97.488 84.209 97.506 84.379 ;
     RECT  78.015 82.787 78.297 84.451 ;
     RECT  97.488 84.379 97.542 84.523 ;
     RECT  77.796 84.451 78.297 84.569 ;
     RECT  75.132 84.299 76.806 84.721 ;
     RECT  0.54 84.667 0.558 84.749 ;
     RECT  3.744 84.101 3.762 84.811 ;
     RECT  95.364 84.299 95.778 84.811 ;
     RECT  3.42 84.811 3.762 84.883 ;
     RECT  4.716 84.137 6.03 84.883 ;
     RECT  88.056 84.181 89.097 84.907 ;
     RECT  95.364 84.811 96.318 84.911 ;
     RECT  0.144 84.811 0.162 84.941 ;
     RECT  3.42 84.883 6.03 84.941 ;
     RECT  88.056 84.907 89.514 84.941 ;
     RECT  88.815 84.941 89.514 84.991 ;
     RECT  95.364 84.911 95.922 85.145 ;
     RECT  7.02 84.137 9.45 85.189 ;
     RECT  10.515 48.389 10.797 85.189 ;
     RECT  88.815 84.991 89.55 85.189 ;
     RECT  2.415 79.079 2.697 85.243 ;
     RECT  7.02 85.189 10.797 85.261 ;
     RECT  80.715 82.319 80.997 85.261 ;
     RECT  86.115 82.283 86.397 85.261 ;
     RECT  2.304 85.243 2.697 85.289 ;
     RECT  75.132 84.721 77.274 85.351 ;
     RECT  78.015 84.569 78.297 85.351 ;
     RECT  85.644 85.261 86.397 85.379 ;
     RECT  88.815 85.189 89.838 85.379 ;
     RECT  80.715 85.261 81.378 85.381 ;
     RECT  90.9 84.371 94.554 85.387 ;
     RECT  7.02 85.261 10.818 85.415 ;
     RECT  90.9 85.387 95.202 85.423 ;
     RECT  88.815 85.379 89.694 85.469 ;
     RECT  75.132 85.351 78.75 85.487 ;
     RECT  97.488 84.523 97.578 85.487 ;
     RECT  90.792 85.423 95.202 85.531 ;
     RECT  80.715 85.381 81.846 85.559 ;
     RECT  0.108 85.531 0.126 85.568 ;
     RECT  3.744 84.941 6.03 85.621 ;
     RECT  7.02 85.415 10.797 85.621 ;
     RECT  86.076 85.379 86.397 85.649 ;
     RECT  88.056 84.941 88.074 85.771 ;
     RECT  2.415 85.289 2.697 85.801 ;
     RECT  3.744 85.621 10.797 85.801 ;
     RECT  96.3 85.675 96.318 85.819 ;
     RECT  97.488 85.487 97.506 85.819 ;
     RECT  96.3 85.819 97.506 85.829 ;
     RECT  0.54 85.801 0.558 85.853 ;
     RECT  87.948 85.771 88.074 85.891 ;
     RECT  88.815 85.469 89.622 85.891 ;
     RECT  87.948 85.891 89.622 85.919 ;
     RECT  81.828 85.559 81.846 85.955 ;
     RECT  96.3 85.829 96.93 85.991 ;
     RECT  88.056 85.919 89.622 85.997 ;
     RECT  90.612 85.531 95.202 85.997 ;
     RECT  37.515 84.257 42.894 86.059 ;
     RECT  86.115 85.649 86.397 86.161 ;
     RECT  88.815 85.997 89.622 86.189 ;
     RECT  95.364 86.071 95.382 86.189 ;
     RECT  88.815 86.189 89.478 86.225 ;
     RECT  96.912 85.991 96.93 86.261 ;
     RECT  81.936 86.035 81.954 86.341 ;
     RECT  90.612 85.997 94.497 86.341 ;
     RECT  90.396 86.341 94.497 86.369 ;
     RECT  37.515 86.059 43.11 86.4 ;
     RECT  75.132 85.487 78.297 86.4 ;
     RECT  86.115 86.161 86.67 86.459 ;
     RECT  0.144 86.395 0.162 86.525 ;
     RECT  90.396 86.369 93.33 86.603 ;
     RECT  90.9 86.603 93.33 86.765 ;
     RECT  2.415 85.801 10.797 86.809 ;
     RECT  34.815 74.587 35.622 86.999 ;
     RECT  2.415 86.809 10.926 87.035 ;
     RECT  88.815 86.225 89.097 87.259 ;
     RECT  37.515 86.4 78.297 87.307 ;
     RECT  2.415 87.035 10.854 87.403 ;
     RECT  37.515 87.307 78.678 87.403 ;
     RECT  2.304 87.403 10.854 87.449 ;
     RECT  83.415 47.645 83.697 87.547 ;
     RECT  37.515 87.403 78.894 87.581 ;
     RECT  34.815 86.999 35.097 87.583 ;
     RECT  83.376 87.547 83.697 87.595 ;
     RECT  2.415 87.449 10.854 87.611 ;
     RECT  37.515 87.581 78.786 87.677 ;
     RECT  88.056 85.997 88.074 87.917 ;
     RECT  0.108 86.971 0.126 87.979 ;
     RECT  13.215 83.533 13.95 88.079 ;
     RECT  0.108 87.979 0.198 88.109 ;
     RECT  90.9 86.765 93.222 88.223 ;
     RECT  0.108 88.109 0.126 88.259 ;
     RECT  90.9 88.223 92.898 88.321 ;
     RECT  2.415 87.611 10.797 88.555 ;
     RECT  37.515 87.677 78.297 88.637 ;
     RECT  2.304 88.555 10.797 88.691 ;
     RECT  37.515 88.637 76.23 88.733 ;
     RECT  34.776 87.583 35.097 88.763 ;
     RECT  2.304 88.691 8.838 88.771 ;
     RECT  2.052 88.771 8.838 88.877 ;
     RECT  77.22 88.637 78.297 88.939 ;
     RECT  86.115 86.459 86.397 88.939 ;
     RECT  90.648 88.321 92.898 89.159 ;
     RECT  2.304 88.877 8.838 89.168 ;
     RECT  2.415 89.168 8.838 89.231 ;
     RECT  9.936 88.691 10.797 89.303 ;
     RECT  43.2 88.733 76.23 89.803 ;
     RECT  37.515 88.733 42.246 89.845 ;
     RECT  43.2 89.803 76.302 89.845 ;
     RECT  37.515 89.845 76.302 89.885 ;
     RECT  43.2 89.885 76.302 89.888 ;
     RECT  88.815 87.259 89.766 90.013 ;
     RECT  86.115 88.939 86.67 90.211 ;
     RECT  90.648 89.159 92.826 90.239 ;
     RECT  77.22 88.939 78.678 90.247 ;
     RECT  91.044 90.239 92.826 90.269 ;
     RECT  88.776 90.013 89.766 90.365 ;
     RECT  2.415 89.231 8.658 90.419 ;
     RECT  86.076 90.211 86.67 90.419 ;
     RECT  76.932 90.247 78.678 90.461 ;
     RECT  81.936 86.341 82.35 90.557 ;
     RECT  91.044 90.269 92.07 90.653 ;
     RECT  77.904 90.461 78.678 90.779 ;
     RECT  82.332 90.557 82.35 90.845 ;
     RECT  37.515 89.885 42.246 90.859 ;
     RECT  43.2 89.888 75.87 90.859 ;
     RECT  78.015 90.779 78.678 90.893 ;
     RECT  86.076 90.419 86.397 90.893 ;
     RECT  2.415 90.419 6.858 90.923 ;
     RECT  93.168 90.931 93.186 90.989 ;
     RECT  2.415 90.923 3.87 91.049 ;
     RECT  34.815 88.763 35.097 91.435 ;
     RECT  7.632 90.419 8.658 91.463 ;
     RECT  37.515 90.859 75.87 91.471 ;
     RECT  76.932 90.461 76.95 91.471 ;
     RECT  37.515 91.471 76.95 91.613 ;
     RECT  37.515 91.613 75.546 91.709 ;
     RECT  37.515 91.709 75.192 91.769 ;
     RECT  38.52 91.769 75.192 91.997 ;
     RECT  78.015 90.893 78.297 92.011 ;
     RECT  4.644 90.923 6.858 92.039 ;
     RECT  76.32 91.613 76.95 92.245 ;
     RECT  77.724 92.011 78.297 92.245 ;
     RECT  76.32 92.245 78.297 92.285 ;
     RECT  76.392 92.285 78.297 92.477 ;
     RECT  9.396 89.473 9.414 92.579 ;
     RECT  34.776 91.435 35.097 92.777 ;
     RECT  38.52 91.997 42.21 92.983 ;
     RECT  43.092 91.997 75.192 92.983 ;
     RECT  7.632 91.463 8.37 93.047 ;
     RECT  4.644 92.039 5.994 93.083 ;
     RECT  37.515 91.769 37.797 93.091 ;
     RECT  38.52 92.983 75.192 93.091 ;
     RECT  6.84 92.039 6.858 93.119 ;
     RECT  22.464 93.163 22.482 93.209 ;
     RECT  37.515 93.091 75.192 93.209 ;
     RECT  21.315 2.413 21.597 93.289 ;
     RECT  21.315 93.289 22.122 93.341 ;
     RECT  2.415 91.049 3.618 93.515 ;
     RECT  7.815 93.047 8.37 93.551 ;
     RECT  76.392 92.477 76.41 93.659 ;
     RECT  77.436 92.477 78.297 93.749 ;
     RECT  77.58 93.749 78.297 93.917 ;
     RECT  38.52 93.209 75.192 94.027 ;
     RECT  76.356 93.793 76.374 94.027 ;
     RECT  34.815 92.777 35.097 94.063 ;
     RECT  3.6 93.515 3.618 94.091 ;
     RECT  38.52 94.027 76.374 94.109 ;
     RECT  37.515 93.209 37.797 94.261 ;
     RECT  38.52 94.109 42.21 94.261 ;
     RECT  43.02 94.109 76.374 94.405 ;
     RECT  37.515 94.261 42.21 94.703 ;
     RECT  4.788 93.083 5.994 94.829 ;
     RECT  38.52 94.703 42.21 94.877 ;
     RECT  34.776 94.063 35.097 94.901 ;
     RECT  43.02 94.405 76.41 94.94 ;
     RECT  77.616 93.917 78.297 95.035 ;
     RECT  77.58 95.035 78.297 95.135 ;
     RECT  5.115 94.829 5.994 95.207 ;
     RECT  43.056 94.94 76.41 95.261 ;
     RECT  77.616 95.135 78.297 95.369 ;
     RECT  76.392 95.261 76.41 95.485 ;
     RECT  76.392 95.485 76.446 95.645 ;
     RECT  38.52 94.877 42.174 95.707 ;
     RECT  43.056 95.261 75.192 95.707 ;
     RECT  38.52 95.707 75.192 95.741 ;
     RECT  94.215 86.369 94.497 95.881 ;
     RECT  77.652 95.369 78.297 96.091 ;
     RECT  91.332 90.653 92.07 96.151 ;
     RECT  94.215 95.881 95.202 96.151 ;
     RECT  94.215 96.151 95.454 96.235 ;
     RECT  38.628 95.741 75.192 96.295 ;
     RECT  93.708 96.235 95.454 96.295 ;
     RECT  90.648 96.151 92.07 96.331 ;
     RECT  93.24 96.295 95.454 96.331 ;
     RECT  96.336 96.061 96.354 96.331 ;
     RECT  86.115 90.893 86.397 96.421 ;
     RECT  77.58 96.091 78.297 96.449 ;
     RECT  90.648 96.331 96.354 96.449 ;
     RECT  76.392 95.645 76.41 96.475 ;
     RECT  88.815 90.365 89.766 96.565 ;
     RECT  90.648 96.449 92.466 96.565 ;
     RECT  38.628 96.295 75.51 96.571 ;
     RECT  76.392 96.475 76.446 96.571 ;
     RECT  38.628 96.571 76.446 96.719 ;
     RECT  39.492 96.719 76.446 96.755 ;
     RECT  77.22 96.565 77.238 96.763 ;
     RECT  93.24 96.449 96.354 96.8 ;
     RECT  39.492 96.755 75.834 96.827 ;
     RECT  97.488 96.475 97.506 96.827 ;
     RECT  39.6 96.827 75.834 96.863 ;
     RECT  88.815 96.565 92.466 96.863 ;
     RECT  38.628 96.719 38.754 96.893 ;
     RECT  86.115 96.421 86.67 97.169 ;
     RECT  88.815 96.863 90.45 97.331 ;
     RECT  93.24 96.8 95.922 97.529 ;
     RECT  91.26 96.863 92.466 97.681 ;
     RECT  93.24 97.529 95.778 97.681 ;
     RECT  96.912 97.339 96.93 97.771 ;
     RECT  39.888 96.863 75.834 98.149 ;
     RECT  76.644 96.763 77.238 98.149 ;
     RECT  86.115 97.169 86.397 98.149 ;
     RECT  88.815 97.331 90.342 98.149 ;
     RECT  91.188 97.681 95.778 98.149 ;
     RECT  88.815 98.149 95.778 98.249 ;
     RECT  86.115 98.149 86.67 98.339 ;
     RECT  95.76 98.249 95.778 98.669 ;
     RECT  96.912 97.771 97.506 98.761 ;
     RECT  98.244 98.731 98.262 98.761 ;
     RECT  96.912 98.761 98.262 98.789 ;
     RECT  96.912 98.789 98.19 98.813 ;
     RECT  88.815 98.249 94.914 99.031 ;
     RECT  96.912 98.813 97.506 99.101 ;
     RECT  86.115 98.339 86.397 99.427 ;
     RECT  86.115 99.427 86.67 99.599 ;
     RECT  96.912 99.101 96.93 99.599 ;
     RECT  85.284 99.571 85.302 99.689 ;
     RECT  88.815 99.031 95.31 99.689 ;
     RECT  83.376 87.595 83.754 99.761 ;
     RECT  86.115 99.599 86.397 99.841 ;
     RECT  22.356 99.835 22.374 99.959 ;
     RECT  83.415 99.761 83.754 99.959 ;
     RECT  85.392 99.841 86.397 99.959 ;
     RECT  90 99.689 95.31 99.959 ;
     RECT  21.315 93.341 21.597 99.967 ;
     RECT  21.315 99.967 22.23 100.013 ;
     RECT  96.3 99.787 96.318 100.067 ;
     RECT  96.336 100.651 96.354 100.829 ;
     RECT  88.815 99.689 89.262 100.841 ;
     RECT  90.072 99.959 95.31 100.949 ;
     RECT  97.488 99.841 97.506 101.219 ;
     RECT  90.072 100.949 95.238 101.489 ;
     RECT  39.888 98.149 77.238 102.389 ;
     RECT  39.888 102.389 76.194 103.704 ;
     RECT  93.564 101.489 95.238 103.847 ;
     RECT  90.072 101.489 92.79 103.883 ;
     RECT  90.072 103.883 92.466 103.919 ;
     RECT  74.664 103.704 76.194 103.964 ;
     RECT  90.072 103.919 92.25 104.009 ;
     RECT  75.168 103.964 76.194 104.189 ;
     RECT  93.672 103.847 95.238 104.423 ;
     RECT  93.672 104.423 94.497 104.459 ;
     RECT  90.072 104.009 90.486 104.549 ;
     RECT  75.168 104.189 76.122 104.585 ;
     RECT  77.22 102.389 77.238 104.621 ;
     RECT  37.515 94.703 37.797 104.791 ;
     RECT  91.515 104.009 92.25 104.927 ;
     RECT  37.515 104.791 37.854 104.965 ;
     RECT  38.628 96.893 38.646 104.965 ;
     RECT  37.515 104.965 38.646 105.089 ;
     RECT  90.072 104.549 90.09 105.161 ;
     RECT  93.744 104.459 94.497 105.197 ;
     RECT  51.552 105.169 51.57 105.601 ;
     RECT  48.852 105.673 48.87 105.709 ;
     RECT  51.408 105.601 51.57 105.745 ;
     RECT  39.888 103.704 43.146 105.773 ;
     RECT  48.852 105.709 48.942 105.781 ;
     RECT  51.408 105.745 51.642 105.781 ;
     RECT  75.168 104.585 75.582 105.809 ;
     RECT  46.296 105.133 46.314 105.823 ;
     RECT  48.852 105.781 49.158 105.823 ;
     RECT  51.336 105.781 51.642 105.823 ;
     RECT  65.232 105.451 65.25 105.823 ;
     RECT  45.615 105.823 46.314 105.899 ;
     RECT  48.315 105.823 49.158 105.899 ;
     RECT  51.015 105.823 51.642 105.899 ;
     RECT  64.515 105.823 65.25 105.899 ;
     RECT  64.515 105.899 64.89 105.971 ;
     RECT  75.276 105.809 75.582 106.007 ;
     RECT  95.22 104.423 95.238 106.043 ;
     RECT  42.915 105.773 43.146 106.093 ;
     RECT  53.715 105.823 53.805 106.093 ;
     RECT  56.415 105.823 56.505 106.093 ;
     RECT  59.115 105.823 59.205 106.093 ;
     RECT  61.815 105.823 61.905 106.093 ;
     RECT  67.215 105.823 67.305 106.093 ;
     RECT  69.915 105.823 70.005 106.093 ;
     RECT  72.615 105.823 72.705 106.093 ;
     RECT  75.315 106.007 75.582 106.093 ;
     RECT  42.915 106.093 43.197 107.275 ;
     RECT  42.915 107.275 43.254 107.671 ;
     RECT  42.915 107.671 43.542 108.509 ;
     RECT  42.915 108.509 43.398 108.653 ;
     RECT  64.515 105.971 64.797 110.011 ;
     RECT  64.515 110.011 64.854 110.461 ;
     RECT  64.515 110.461 65.034 110.525 ;
     RECT  39.888 105.773 42.174 113.431 ;
     RECT  42.915 108.653 43.197 113.431 ;
     RECT  34.815 94.901 35.097 116.545 ;
     RECT  34.815 116.545 35.586 116.581 ;
     RECT  36.504 116.545 36.522 116.581 ;
     RECT  34.815 116.581 36.522 116.699 ;
     RECT  39.888 113.431 43.197 116.879 ;
     RECT  5.115 95.207 5.397 117.085 ;
     RECT  37.515 105.089 37.797 117.391 ;
     RECT  38.628 105.089 38.646 117.391 ;
     RECT  34.815 116.699 36.342 117.481 ;
     RECT  37.515 117.391 38.646 117.481 ;
     RECT  34.815 117.481 36.486 117.661 ;
     RECT  37.476 117.481 38.826 117.661 ;
     RECT  34.815 117.661 36.738 118.021 ;
     RECT  37.476 117.661 38.898 118.021 ;
     RECT  34.815 118.021 38.898 118.049 ;
     RECT  0.144 118.021 0.162 118.075 ;
     RECT  4.896 117.085 5.397 118.129 ;
     RECT  34.815 118.049 38.826 118.129 ;
     RECT  34.776 118.129 38.826 118.157 ;
     RECT  34.776 118.157 38.466 118.193 ;
     RECT  3.42 117.661 3.438 118.201 ;
     RECT  4.284 118.129 5.397 118.201 ;
     RECT  0.108 118.075 0.162 118.229 ;
     RECT  34.776 118.193 38.43 118.229 ;
     RECT  0.144 118.229 0.162 118.253 ;
     RECT  2.415 93.515 2.697 118.291 ;
     RECT  3.42 118.201 5.397 118.291 ;
     RECT  2.415 118.291 5.397 118.363 ;
     RECT  6.156 118.291 6.174 118.363 ;
     RECT  2.415 118.363 6.174 118.471 ;
     RECT  7.815 93.551 8.097 118.561 ;
     RECT  2.415 118.471 6.75 118.589 ;
     RECT  9.288 118.561 9.306 118.697 ;
     RECT  4.176 118.589 6.75 118.769 ;
     RECT  2.415 118.589 3.438 118.795 ;
     RECT  4.392 118.769 6.75 118.831 ;
     RECT  7.815 118.561 8.514 118.831 ;
     RECT  0.144 118.987 0.162 119.117 ;
     RECT  2.304 118.795 3.438 119.129 ;
     RECT  4.392 118.831 8.514 119.237 ;
     RECT  2.304 119.129 3.294 119.408 ;
     RECT  4.392 119.237 8.262 119.551 ;
     RECT  4.248 119.551 8.262 119.669 ;
     RECT  9.036 119.551 9.054 119.669 ;
     RECT  22.644 119.131 22.662 119.669 ;
     RECT  6.696 119.669 8.262 119.813 ;
     RECT  39.24 119.749 39.258 119.911 ;
     RECT  34.815 118.229 38.43 120.019 ;
     RECT  39.204 119.911 39.258 120.019 ;
     RECT  4.248 119.669 5.922 120.091 ;
     RECT  0.108 119.227 0.126 120.119 ;
     RECT  40.14 116.879 43.197 120.217 ;
     RECT  34.815 120.019 39.258 120.235 ;
     RECT  40.032 120.217 43.197 120.235 ;
     RECT  34.815 120.235 43.197 120.253 ;
     RECT  2.415 119.408 3.294 120.451 ;
     RECT  4.14 120.091 5.922 120.451 ;
     RECT  2.415 120.451 5.922 120.523 ;
     RECT  2.415 120.523 5.958 120.559 ;
     RECT  6.696 119.813 8.154 120.559 ;
     RECT  2.415 120.559 8.154 120.749 ;
     RECT  9.072 120.523 9.09 120.749 ;
     RECT  6.264 120.749 8.154 120.865 ;
     RECT  34.815 120.253 43.29 120.865 ;
     RECT  0.144 120.379 0.162 120.955 ;
     RECT  0.108 120.955 0.162 121.199 ;
     RECT  6.264 120.865 8.982 121.469 ;
     RECT  2.415 120.749 5.397 121.531 ;
     RECT  6.444 121.469 8.982 121.531 ;
     RECT  6.444 121.531 9.306 121.567 ;
     RECT  0.144 121.199 0.162 121.661 ;
     RECT  2.415 121.531 5.706 121.829 ;
     RECT  6.444 121.567 9.378 121.829 ;
     RECT  2.415 121.829 2.697 121.963 ;
     RECT  34.776 120.865 43.29 121.973 ;
     RECT  2.304 121.963 2.697 122.009 ;
     RECT  3.42 121.829 5.706 122.341 ;
     RECT  6.552 121.829 9.306 122.369 ;
     RECT  0.324 122.251 0.342 122.429 ;
     RECT  3.42 122.341 5.742 122.429 ;
     RECT  6.552 122.369 8.982 122.513 ;
     RECT  3.708 122.429 5.742 122.611 ;
     RECT  6.552 122.513 8.55 122.611 ;
     RECT  0.108 122.539 0.126 122.669 ;
     RECT  3.708 122.611 8.55 122.981 ;
     RECT  3.924 122.981 8.55 123.089 ;
     RECT  6.264 123.089 8.55 123.101 ;
     RECT  34.815 121.973 43.29 123.421 ;
     RECT  3.924 123.089 5.49 123.449 ;
     RECT  7.092 123.101 8.55 123.629 ;
     RECT  4.392 123.449 5.49 123.719 ;
     RECT  34.2 123.421 43.29 123.863 ;
     RECT  7.092 123.629 8.514 123.899 ;
     RECT  30.78 124.141 30.798 124.259 ;
     RECT  9.648 123.601 9.666 124.349 ;
     RECT  94.215 105.197 94.497 124.681 ;
     RECT  95.976 124.609 95.994 124.681 ;
     RECT  93.384 124.609 93.402 124.771 ;
     RECT  34.815 123.863 43.29 124.807 ;
     RECT  93.384 124.771 93.474 124.807 ;
     RECT  94.215 124.681 95.994 124.829 ;
     RECT  4.392 123.719 5.397 124.871 ;
     RECT  75.315 106.093 75.597 124.915 ;
     RECT  92.88 124.807 93.474 124.951 ;
     RECT  94.215 124.829 95.13 124.951 ;
     RECT  6.264 123.101 6.282 124.979 ;
     RECT  74.268 124.915 74.286 125.069 ;
     RECT  91.515 104.927 91.797 125.149 ;
     RECT  91.515 125.149 92.034 125.221 ;
     RECT  92.88 124.951 95.13 125.221 ;
     RECT  95.904 124.829 95.994 125.339 ;
     RECT  77.256 125.221 77.274 125.383 ;
     RECT  78.015 96.449 78.297 125.383 ;
     RECT  75.06 124.915 75.597 125.491 ;
     RECT  75.024 125.491 75.597 125.725 ;
     RECT  77.256 125.383 78.297 125.761 ;
     RECT  7.128 123.899 8.514 125.789 ;
     RECT  74.124 125.185 74.142 125.887 ;
     RECT  75.024 125.725 75.87 125.887 ;
     RECT  90.324 125.653 90.738 125.887 ;
     RECT  34.776 124.807 43.29 125.915 ;
     RECT  90.108 125.887 90.738 125.915 ;
     RECT  77.256 125.761 78.642 125.951 ;
     RECT  74.124 125.887 75.87 125.995 ;
     RECT  91.515 125.221 95.13 125.995 ;
     RECT  77.256 125.951 78.297 126.031 ;
     RECT  7.815 125.789 8.514 126.059 ;
     RECT  91.08 125.995 95.13 126.139 ;
     RECT  95.868 125.689 95.886 126.139 ;
     RECT  76.824 126.031 78.297 126.149 ;
     RECT  80.715 85.559 80.997 126.157 ;
     RECT  91.08 126.139 95.886 126.221 ;
     RECT  95.868 126.221 95.886 126.283 ;
     RECT  86.115 99.959 86.397 126.427 ;
     RECT  95.868 126.283 96.318 126.491 ;
     RECT  34.815 125.915 43.29 126.535 ;
     RECT  91.08 126.221 94.914 126.599 ;
     RECT  86.076 126.427 86.397 126.661 ;
     RECT  97.488 125.221 97.506 126.715 ;
     RECT  91.08 126.599 94.878 126.761 ;
     RECT  97.452 126.715 97.506 126.761 ;
     RECT  90.108 125.915 90.342 126.805 ;
     RECT  91.08 126.761 94.662 126.805 ;
     RECT  86.076 126.661 86.67 126.833 ;
     RECT  90.108 126.805 94.662 126.833 ;
     RECT  73.836 125.995 75.87 126.841 ;
     RECT  73.836 126.841 75.906 126.931 ;
     RECT  76.896 126.149 78.297 126.931 ;
     RECT  73.836 126.931 76.086 126.959 ;
     RECT  84.924 126.463 84.942 126.959 ;
     RECT  90.324 126.833 94.662 126.959 ;
     RECT  95.868 126.491 95.922 126.959 ;
     RECT  97.488 126.761 97.506 127.003 ;
     RECT  76.896 126.931 78.678 127.031 ;
     RECT  73.836 126.959 73.854 127.051 ;
     RECT  73.8 127.051 73.854 127.103 ;
     RECT  74.736 126.959 76.086 127.111 ;
     RECT  76.896 127.031 78.642 127.111 ;
     RECT  86.076 126.833 86.397 127.139 ;
     RECT  45.615 105.899 45.897 127.187 ;
     RECT  48.315 105.899 48.597 127.187 ;
     RECT  51.015 105.899 51.297 127.187 ;
     RECT  53.715 106.093 53.997 127.187 ;
     RECT  56.415 106.093 56.697 127.187 ;
     RECT  59.115 106.093 59.397 127.187 ;
     RECT  61.815 106.093 62.097 127.187 ;
     RECT  64.515 110.525 64.797 127.187 ;
     RECT  67.215 106.093 67.497 127.187 ;
     RECT  69.915 106.093 70.197 127.187 ;
     RECT  72.615 106.093 72.897 127.187 ;
     RECT  71.676 127.051 71.694 127.229 ;
     RECT  74.736 127.111 78.642 127.229 ;
     RECT  74.808 127.229 78.642 127.265 ;
     RECT  71.352 127.237 71.37 127.277 ;
     RECT  95.868 126.959 95.886 127.291 ;
     RECT  73.8 127.103 73.818 127.325 ;
     RECT  75.024 127.265 78.642 127.337 ;
     RECT  34.815 126.535 43.326 127.381 ;
     RECT  45.615 127.187 45.705 127.457 ;
     RECT  48.315 127.187 48.405 127.457 ;
     RECT  51.015 127.187 51.105 127.457 ;
     RECT  53.715 127.187 53.805 127.457 ;
     RECT  56.415 127.187 56.505 127.457 ;
     RECT  59.115 127.187 59.205 127.457 ;
     RECT  61.815 127.187 61.905 127.457 ;
     RECT  64.515 127.187 64.605 127.457 ;
     RECT  67.215 127.187 67.305 127.457 ;
     RECT  69.915 127.187 70.005 127.457 ;
     RECT  72.615 127.187 72.705 127.457 ;
     RECT  34.815 127.381 43.362 127.499 ;
     RECT  97.488 127.003 97.542 127.607 ;
     RECT  5.115 124.871 5.397 127.675 ;
     RECT  95.76 127.291 95.886 127.741 ;
     RECT  5.115 127.675 6.03 127.769 ;
     RECT  6.804 127.675 6.822 127.769 ;
     RECT  90.324 126.959 90.342 127.849 ;
     RECT  87.804 127.471 87.822 127.949 ;
     RECT  97.488 127.607 97.506 127.949 ;
     RECT  91.188 126.959 94.662 128.011 ;
     RECT  91.188 128.011 94.77 128.047 ;
     RECT  90.072 127.849 90.342 128.083 ;
     RECT  91.188 128.047 94.842 128.083 ;
     RECT  75.024 127.337 78.498 128.317 ;
     RECT  90.072 128.083 94.842 128.345 ;
     RECT  86.115 127.139 86.397 128.389 ;
     RECT  75.024 128.317 78.678 128.417 ;
     RECT  80.064 126.157 80.997 128.461 ;
     RECT  90.324 128.345 94.842 128.461 ;
     RECT  95.76 127.741 95.922 128.461 ;
     RECT  81.792 128.461 81.81 128.579 ;
     RECT  86.115 128.389 86.67 128.579 ;
     RECT  90.324 128.461 95.922 128.579 ;
     RECT  6.84 128.389 6.858 128.587 ;
     RECT  91.332 128.579 95.778 128.615 ;
     RECT  3.528 128.551 3.546 128.621 ;
     RECT  6.372 128.587 6.858 128.623 ;
     RECT  7.815 126.059 8.097 128.623 ;
     RECT  2.415 122.009 2.697 128.659 ;
     RECT  5.115 127.769 5.397 128.731 ;
     RECT  80.064 128.461 81.054 128.731 ;
     RECT  5.115 128.731 5.562 128.821 ;
     RECT  5.115 128.821 5.634 128.827 ;
     RECT  6.372 128.623 8.097 128.827 ;
     RECT  81.864 128.731 81.882 128.857 ;
     RECT  5.115 128.827 8.097 128.885 ;
     RECT  93.276 128.615 95.778 128.885 ;
     RECT  93.276 128.885 95.382 128.957 ;
     RECT  4.356 128.425 4.374 129.001 ;
     RECT  5.115 128.885 5.634 129.001 ;
     RECT  95.364 128.957 95.382 129.029 ;
     RECT  0.108 129.163 0.126 129.211 ;
     RECT  6.372 128.885 8.097 129.271 ;
     RECT  75.024 128.417 78.297 129.271 ;
     RECT  79.488 128.731 81.054 129.271 ;
     RECT  9.396 128.965 9.414 129.389 ;
     RECT  6.372 129.271 8.622 129.541 ;
     RECT  91.515 128.615 92.538 129.541 ;
     RECT  93.276 128.957 94.497 129.541 ;
     RECT  34.815 127.499 43.29 129.6 ;
     RECT  75.024 129.271 81.054 129.6 ;
     RECT  4.356 129.001 5.634 129.631 ;
     RECT  6.372 129.541 9.162 129.631 ;
     RECT  4.356 129.631 9.162 129.787 ;
     RECT  2.304 128.659 2.697 129.811 ;
     RECT  3.42 129.211 3.438 129.811 ;
     RECT  4.32 129.787 9.162 129.811 ;
     RECT  0.108 129.211 0.198 129.839 ;
     RECT  0.18 129.839 0.198 129.917 ;
     RECT  2.304 129.811 9.162 130.037 ;
     RECT  34.815 129.6 81.054 130.081 ;
     RECT  32.115 2.413 32.397 130.207 ;
     RECT  30.78 130.081 30.798 130.379 ;
     RECT  32.115 130.207 33.102 130.379 ;
     RECT  83.415 99.959 83.697 130.459 ;
     RECT  2.304 130.037 8.622 130.469 ;
     RECT  34.704 130.081 81.054 130.469 ;
     RECT  2.304 130.469 3.654 130.493 ;
     RECT  88.815 100.841 89.097 130.555 ;
     RECT  2.304 130.493 3.618 130.649 ;
     RECT  83.415 130.459 84.402 130.649 ;
     RECT  4.644 130.469 8.622 130.739 ;
     RECT  81.864 128.857 82.35 130.747 ;
     RECT  81.864 130.747 82.674 130.843 ;
     RECT  83.415 130.649 83.862 130.843 ;
     RECT  88.815 130.555 89.514 130.919 ;
     RECT  34.815 130.469 81.054 130.981 ;
     RECT  90.324 128.579 90.342 131.017 ;
     RECT  34.815 130.981 81.09 131.021 ;
     RECT  91.515 129.541 94.497 131.053 ;
     RECT  87.768 130.747 87.786 131.083 ;
     RECT  81.864 130.843 83.862 131.117 ;
     RECT  4.644 130.739 8.406 131.153 ;
     RECT  90.252 131.017 90.342 131.165 ;
     RECT  0.108 130.891 0.126 131.179 ;
     RECT  4.644 131.153 6.75 131.189 ;
     RECT  0.108 131.179 0.162 131.309 ;
     RECT  87.228 131.083 87.786 131.309 ;
     RECT  2.415 130.649 3.618 131.431 ;
     RECT  4.644 131.189 6.462 131.521 ;
     RECT  34.815 131.021 81.054 131.521 ;
     RECT  34.776 131.521 81.054 131.549 ;
     RECT  2.415 131.431 3.69 131.585 ;
     RECT  2.415 131.585 3.618 131.611 ;
     RECT  7.74 131.153 8.406 131.629 ;
     RECT  87.228 131.309 87.75 131.645 ;
     RECT  0.108 131.309 0.126 131.657 ;
     RECT  7.74 131.629 8.586 131.701 ;
     RECT  2.304 131.611 3.618 131.755 ;
     RECT  4.572 131.521 6.462 131.791 ;
     RECT  2.268 131.755 3.618 131.819 ;
     RECT  7.74 131.701 8.874 131.819 ;
     RECT  87.228 131.645 87.246 131.819 ;
     RECT  4.464 131.791 6.462 131.837 ;
     RECT  34.776 131.549 79.506 131.837 ;
     RECT  4.572 131.837 6.462 131.891 ;
     RECT  4.824 131.891 6.462 131.935 ;
     RECT  32.115 130.379 32.397 131.935 ;
     RECT  4.824 131.935 6.786 131.971 ;
     RECT  91.515 131.053 94.914 131.971 ;
     RECT  2.304 131.819 3.618 131.999 ;
     RECT  4.824 131.971 6.966 131.999 ;
     RECT  7.815 131.819 8.874 131.999 ;
     RECT  34.776 131.837 75.906 132.061 ;
     RECT  91.44 131.971 94.914 132.061 ;
     RECT  4.896 131.999 6.966 132.125 ;
     RECT  86.115 128.579 86.397 132.235 ;
     RECT  86.115 132.235 86.778 132.413 ;
     RECT  91.224 132.061 94.914 132.413 ;
     RECT  2.415 131.999 3.618 132.431 ;
     RECT  32.115 131.935 33.102 132.431 ;
     RECT  91.44 132.413 94.914 132.629 ;
     RECT  86.115 132.413 86.67 132.637 ;
     RECT  81.864 131.117 83.697 132.701 ;
     RECT  85.968 132.637 86.67 132.797 ;
     RECT  91.44 132.629 92.538 132.809 ;
     RECT  34.2 132.061 75.906 132.871 ;
     RECT  76.644 131.837 79.506 132.871 ;
     RECT  4.932 132.125 6.966 132.899 ;
     RECT  7.815 131.999 8.514 132.899 ;
     RECT  80.715 131.549 81.054 132.941 ;
     RECT  81.864 132.701 81.882 132.989 ;
     RECT  85.968 132.797 86.397 133.277 ;
     RECT  34.2 132.871 79.506 133.469 ;
     RECT  5.04 132.899 6.966 133.889 ;
     RECT  5.04 133.889 5.742 134.051 ;
     RECT  34.2 133.469 75.87 134.365 ;
     RECT  76.644 133.469 79.506 134.365 ;
     RECT  9.684 132.871 9.702 134.429 ;
     RECT  2.415 132.431 3.438 134.663 ;
     RECT  6.948 133.889 6.966 134.699 ;
     RECT  34.2 134.365 79.506 134.717 ;
     RECT  34.2 134.717 75.192 134.969 ;
     RECT  34.815 134.969 75.192 135.005 ;
     RECT  5.115 134.051 5.742 135.239 ;
     RECT  34.815 135.005 42.462 135.329 ;
     RECT  76.32 134.717 79.506 135.389 ;
     RECT  34.815 135.329 35.478 135.629 ;
     RECT  90.252 131.165 90.27 135.643 ;
     RECT  36.648 135.329 42.462 135.677 ;
     RECT  2.415 134.663 3.33 135.779 ;
     RECT  36.864 135.677 42.462 135.977 ;
     RECT  90.252 135.643 90.486 136.171 ;
     RECT  37.368 135.977 42.462 136.253 ;
     RECT  76.356 135.389 79.506 136.253 ;
     RECT  90.144 136.171 90.486 136.319 ;
     RECT  41.94 136.253 42.462 136.349 ;
     RECT  76.932 136.253 79.506 136.637 ;
     RECT  90.144 136.319 90.27 136.637 ;
     RECT  37.368 136.253 41.022 136.679 ;
     RECT  43.2 135.005 75.192 136.687 ;
     RECT  77.58 136.637 79.506 136.733 ;
     RECT  43.2 136.687 75.87 137.065 ;
     RECT  43.2 137.065 76.446 137.309 ;
     RECT  43.2 137.309 76.41 137.405 ;
     RECT  42.192 136.349 42.462 137.461 ;
     RECT  37.515 136.679 41.022 137.605 ;
     RECT  37.515 137.605 41.31 137.641 ;
     RECT  42.156 137.461 42.462 137.641 ;
     RECT  37.515 137.641 42.462 137.693 ;
     RECT  77.616 136.733 79.506 137.755 ;
     RECT  77.58 137.755 79.506 137.795 ;
     RECT  90.252 136.637 90.27 138.541 ;
     RECT  91.44 132.809 92.358 138.541 ;
     RECT  90.252 138.541 90.342 138.569 ;
     RECT  91.44 138.541 92.394 138.685 ;
     RECT  77.616 137.795 79.506 138.713 ;
     RECT  91.44 138.685 92.502 138.721 ;
     RECT  79.488 138.713 79.506 138.749 ;
     RECT  43.2 137.405 75.192 138.811 ;
     RECT  43.092 138.811 75.192 138.907 ;
     RECT  76.392 137.405 76.41 138.941 ;
     RECT  93.816 132.629 94.914 138.949 ;
     RECT  93.6 138.949 94.914 138.955 ;
     RECT  95.724 138.811 95.742 138.955 ;
     RECT  37.515 137.693 42.21 138.991 ;
     RECT  43.056 138.907 75.192 138.991 ;
     RECT  77.616 138.713 78.297 139.003 ;
     RECT  93.6 138.955 94.986 139.081 ;
     RECT  95.724 138.955 95.778 139.081 ;
     RECT  91.44 138.721 92.754 139.147 ;
     RECT  93.6 139.081 95.778 139.147 ;
     RECT  37.515 138.991 75.192 139.189 ;
     RECT  88.815 130.919 89.097 139.261 ;
     RECT  77.436 139.003 78.297 139.291 ;
     RECT  91.44 139.147 95.922 139.381 ;
     RECT  77.4 139.291 78.297 139.415 ;
     RECT  97.452 139.099 97.47 139.451 ;
     RECT  90.324 138.569 90.342 139.621 ;
     RECT  88.815 139.261 89.478 139.649 ;
     RECT  91.08 139.381 95.922 139.661 ;
     RECT  88.815 139.649 89.334 139.675 ;
     RECT  90.216 139.621 90.342 139.693 ;
     RECT  91.08 139.661 93.078 139.693 ;
     RECT  88.776 139.675 89.334 139.709 ;
     RECT  37.515 139.189 75.51 139.765 ;
     RECT  37.515 139.765 75.618 139.963 ;
     RECT  90.216 139.693 93.078 140.045 ;
     RECT  90.216 140.045 92.754 140.071 ;
     RECT  97.488 139.525 97.506 140.395 ;
     RECT  88.776 139.709 89.097 140.611 ;
     RECT  90.18 140.071 92.754 140.611 ;
     RECT  97.452 140.395 97.506 140.717 ;
     RECT  88.776 140.611 92.754 140.729 ;
     RECT  88.815 140.729 92.754 140.881 ;
     RECT  93.816 139.661 95.922 140.881 ;
     RECT  97.452 140.717 97.47 141.071 ;
     RECT  86.115 133.277 86.397 141.115 ;
     RECT  86.115 141.115 86.67 141.269 ;
     RECT  88.815 140.881 95.922 141.269 ;
     RECT  77.436 139.415 78.297 141.809 ;
     RECT  88.815 141.269 92.934 141.809 ;
     RECT  93.816 141.269 95.922 141.809 ;
     RECT  37.515 139.963 76.158 142.051 ;
     RECT  91.224 141.809 92.934 142.051 ;
     RECT  93.816 141.809 95.85 142.051 ;
     RECT  82.836 132.701 83.697 142.619 ;
     RECT  86.115 141.269 86.397 142.627 ;
     RECT  88.815 141.809 90.378 142.627 ;
     RECT  91.224 142.051 95.85 142.627 ;
     RECT  88.815 142.627 95.85 142.699 ;
     RECT  86.115 142.627 86.634 142.799 ;
     RECT  37.515 142.051 76.662 142.889 ;
     RECT  88.815 142.699 95.922 142.889 ;
     RECT  77.472 141.809 78.297 143.195 ;
     RECT  97.452 141.835 97.47 143.231 ;
     RECT  88.815 142.889 95.85 143.429 ;
     RECT  91.224 143.429 95.742 143.465 ;
     RECT  91.224 143.465 95.49 143.501 ;
     RECT  91.224 143.501 95.382 143.609 ;
     RECT  91.224 143.609 92.754 143.699 ;
     RECT  93.6 143.609 95.382 143.741 ;
     RECT  93.6 143.741 94.497 146.443 ;
     RECT  95.364 143.741 95.382 146.443 ;
     RECT  95.256 146.443 95.382 146.471 ;
     RECT  42.444 142.889 76.662 146.904 ;
     RECT  70.704 146.904 70.722 147.197 ;
     RECT  42.444 146.904 43.146 147.245 ;
     RECT  88.815 143.429 90.378 147.245 ;
     RECT  95.256 146.471 95.274 147.245 ;
     RECT  75.168 146.904 76.662 147.677 ;
     RECT  37.515 142.889 41.526 147.749 ;
     RECT  91.224 143.699 92.682 147.749 ;
     RECT  42.516 147.245 43.146 147.785 ;
     RECT  93.528 146.443 94.497 147.785 ;
     RECT  42.552 147.785 43.146 147.821 ;
     RECT  91.224 147.749 92.034 147.821 ;
     RECT  41.364 147.749 41.526 147.857 ;
     RECT  91.224 147.821 91.797 147.857 ;
     RECT  41.364 147.857 41.382 147.893 ;
     RECT  88.815 147.245 90.234 147.893 ;
     RECT  37.515 147.749 40.626 147.929 ;
     RECT  77.796 143.195 78.297 147.929 ;
     RECT  76.068 147.677 76.662 148.469 ;
     RECT  49.752 148.441 49.77 148.486 ;
     RECT  76.644 148.469 76.662 148.514 ;
     RECT  49.752 148.486 50.418 148.873 ;
     RECT  43.056 147.821 43.146 149.023 ;
     RECT  49.752 148.873 50.994 149.023 ;
     RECT  75.168 147.677 75.258 149.023 ;
     RECT  49.752 149.023 51.105 149.099 ;
     RECT  88.815 147.893 89.73 149.099 ;
     RECT  75.168 149.023 75.405 149.135 ;
     RECT  46.764 148.981 46.782 149.171 ;
     RECT  54.684 149.071 54.702 149.279 ;
     RECT  42.915 149.023 43.146 149.293 ;
     RECT  45.615 149.023 45.705 149.293 ;
     RECT  48.315 149.023 48.405 149.293 ;
     RECT  51.015 149.099 51.105 149.293 ;
     RECT  53.715 149.023 53.805 149.293 ;
     RECT  56.415 149.023 56.505 149.293 ;
     RECT  59.115 149.023 59.205 149.293 ;
     RECT  61.815 149.023 61.905 149.293 ;
     RECT  64.515 149.023 64.605 149.293 ;
     RECT  67.215 149.023 67.305 149.293 ;
     RECT  69.915 149.023 70.005 149.293 ;
     RECT  72.615 149.023 72.705 149.293 ;
     RECT  75.24 149.135 75.405 149.293 ;
     RECT  75.24 149.293 75.597 149.369 ;
     RECT  37.515 147.929 40.497 165.641 ;
     RECT  37.515 165.641 39.33 166.793 ;
     RECT  37.515 166.793 39.294 166.963 ;
     RECT  37.008 166.963 39.294 167.021 ;
     RECT  37.515 167.021 39.294 167.189 ;
     RECT  37.515 167.189 39.258 167.459 ;
     RECT  37.515 167.459 39.114 167.531 ;
     RECT  37.515 167.531 39.042 167.837 ;
     RECT  2.415 135.779 2.697 168.227 ;
     RECT  5.115 135.239 5.397 168.227 ;
     RECT  7.815 132.899 8.097 168.227 ;
     RECT  10.515 89.303 10.797 168.227 ;
     RECT  13.215 88.079 13.497 168.227 ;
     RECT  15.915 2.413 16.197 168.227 ;
     RECT  18.615 2.413 18.897 168.227 ;
     RECT  21.315 100.013 21.597 168.227 ;
     RECT  24.015 2.413 24.297 168.227 ;
     RECT  26.715 2.413 26.997 168.227 ;
     RECT  29.415 2.413 29.697 168.227 ;
     RECT  32.115 132.431 32.397 168.227 ;
     RECT  34.815 135.629 35.097 168.227 ;
     RECT  40.215 165.641 40.497 168.227 ;
     RECT  42.915 149.293 43.197 168.227 ;
     RECT  45.615 149.293 45.897 168.227 ;
     RECT  48.315 149.293 48.597 168.227 ;
     RECT  51.015 149.293 51.297 168.227 ;
     RECT  53.715 149.293 53.997 168.227 ;
     RECT  56.415 149.293 56.697 168.227 ;
     RECT  59.115 149.293 59.397 168.227 ;
     RECT  61.815 149.293 62.097 168.227 ;
     RECT  64.515 149.293 64.797 168.227 ;
     RECT  67.215 149.293 67.497 168.227 ;
     RECT  69.915 149.293 70.197 168.227 ;
     RECT  72.615 149.293 72.897 168.227 ;
     RECT  75.315 149.369 75.597 168.227 ;
     RECT  78.015 147.929 78.297 168.227 ;
     RECT  80.715 132.941 80.997 168.227 ;
     RECT  83.415 142.619 83.697 168.227 ;
     RECT  86.115 142.799 86.397 168.227 ;
     RECT  88.815 149.099 89.097 168.227 ;
     RECT  91.515 147.857 91.797 168.227 ;
     RECT  94.215 147.785 94.497 168.227 ;
     RECT  2.415 168.227 2.505 168.497 ;
     RECT  5.115 168.227 5.205 168.497 ;
     RECT  7.815 168.227 7.905 168.497 ;
     RECT  10.515 168.227 10.605 168.497 ;
     RECT  13.215 168.227 13.305 168.497 ;
     RECT  15.915 168.227 16.005 168.497 ;
     RECT  18.615 168.227 18.705 168.497 ;
     RECT  21.315 168.227 21.405 168.497 ;
     RECT  24.015 168.227 24.105 168.497 ;
     RECT  26.715 168.227 26.805 168.497 ;
     RECT  29.415 168.227 29.505 168.497 ;
     RECT  32.115 168.227 32.205 168.497 ;
     RECT  34.815 168.227 34.905 168.497 ;
     RECT  37.515 167.837 39.006 168.497 ;
     RECT  40.215 168.227 40.305 168.497 ;
     RECT  42.915 168.227 43.005 168.497 ;
     RECT  45.615 168.227 45.705 168.497 ;
     RECT  48.315 168.227 48.405 168.497 ;
     RECT  51.015 168.227 51.105 168.497 ;
     RECT  53.715 168.227 53.805 168.497 ;
     RECT  56.415 168.227 56.505 168.497 ;
     RECT  59.115 168.227 59.205 168.497 ;
     RECT  61.815 168.227 61.905 168.497 ;
     RECT  64.515 168.227 64.605 168.497 ;
     RECT  67.215 168.227 67.305 168.497 ;
     RECT  69.915 168.227 70.005 168.497 ;
     RECT  72.615 168.227 72.705 168.497 ;
     RECT  75.315 168.227 75.405 168.497 ;
     RECT  78.015 168.227 78.105 168.497 ;
     RECT  80.715 168.227 80.805 168.497 ;
     RECT  83.415 168.227 83.505 168.497 ;
     RECT  86.115 168.227 86.205 168.497 ;
     RECT  88.815 168.227 88.905 168.497 ;
     RECT  91.515 168.227 91.605 168.497 ;
     RECT  94.215 168.227 94.305 168.497 ;
     RECT  38.052 168.497 39.006 170.347 ;
     RECT  37.836 170.347 39.006 170.603 ;
     RECT  37.836 170.603 37.908 170.609 ;
     RECT  37.926 170.603 38.016 170.609 ;
     RECT  38.034 170.603 38.124 170.609 ;
     RECT  38.142 170.603 38.232 170.609 ;
     RECT  38.25 170.603 38.34 170.609 ;
     RECT  38.358 170.603 38.448 170.609 ;
     RECT  38.466 170.603 38.556 170.609 ;
     RECT  38.574 170.603 38.664 170.609 ;
     RECT  38.682 170.603 38.772 170.609 ;
     RECT  38.79 170.603 38.88 170.609 ;
     RECT  38.898 170.603 38.988 170.609 ;
     RECT  37.926 170.609 38.016 170.621 ;
     RECT  38.034 170.609 38.124 170.621 ;
     RECT  38.142 170.609 38.232 170.621 ;
     RECT  38.25 170.609 38.34 170.621 ;
     RECT  38.358 170.609 38.448 170.621 ;
     RECT  38.466 170.609 38.556 170.621 ;
     RECT  38.574 170.609 38.664 170.621 ;
     RECT  38.682 170.609 38.772 170.621 ;
     RECT  38.79 170.609 38.88 170.621 ;
     RECT  38.898 170.609 38.988 170.621 ;
    LAYER M4 ;
     RECT  0.084 118.08 0.097 118.104 ;
     RECT  0.06 118.104 0.097 118.224 ;
     RECT  0.084 118.224 0.097 118.248 ;
     RECT  0.06 118.248 0.097 118.368 ;
     RECT  0.084 118.368 0.097 118.392 ;
     RECT  0.06 118.392 0.097 118.512 ;
     RECT  0.084 118.512 0.097 118.536 ;
     RECT  0.06 118.536 0.097 118.656 ;
     RECT  0.084 118.656 0.097 118.68 ;
     RECT  0.06 118.68 0.097 118.8 ;
     RECT  0.084 118.8 0.097 118.824 ;
     RECT  0.06 118.824 0.097 118.944 ;
     RECT  0.084 118.944 0.097 118.968 ;
     RECT  0.06 118.968 0.097 119.088 ;
     RECT  0.084 119.088 0.097 119.112 ;
     RECT  0.06 119.112 0.097 119.232 ;
     RECT  0.084 119.232 0.097 119.256 ;
     RECT  0.06 119.256 0.097 119.376 ;
     RECT  0.084 119.376 0.097 119.4 ;
     RECT  0.06 119.4 0.097 119.52 ;
     RECT  0.084 119.52 0.097 119.544 ;
     RECT  0.06 119.544 0.097 119.664 ;
     RECT  0.084 119.664 0.097 119.688 ;
     RECT  0.06 119.688 0.097 119.808 ;
     RECT  0.084 119.808 0.097 119.832 ;
     RECT  0.06 119.832 0.097 119.952 ;
     RECT  0.084 119.952 0.097 119.976 ;
     RECT  0.06 119.976 0.097 120.096 ;
     RECT  0.084 120.096 0.097 120.12 ;
     RECT  0.06 120.12 0.097 120.24 ;
     RECT  0.084 120.24 0.097 120.264 ;
     RECT  0.06 120.264 0.097 120.384 ;
     RECT  0.084 120.384 0.097 120.408 ;
     RECT  0.06 120.408 0.097 120.528 ;
     RECT  0.084 120.528 0.097 120.552 ;
     RECT  0.06 120.552 0.097 120.672 ;
     RECT  0.084 120.672 0.097 120.696 ;
     RECT  0.06 120.696 0.097 120.816 ;
     RECT  0.084 120.816 0.097 120.84 ;
     RECT  0.06 120.84 0.097 120.96 ;
     RECT  0.084 120.96 0.097 120.984 ;
     RECT  0.06 120.984 0.097 121.104 ;
     RECT  0.084 121.104 0.097 121.128 ;
     RECT  0.06 121.128 0.097 121.248 ;
     RECT  0.084 121.248 0.097 121.272 ;
     RECT  0.06 121.272 0.097 121.392 ;
     RECT  0.084 121.392 0.097 121.416 ;
     RECT  0.06 121.416 0.097 121.536 ;
     RECT  0.084 121.536 0.097 121.56 ;
     RECT  0.06 121.56 0.097 121.68 ;
     RECT  0.084 121.68 0.097 121.704 ;
     RECT  0.06 121.704 0.097 121.824 ;
     RECT  0.084 121.824 0.097 121.848 ;
     RECT  0.06 121.848 0.097 121.968 ;
     RECT  0.084 121.968 0.097 121.992 ;
     RECT  0.06 121.992 0.097 122.112 ;
     RECT  0.084 122.112 0.097 122.136 ;
     RECT  0.06 122.136 0.097 122.256 ;
     RECT  0.084 122.256 0.097 122.28 ;
     RECT  0.06 122.28 0.097 122.4 ;
     RECT  0.084 122.4 0.097 122.424 ;
     RECT  0.06 122.424 0.097 122.544 ;
     RECT  0.084 122.544 0.097 122.568 ;
     RECT  0.097 118.08 0.137 122.664 ;
     RECT  0.084 74.304 0.173 74.328 ;
     RECT  0.06 74.328 0.173 74.448 ;
     RECT  0.084 74.448 0.173 74.472 ;
     RECT  0.06 74.472 0.173 74.592 ;
     RECT  0.084 74.592 0.173 74.616 ;
     RECT  0.06 74.616 0.173 74.736 ;
     RECT  0.084 74.736 0.173 74.76 ;
     RECT  0.06 74.76 0.173 74.88 ;
     RECT  0.084 74.88 0.173 74.904 ;
     RECT  0.06 74.904 0.173 75.024 ;
     RECT  0.084 75.024 0.173 75.048 ;
     RECT  0.06 75.048 0.173 75.168 ;
     RECT  0.084 75.168 0.173 75.192 ;
     RECT  0.06 75.192 0.173 75.312 ;
     RECT  0.084 75.312 0.173 75.336 ;
     RECT  0.06 75.336 0.173 75.456 ;
     RECT  0.084 75.456 0.173 75.48 ;
     RECT  0.06 75.48 0.173 75.6 ;
     RECT  0.084 75.6 0.173 75.624 ;
     RECT  0.06 75.624 0.173 75.744 ;
     RECT  0.084 75.744 0.173 75.768 ;
     RECT  0.06 75.768 0.173 75.888 ;
     RECT  0.084 75.888 0.173 75.912 ;
     RECT  0.06 75.912 0.173 76.032 ;
     RECT  0.084 76.032 0.173 76.056 ;
     RECT  0.06 76.056 0.173 76.176 ;
     RECT  0.084 76.176 0.173 76.2 ;
     RECT  0.06 76.2 0.173 76.32 ;
     RECT  0.084 76.32 0.173 76.344 ;
     RECT  0.06 76.344 0.173 76.464 ;
     RECT  0.084 76.464 0.173 76.488 ;
     RECT  0.06 76.488 0.173 76.608 ;
     RECT  0.084 76.608 0.173 76.632 ;
     RECT  0.06 76.632 0.173 76.752 ;
     RECT  0.084 76.752 0.173 76.776 ;
     RECT  0.06 76.776 0.173 76.896 ;
     RECT  0.084 76.896 0.173 76.92 ;
     RECT  0.06 76.92 0.173 77.04 ;
     RECT  0.084 77.04 0.173 77.064 ;
     RECT  0.06 77.064 0.173 77.184 ;
     RECT  0.084 77.184 0.173 77.208 ;
     RECT  0.06 77.208 0.173 77.328 ;
     RECT  0.084 77.328 0.173 77.352 ;
     RECT  0.06 77.352 0.173 77.472 ;
     RECT  0.084 77.472 0.173 77.496 ;
     RECT  0.06 77.496 0.173 77.616 ;
     RECT  0.084 77.616 0.173 77.64 ;
     RECT  0.06 77.64 0.173 77.76 ;
     RECT  0.084 77.76 0.173 77.784 ;
     RECT  0.06 77.784 0.173 77.904 ;
     RECT  0.084 77.904 0.173 77.928 ;
     RECT  0.06 77.928 0.173 78.048 ;
     RECT  0.084 78.048 0.173 78.072 ;
     RECT  0.06 78.072 0.173 78.192 ;
     RECT  0.084 78.192 0.173 78.216 ;
     RECT  0.06 78.216 0.173 78.336 ;
     RECT  0.084 78.336 0.173 78.36 ;
     RECT  0.06 78.36 0.173 78.48 ;
     RECT  0.084 78.48 0.173 78.504 ;
     RECT  0.06 78.504 0.173 78.624 ;
     RECT  0.084 78.624 0.173 78.648 ;
     RECT  0.06 78.648 0.173 78.768 ;
     RECT  0.084 78.768 0.173 78.792 ;
     RECT  0.137 118.224 0.173 122.664 ;
     RECT  0.084 84.672 0.569 84.696 ;
     RECT  0.06 84.696 0.569 84.816 ;
     RECT  0.084 84.816 0.569 84.84 ;
     RECT  0.06 84.84 0.569 84.96 ;
     RECT  0.084 84.96 0.569 84.984 ;
     RECT  0.06 84.984 0.569 85.104 ;
     RECT  0.084 85.104 0.569 85.128 ;
     RECT  0.06 85.128 0.569 85.248 ;
     RECT  0.084 85.248 0.569 85.272 ;
     RECT  0.06 85.272 0.569 85.392 ;
     RECT  0.084 85.392 0.569 85.416 ;
     RECT  0.06 85.416 0.569 85.536 ;
     RECT  0.084 85.536 0.569 85.56 ;
     RECT  0.06 85.56 0.569 85.68 ;
     RECT  0.084 85.68 0.569 85.704 ;
     RECT  0.06 85.704 0.569 85.824 ;
     RECT  0.084 85.824 0.569 85.848 ;
     RECT  0.06 85.848 0.569 85.968 ;
     RECT  0.084 85.968 0.569 85.992 ;
     RECT  0.06 85.992 0.569 86.112 ;
     RECT  0.084 86.112 0.569 86.136 ;
     RECT  0.06 86.136 0.569 86.256 ;
     RECT  0.084 86.256 0.569 86.28 ;
     RECT  0.06 86.28 0.569 86.4 ;
     RECT  0.084 86.4 0.569 86.424 ;
     RECT  0.06 86.424 0.569 86.544 ;
     RECT  0.084 86.544 0.569 86.568 ;
     RECT  0.06 86.568 0.569 86.688 ;
     RECT  0.084 86.688 0.569 86.712 ;
     RECT  0.06 86.712 0.569 86.832 ;
     RECT  0.084 86.832 0.569 86.856 ;
     RECT  0.06 86.856 0.569 86.976 ;
     RECT  0.084 86.976 0.569 87 ;
     RECT  0.06 87 0.569 87.12 ;
     RECT  0.084 87.12 0.569 87.144 ;
     RECT  0.06 87.144 0.569 87.264 ;
     RECT  0.084 87.264 0.569 87.288 ;
     RECT  0.06 87.288 0.569 87.408 ;
     RECT  0.084 87.408 0.569 87.432 ;
     RECT  0.06 87.432 0.569 87.552 ;
     RECT  0.084 87.552 0.569 87.576 ;
     RECT  0.06 87.576 0.569 87.696 ;
     RECT  0.084 87.696 0.569 87.72 ;
     RECT  0.06 87.72 0.569 87.84 ;
     RECT  0.084 87.84 0.569 87.864 ;
     RECT  0.06 87.864 0.569 87.984 ;
     RECT  0.084 87.984 0.569 88.008 ;
     RECT  0.06 88.008 0.569 88.128 ;
     RECT  0.084 88.128 0.569 88.152 ;
     RECT  0.06 88.152 0.569 88.272 ;
     RECT  0.084 88.272 0.569 88.296 ;
     RECT  0.06 88.296 0.569 88.416 ;
     RECT  0.084 88.416 0.569 88.44 ;
     RECT  0.06 88.44 0.569 88.56 ;
     RECT  0.084 88.56 0.569 88.584 ;
     RECT  0.06 88.584 0.569 88.704 ;
     RECT  0.084 88.704 0.569 88.728 ;
     RECT  0.06 88.728 0.569 88.848 ;
     RECT  0.084 88.848 0.569 88.872 ;
     RECT  0.06 88.872 0.569 88.992 ;
     RECT  0.084 88.992 0.569 89.016 ;
     RECT  0.06 89.016 0.569 89.136 ;
     RECT  0.084 89.136 0.569 89.16 ;
     RECT  0.084 31.68 2.252 31.704 ;
     RECT  0.06 31.704 2.252 31.824 ;
     RECT  0.084 31.824 2.252 31.848 ;
     RECT  0.06 31.848 2.252 31.968 ;
     RECT  0.084 31.968 2.252 31.992 ;
     RECT  0.06 31.992 2.252 32.112 ;
     RECT  0.084 32.112 2.252 32.136 ;
     RECT  0.06 32.136 2.252 32.256 ;
     RECT  0.084 32.256 2.252 32.28 ;
     RECT  0.06 32.28 2.252 32.4 ;
     RECT  0.084 32.4 2.252 32.424 ;
     RECT  0.06 32.424 2.252 32.544 ;
     RECT  0.084 32.544 2.252 32.568 ;
     RECT  0.06 32.568 2.252 32.688 ;
     RECT  0.084 32.688 2.252 32.712 ;
     RECT  0.06 32.712 2.252 32.832 ;
     RECT  0.084 32.832 2.252 32.856 ;
     RECT  0.06 32.856 2.252 32.976 ;
     RECT  0.084 32.976 2.252 33 ;
     RECT  0.06 33 2.252 33.12 ;
     RECT  0.084 33.12 2.252 33.144 ;
     RECT  0.06 33.144 2.252 33.264 ;
     RECT  0.084 33.264 2.252 33.288 ;
     RECT  0.06 33.288 2.252 33.408 ;
     RECT  0.084 33.408 2.252 33.432 ;
     RECT  0.06 33.432 2.252 33.552 ;
     RECT  0.084 33.552 2.252 33.576 ;
     RECT  0.06 33.576 2.252 33.696 ;
     RECT  0.084 33.696 2.252 33.72 ;
     RECT  0.06 33.72 2.252 33.84 ;
     RECT  0.084 33.84 2.252 33.864 ;
     RECT  0.06 33.864 2.252 33.984 ;
     RECT  0.084 33.984 2.252 34.008 ;
     RECT  0.06 34.008 2.252 34.128 ;
     RECT  0.084 34.128 2.252 34.152 ;
     RECT  0.06 34.152 2.252 34.272 ;
     RECT  0.084 34.272 2.252 34.296 ;
     RECT  0.06 34.296 2.252 34.416 ;
     RECT  0.084 34.416 2.252 34.44 ;
     RECT  0.06 34.44 2.252 34.56 ;
     RECT  0.084 34.56 2.252 34.584 ;
     RECT  0.06 34.584 2.252 34.704 ;
     RECT  0.084 34.704 2.252 34.728 ;
     RECT  0.06 34.728 2.252 34.848 ;
     RECT  0.084 34.848 2.252 34.872 ;
     RECT  0.06 34.872 2.252 34.992 ;
     RECT  0.084 34.992 2.252 35.016 ;
     RECT  0.06 35.016 2.252 35.136 ;
     RECT  0.084 35.136 2.252 35.16 ;
     RECT  0.06 35.16 2.252 35.28 ;
     RECT  0.084 35.28 2.252 35.304 ;
     RECT  0.06 35.304 2.252 35.424 ;
     RECT  0.084 35.424 2.252 35.448 ;
     RECT  0.06 35.448 2.252 35.568 ;
     RECT  0.084 35.568 2.252 35.592 ;
     RECT  0.06 35.592 2.252 35.712 ;
     RECT  0.084 35.712 2.252 35.736 ;
     RECT  0.06 35.736 2.252 35.856 ;
     RECT  0.084 35.856 2.252 35.88 ;
     RECT  0.06 35.88 2.252 36 ;
     RECT  0.084 36 2.252 36.024 ;
     RECT  0.06 36.024 2.252 36.144 ;
     RECT  0.084 36.144 2.252 36.168 ;
     RECT  2.252 31.68 2.408 36.264 ;
     RECT  0.084 40.896 2.408 40.92 ;
     RECT  0.06 40.92 2.408 41.04 ;
     RECT  0.084 41.04 2.408 41.064 ;
     RECT  0.06 41.064 2.408 41.184 ;
     RECT  0.084 41.184 2.408 41.208 ;
     RECT  0.06 41.208 2.408 41.328 ;
     RECT  0.084 41.328 2.408 41.352 ;
     RECT  0.06 41.352 2.408 41.472 ;
     RECT  0.084 41.472 2.408 41.496 ;
     RECT  0.06 41.496 2.408 41.616 ;
     RECT  0.084 41.616 2.408 41.64 ;
     RECT  0.06 41.64 2.408 41.76 ;
     RECT  0.084 41.76 2.408 41.784 ;
     RECT  0.06 41.784 2.408 41.904 ;
     RECT  0.084 41.904 2.408 41.928 ;
     RECT  0.06 41.928 2.408 42.048 ;
     RECT  0.084 42.048 2.408 42.072 ;
     RECT  0.06 42.072 2.408 42.192 ;
     RECT  0.084 42.192 2.408 42.216 ;
     RECT  0.06 42.216 2.408 42.336 ;
     RECT  0.084 42.336 2.408 42.36 ;
     RECT  0.06 42.36 2.408 42.48 ;
     RECT  0.084 42.48 2.408 42.504 ;
     RECT  0.06 42.504 2.408 42.624 ;
     RECT  0.084 42.624 2.408 42.648 ;
     RECT  0.06 42.648 2.408 42.768 ;
     RECT  0.084 42.768 2.408 42.792 ;
     RECT  0.06 42.792 2.408 42.912 ;
     RECT  0.084 42.912 2.408 42.936 ;
     RECT  0.06 42.936 2.408 43.056 ;
     RECT  0.084 43.056 2.408 43.08 ;
     RECT  0.06 43.08 2.408 43.2 ;
     RECT  0.084 43.2 2.408 43.224 ;
     RECT  0.06 43.224 2.408 43.344 ;
     RECT  0.084 43.344 2.408 43.368 ;
     RECT  0.06 43.368 2.408 43.488 ;
     RECT  0.084 43.488 2.408 43.512 ;
     RECT  0.06 43.512 2.408 43.632 ;
     RECT  0.084 43.632 2.408 43.656 ;
     RECT  0.06 43.656 2.408 43.776 ;
     RECT  0.084 43.776 2.408 43.8 ;
     RECT  0.06 43.8 2.408 43.92 ;
     RECT  0.084 43.92 2.408 43.944 ;
     RECT  0.06 43.944 2.408 44.064 ;
     RECT  0.084 44.064 2.408 44.088 ;
     RECT  0.06 44.088 2.408 44.208 ;
     RECT  0.084 44.208 2.408 44.232 ;
     RECT  0.06 44.232 2.408 44.352 ;
     RECT  0.084 44.352 2.408 44.376 ;
     RECT  0.06 44.376 2.408 44.496 ;
     RECT  0.084 44.496 2.408 44.52 ;
     RECT  0.06 44.52 2.408 44.64 ;
     RECT  0.084 44.64 2.408 44.664 ;
     RECT  0.06 44.664 2.408 44.784 ;
     RECT  0.084 44.784 2.408 44.808 ;
     RECT  0.06 44.808 2.408 44.928 ;
     RECT  0.084 44.928 2.408 44.952 ;
     RECT  0.06 44.952 2.408 45.072 ;
     RECT  0.084 45.072 2.408 45.096 ;
     RECT  0.06 45.096 2.408 45.216 ;
     RECT  0.084 45.216 2.408 45.24 ;
     RECT  0.06 45.24 2.408 45.36 ;
     RECT  0.084 45.36 2.408 45.384 ;
     RECT  0.173 74.304 2.408 78.696 ;
     RECT  0.569 84.912 2.408 89.16 ;
     RECT  0.173 118.368 2.408 122.664 ;
     RECT  0.084 128.592 2.408 128.616 ;
     RECT  0.06 128.616 2.408 128.736 ;
     RECT  0.084 128.736 2.408 128.76 ;
     RECT  0.06 128.76 2.408 128.88 ;
     RECT  0.084 128.88 2.408 128.904 ;
     RECT  0.06 128.904 2.408 129.024 ;
     RECT  0.084 129.024 2.408 129.048 ;
     RECT  0.06 129.048 2.408 129.168 ;
     RECT  0.084 129.168 2.408 129.192 ;
     RECT  0.06 129.192 2.408 129.312 ;
     RECT  0.084 129.312 2.408 129.336 ;
     RECT  0.06 129.336 2.408 129.456 ;
     RECT  0.084 129.456 2.408 129.48 ;
     RECT  0.06 129.48 2.408 129.6 ;
     RECT  0.084 129.6 2.408 129.624 ;
     RECT  0.06 129.624 2.408 129.744 ;
     RECT  0.084 129.744 2.408 129.768 ;
     RECT  0.06 129.768 2.408 129.888 ;
     RECT  0.084 129.888 2.408 129.912 ;
     RECT  0.06 129.912 2.408 130.032 ;
     RECT  0.084 130.032 2.408 130.056 ;
     RECT  0.06 130.056 2.408 130.176 ;
     RECT  0.084 130.176 2.408 130.2 ;
     RECT  0.06 130.2 2.408 130.32 ;
     RECT  0.084 130.32 2.408 130.344 ;
     RECT  0.06 130.344 2.408 130.464 ;
     RECT  0.084 130.464 2.408 130.488 ;
     RECT  0.06 130.488 2.408 130.608 ;
     RECT  0.084 130.608 2.408 130.632 ;
     RECT  0.06 130.632 2.408 130.752 ;
     RECT  0.084 130.752 2.408 130.776 ;
     RECT  0.06 130.776 2.408 130.896 ;
     RECT  0.084 130.896 2.408 130.92 ;
     RECT  0.06 130.92 2.408 131.04 ;
     RECT  0.084 131.04 2.408 131.064 ;
     RECT  0.06 131.064 2.408 131.184 ;
     RECT  0.084 131.184 2.408 131.208 ;
     RECT  0.06 131.208 2.408 131.328 ;
     RECT  0.084 131.328 2.408 131.352 ;
     RECT  0.06 131.352 2.408 131.472 ;
     RECT  0.084 131.472 2.408 131.496 ;
     RECT  0.06 131.496 2.408 131.616 ;
     RECT  0.084 131.616 2.408 131.64 ;
     RECT  0.06 131.64 2.408 131.76 ;
     RECT  0.084 131.76 2.408 131.784 ;
     RECT  2.408 2.148 2.512 168.492 ;
     RECT  2.512 2.418 2.704 168.222 ;
     RECT  2.704 74.304 3.449 78.792 ;
     RECT  2.704 84.912 3.449 89.16 ;
     RECT  2.704 31.68 3.557 36.12 ;
     RECT  2.704 128.592 3.557 131.832 ;
     RECT  3.449 74.448 4.025 78.792 ;
     RECT  2.704 40.896 4.165 45.576 ;
     RECT  4.165 40.416 4.46 45.576 ;
     RECT  3.557 31.968 4.501 36.12 ;
     RECT  2.704 118.368 4.501 122.664 ;
     RECT  4.489 80.064 4.837 80.088 ;
     RECT  4.501 31.968 5.108 36.168 ;
     RECT  4.46 39.984 5.108 45.576 ;
     RECT  4.025 74.64 5.108 78.792 ;
     RECT  4.837 80.064 5.108 80.184 ;
     RECT  4.669 81.168 5.108 81.192 ;
     RECT  3.449 84.96 5.108 89.16 ;
     RECT  4.501 118.368 5.108 123.384 ;
     RECT  3.557 128.88 5.108 131.832 ;
     RECT  5.108 2.148 5.212 168.492 ;
     RECT  5.212 2.418 5.404 168.222 ;
     RECT  5.404 118.608 5.465 119.736 ;
     RECT  5.404 122.64 5.465 123.096 ;
     RECT  5.404 41.76 5.501 44.664 ;
     RECT  5.501 43.056 5.609 44.664 ;
     RECT  5.404 32.304 5.645 36.024 ;
     RECT  5.404 84.96 5.645 85.704 ;
     RECT  5.404 131.28 5.645 131.976 ;
     RECT  5.645 35.424 5.681 36.024 ;
     RECT  5.645 85.68 5.681 85.704 ;
     RECT  5.404 88.992 5.681 89.016 ;
     RECT  5.501 41.76 5.717 41.928 ;
     RECT  5.404 74.64 5.717 74.664 ;
     RECT  5.645 32.304 5.753 34.44 ;
     RECT  5.753 33.024 5.789 34.44 ;
     RECT  5.404 75.792 5.789 78.744 ;
     RECT  5.465 118.608 5.789 119.688 ;
     RECT  5.789 118.608 5.825 119.016 ;
     RECT  5.789 75.792 5.897 78.216 ;
     RECT  5.404 87.216 5.933 87.912 ;
     RECT  5.897 75.792 6.005 77.592 ;
     RECT  5.404 80.064 6.275 80.088 ;
     RECT  5.404 128.832 6.323 130.056 ;
     RECT  5.681 35.568 6.397 36.024 ;
     RECT  6.323 129.648 6.541 130.056 ;
     RECT  5.825 118.608 6.572 118.92 ;
     RECT  6.572 118.512 6.659 118.92 ;
     RECT  5.933 87.216 6.685 87.288 ;
     RECT  6.541 129.648 6.725 130.584 ;
     RECT  6.685 86.736 6.793 87.288 ;
     RECT  5.645 131.952 6.797 131.976 ;
     RECT  5.404 40.416 6.805 40.44 ;
     RECT  5.717 41.76 6.805 41.784 ;
     RECT  5.465 123.072 6.829 123.096 ;
     RECT  5.789 33.024 6.833 33.048 ;
     RECT  6.793 85.872 6.833 87.288 ;
     RECT  6.829 122.976 6.86 123.096 ;
     RECT  6.833 85.872 7.009 85.896 ;
     RECT  5.609 43.056 7.073 43.704 ;
     RECT  6.833 87.264 7.441 87.288 ;
     RECT  6.937 31.872 7.808 31.896 ;
     RECT  5.789 34.08 7.808 34.44 ;
     RECT  6.397 35.568 7.808 37.032 ;
     RECT  6.805 40.416 7.808 41.784 ;
     RECT  7.073 43.056 7.808 44.472 ;
     RECT  7.117 74.976 7.808 75 ;
     RECT  6.005 76.368 7.808 77.592 ;
     RECT  6.901 78.912 7.808 78.936 ;
     RECT  5.404 81.168 7.808 81.192 ;
     RECT  7.009 85.392 7.808 85.896 ;
     RECT  7.441 87.264 7.808 87.672 ;
     RECT  6.659 118.896 7.808 118.92 ;
     RECT  5.404 120.816 7.808 120.84 ;
     RECT  6.86 122.496 7.808 123.096 ;
     RECT  5.404 127.68 7.808 127.704 ;
     RECT  6.725 129.648 7.808 129.672 ;
     RECT  7.808 2.148 7.912 168.492 ;
     RECT  7.912 2.418 8.104 168.222 ;
     RECT  8.104 74.976 8.165 75 ;
     RECT  8.104 78.912 8.165 78.936 ;
     RECT  8.104 33.504 8.201 34.44 ;
     RECT  8.104 85.392 8.201 85.416 ;
     RECT  8.104 87.648 8.201 87.672 ;
     RECT  8.104 43.056 8.237 43.272 ;
     RECT  8.104 36.672 8.291 36.696 ;
     RECT  8.104 122.832 8.291 123 ;
     RECT  8.104 124.272 8.309 124.824 ;
     RECT  8.104 35.568 8.332 35.592 ;
     RECT  8.309 124.8 8.339 124.824 ;
     RECT  8.104 130.848 8.339 130.872 ;
     RECT  8.104 40.848 8.381 42.024 ;
     RECT  8.104 118.896 8.381 119.688 ;
     RECT  8.291 122.832 8.4 122.856 ;
     RECT  8.201 33.504 8.489 33.528 ;
     RECT  8.237 43.248 8.489 43.272 ;
     RECT  8.104 129.408 8.489 129.432 ;
     RECT  8.104 76.896 8.641 77.592 ;
     RECT  8.381 40.848 10.508 40.872 ;
     RECT  8.381 42 10.508 42.024 ;
     RECT  8.641 77.568 10.508 77.592 ;
     RECT  8.104 81.168 10.508 81.192 ;
     RECT  8.104 89.424 10.508 89.448 ;
     RECT  8.381 119.664 10.508 119.688 ;
     RECT  9.637 124.32 10.508 124.344 ;
     RECT  10.508 2.148 10.612 168.492 ;
     RECT  10.612 2.418 10.804 168.222 ;
     RECT  10.804 42 10.829 42.168 ;
     RECT  10.804 40.848 12.14 40.872 ;
     RECT  12.14 40.848 12.197 41.016 ;
     RECT  12.197 40.992 12.227 41.016 ;
     RECT  10.804 77.568 12.227 77.592 ;
     RECT  10.829 42.144 12.229 42.168 ;
     RECT  12.229 41.568 13.208 42.168 ;
     RECT  12.229 46.512 13.208 46.536 ;
     RECT  12.181 74.688 13.208 74.712 ;
     RECT  10.804 81.168 13.208 81.192 ;
     RECT  10.804 89.424 13.208 89.448 ;
     RECT  10.804 119.664 13.208 119.688 ;
     RECT  10.804 124.32 13.208 124.344 ;
     RECT  13.208 2.148 13.312 168.492 ;
     RECT  13.312 2.418 13.504 168.222 ;
     RECT  13.504 74.688 13.853 74.904 ;
     RECT  13.504 46.512 15.908 46.536 ;
     RECT  13.853 74.88 15.908 74.904 ;
     RECT  13.504 81.168 15.908 81.192 ;
     RECT  13.504 89.424 15.908 89.448 ;
     RECT  13.504 119.664 15.908 119.688 ;
     RECT  13.504 124.32 15.908 124.344 ;
     RECT  15.908 2.148 16.012 168.492 ;
     RECT  16.012 2.418 16.204 168.222 ;
     RECT  16.204 46.512 18.608 46.536 ;
     RECT  16.204 74.88 18.608 74.904 ;
     RECT  16.204 81.168 18.608 81.192 ;
     RECT  16.204 89.424 18.608 89.448 ;
     RECT  16.204 119.664 18.608 119.688 ;
     RECT  16.204 124.32 18.608 124.344 ;
     RECT  18.608 2.148 18.712 168.492 ;
     RECT  18.712 2.418 18.904 168.222 ;
     RECT  18.904 46.512 21.308 46.536 ;
     RECT  18.904 74.88 21.308 74.904 ;
     RECT  18.904 81.168 21.308 81.192 ;
     RECT  18.904 89.424 21.308 89.448 ;
     RECT  18.904 119.664 21.308 119.688 ;
     RECT  18.904 124.32 21.308 124.344 ;
     RECT  21.308 2.148 21.412 168.492 ;
     RECT  21.412 2.418 21.604 168.222 ;
     RECT  21.604 93.168 22.163 93.336 ;
     RECT  21.604 99.84 22.385 100.008 ;
     RECT  21.604 74.88 22.499 74.904 ;
     RECT  22.163 93.168 22.499 93.192 ;
     RECT  21.604 119.136 22.673 119.688 ;
     RECT  21.604 46.512 24.008 46.536 ;
     RECT  21.604 81.168 24.008 81.192 ;
     RECT  21.604 89.424 24.008 89.448 ;
     RECT  22.385 99.984 24.008 100.008 ;
     RECT  22.673 119.664 24.008 119.688 ;
     RECT  21.604 124.32 24.008 124.344 ;
     RECT  24.008 2.148 24.112 168.492 ;
     RECT  24.112 2.418 24.304 168.222 ;
     RECT  24.304 46.512 26.708 46.536 ;
     RECT  24.304 81.168 26.708 81.192 ;
     RECT  24.304 89.424 26.708 89.448 ;
     RECT  24.304 99.984 26.708 100.008 ;
     RECT  24.304 119.664 26.708 119.688 ;
     RECT  24.304 124.32 26.708 124.344 ;
     RECT  26.708 2.148 26.812 168.492 ;
     RECT  26.812 2.418 27.004 168.222 ;
     RECT  27.004 46.512 29.408 46.536 ;
     RECT  27.004 81.168 29.408 81.192 ;
     RECT  27.004 89.424 29.408 89.448 ;
     RECT  27.004 99.984 29.408 100.008 ;
     RECT  27.004 119.664 29.408 119.688 ;
     RECT  27.004 124.32 29.408 124.344 ;
     RECT  29.408 2.148 29.512 168.492 ;
     RECT  29.512 2.418 29.704 168.222 ;
     RECT  29.704 46.512 32.108 46.536 ;
     RECT  29.704 81.168 32.108 81.192 ;
     RECT  29.704 89.424 32.108 89.448 ;
     RECT  29.704 99.984 32.108 100.008 ;
     RECT  29.704 119.664 32.108 119.688 ;
     RECT  29.704 124.32 32.108 124.344 ;
     RECT  32.108 2.148 32.212 168.492 ;
     RECT  32.212 2.418 32.404 168.222 ;
     RECT  32.404 124.32 34.801 124.344 ;
     RECT  32.404 46.512 34.808 46.536 ;
     RECT  32.404 81.168 34.808 81.192 ;
     RECT  32.404 89.424 34.808 89.448 ;
     RECT  32.404 99.984 34.808 100.008 ;
     RECT  32.404 119.664 34.808 119.688 ;
     RECT  34.801 124.32 34.808 124.872 ;
     RECT  34.765 131.568 34.808 131.976 ;
     RECT  34.808 2.148 34.912 168.492 ;
     RECT  34.912 2.418 35.104 168.222 ;
     RECT  35.104 121.152 35.219 121.176 ;
     RECT  35.104 117.936 35.459 119.736 ;
     RECT  35.459 117.936 35.669 118.536 ;
     RECT  35.104 122.208 36.092 122.232 ;
     RECT  35.104 124.32 36.133 124.872 ;
     RECT  35.104 130.944 36.179 132.792 ;
     RECT  36.092 122.208 36.277 122.472 ;
     RECT  36.133 123.744 36.493 124.872 ;
     RECT  36.493 123.744 36.572 125.448 ;
     RECT  36.277 121.872 36.601 122.472 ;
     RECT  36.572 123.744 36.601 126.408 ;
     RECT  36.601 121.872 36.637 126.408 ;
     RECT  35.104 127.632 36.637 127.656 ;
     RECT  35.104 135.072 36.637 135.624 ;
     RECT  35.459 119.664 36.745 119.736 ;
     RECT  36.179 131.04 36.901 132.792 ;
     RECT  36.529 133.968 36.901 133.992 ;
     RECT  35.104 129.216 36.997 129.288 ;
     RECT  35.669 117.936 37.177 117.96 ;
     RECT  36.997 129.216 37.321 130.008 ;
     RECT  36.637 135.072 37.357 135.672 ;
     RECT  37.177 117.936 37.465 118.44 ;
     RECT  35.104 46.512 37.508 46.536 ;
     RECT  35.104 81.168 37.508 81.192 ;
     RECT  35.104 89.424 37.508 89.448 ;
     RECT  35.104 99.984 37.508 100.008 ;
     RECT  36.133 110.496 37.508 110.52 ;
     RECT  37.465 117.504 37.508 118.44 ;
     RECT  36.745 119.664 37.508 120.264 ;
     RECT  36.637 121.872 37.508 127.656 ;
     RECT  37.321 128.784 37.508 130.008 ;
     RECT  36.901 131.04 37.508 133.992 ;
     RECT  37.357 135.072 37.508 136.248 ;
     RECT  35.104 138.576 37.508 138.6 ;
     RECT  36.997 166.992 37.508 167.016 ;
     RECT  37.508 2.148 37.612 168.492 ;
     RECT  37.612 2.418 37.804 168.222 ;
     RECT  37.825 170.352 37.957 170.376 ;
     RECT  37.804 119.664 37.973 120.264 ;
     RECT  37.804 141.216 37.981 144.072 ;
     RECT  37.804 132.72 38.009 133.944 ;
     RECT  37.804 138.192 38.009 138.6 ;
     RECT  37.957 170.352 38.044 170.52 ;
     RECT  37.804 117.504 38.045 118.44 ;
     RECT  37.804 99.984 38.051 100.008 ;
     RECT  38.044 170.352 38.153 170.472 ;
     RECT  37.804 104.304 38.195 105 ;
     RECT  38.045 117.504 38.195 117.528 ;
     RECT  37.804 121.968 38.225 123.048 ;
     RECT  37.804 128.016 38.243 131.4 ;
     RECT  37.804 148.8 38.269 149.88 ;
     RECT  37.981 142.176 38.297 144.072 ;
     RECT  38.243 130.512 38.369 131.4 ;
     RECT  37.804 164.976 38.369 165 ;
     RECT  37.804 166.416 38.441 167.208 ;
     RECT  38.297 142.8 38.579 144.072 ;
     RECT  38.269 148.8 38.62 149.064 ;
     RECT  37.804 50.64 38.675 50.664 ;
     RECT  37.804 163.68 38.765 163.704 ;
     RECT  37.804 52.8 38.771 53.976 ;
     RECT  37.804 55.44 38.771 55.464 ;
     RECT  37.804 135.072 38.801 136.248 ;
     RECT  38.441 166.992 38.801 167.208 ;
     RECT  37.804 51.744 38.828 51.768 ;
     RECT  38.369 130.512 38.867 131.304 ;
     RECT  38.579 143.28 38.873 144.072 ;
     RECT  37.804 93.072 38.941 93.096 ;
     RECT  38.009 138.576 38.941 138.6 ;
     RECT  38.225 122.16 38.977 123.048 ;
     RECT  37.804 124.32 38.977 125.784 ;
     RECT  38.009 133.248 38.981 133.944 ;
     RECT  38.771 53.952 39.017 53.976 ;
     RECT  37.973 119.664 39.059 119.688 ;
     RECT  38.941 138.576 39.089 138.648 ;
     RECT  38.62 148.8 39.107 148.824 ;
     RECT  39.085 90.528 39.157 90.552 ;
     RECT  38.243 128.016 39.197 129.384 ;
     RECT  39.089 138.576 39.197 138.6 ;
     RECT  39.157 50.112 39.265 50.376 ;
     RECT  37.804 95.712 39.349 95.736 ;
     RECT  37.804 96.864 39.349 96.888 ;
     RECT  39.049 48.912 39.373 48.936 ;
     RECT  37.804 89.424 39.373 89.448 ;
     RECT  39.157 90.528 39.373 90.6 ;
     RECT  38.867 130.512 39.373 130.536 ;
     RECT  37.804 140.016 39.409 140.04 ;
     RECT  37.804 91.968 39.445 91.992 ;
     RECT  38.153 170.448 39.491 170.472 ;
     RECT  39.373 89.424 39.589 90.6 ;
     RECT  39.445 91.632 39.589 91.992 ;
     RECT  38.941 93.072 39.589 93.768 ;
     RECT  39.229 120.24 39.589 120.264 ;
     RECT  38.977 122.16 39.589 125.784 ;
     RECT  39.589 121.968 39.625 125.784 ;
     RECT  39.589 89.424 39.661 93.768 ;
     RECT  39.661 88.896 39.697 93.768 ;
     RECT  39.625 121.968 39.733 125.88 ;
     RECT  39.197 128.016 39.733 128.472 ;
     RECT  39.733 121.968 39.769 126.12 ;
     RECT  39.733 127.104 39.769 128.472 ;
     RECT  39.265 50.016 39.805 50.376 ;
     RECT  38.828 51.552 39.805 51.768 ;
     RECT  39.697 88.176 39.841 93.768 ;
     RECT  39.013 108.768 40.021 108.792 ;
     RECT  39.373 129.984 40.021 130.536 ;
     RECT  39.373 48.48 40.057 48.936 ;
     RECT  39.805 50.016 40.057 51.768 ;
     RECT  38.981 133.248 40.093 133.896 ;
     RECT  38.801 135.072 40.093 135.096 ;
     RECT  37.804 46.512 40.208 46.536 ;
     RECT  40.057 48.48 40.208 51.768 ;
     RECT  38.771 52.8 40.208 52.824 ;
     RECT  38.869 60.672 40.208 60.696 ;
     RECT  37.804 81.168 40.208 81.192 ;
     RECT  39.841 88.176 40.208 93.816 ;
     RECT  39.349 94.992 40.208 96.888 ;
     RECT  38.195 104.304 40.208 104.328 ;
     RECT  39.445 105.936 40.208 105.96 ;
     RECT  40.021 108.432 40.208 108.792 ;
     RECT  37.804 110.496 40.208 110.52 ;
     RECT  39.589 120.24 40.208 120.84 ;
     RECT  39.769 121.968 40.208 128.472 ;
     RECT  40.021 129.984 40.208 130.584 ;
     RECT  39.373 132.144 40.208 132.168 ;
     RECT  40.093 133.248 40.208 135.096 ;
     RECT  38.905 136.752 40.208 136.776 ;
     RECT  39.409 139.632 40.208 140.04 ;
     RECT  39.489 141.696 40.208 141.72 ;
     RECT  38.873 143.28 40.208 143.592 ;
     RECT  38.801 166.992 40.208 167.016 ;
     RECT  40.208 2.148 40.312 168.492 ;
     RECT  40.312 2.418 40.504 168.222 ;
     RECT  40.504 81.168 40.643 81.192 ;
     RECT  40.504 123.84 40.673 126.552 ;
     RECT  40.504 108.96 40.883 108.984 ;
     RECT  40.504 143.088 40.883 143.16 ;
     RECT  40.504 110.496 40.889 111.048 ;
     RECT  40.504 52.128 40.931 55.272 ;
     RECT  40.504 56.4 40.979 56.424 ;
     RECT  40.673 123.84 40.997 126.504 ;
     RECT  40.931 55.248 41.027 55.272 ;
     RECT  40.883 143.088 41.068 143.112 ;
     RECT  40.504 122.4 41.177 122.568 ;
     RECT  40.997 125.856 41.285 126.504 ;
     RECT  40.504 114.528 41.465 114.936 ;
     RECT  40.504 120.48 41.465 120.504 ;
     RECT  40.504 47.664 41.497 50.904 ;
     RECT  40.931 52.128 41.497 53.784 ;
     RECT  41.285 125.856 41.5 125.88 ;
     RECT  41.465 114.528 41.501 114.6 ;
     RECT  40.504 45.408 41.533 46.392 ;
     RECT  41.533 45.216 41.569 46.392 ;
     RECT  41.497 47.664 41.569 53.784 ;
     RECT  40.504 131.328 41.569 132.216 ;
     RECT  40.504 87.936 41.605 94.008 ;
     RECT  40.504 95.136 41.605 96.984 ;
     RECT  40.504 44.16 41.641 44.184 ;
     RECT  41.569 45.216 41.641 53.784 ;
     RECT  41.569 131.136 41.677 132.216 ;
     RECT  40.504 137.376 41.713 138.216 ;
     RECT  41.677 131.136 41.749 132.408 ;
     RECT  41.713 137.376 41.749 138.36 ;
     RECT  40.504 139.584 41.749 140.184 ;
     RECT  40.504 134.304 41.821 136.248 ;
     RECT  41.501 114.576 41.833 114.6 ;
     RECT  41.749 131.136 41.929 132.792 ;
     RECT  41.821 133.824 41.929 136.248 ;
     RECT  41.929 131.136 42.073 136.344 ;
     RECT  41.605 87.936 42.109 96.984 ;
     RECT  42.073 130.848 42.109 136.344 ;
     RECT  42.109 130.752 42.181 136.344 ;
     RECT  41.749 137.376 42.181 140.184 ;
     RECT  41.749 84.192 42.325 84.216 ;
     RECT  42.109 87.36 42.325 96.984 ;
     RECT  40.997 123.84 42.325 124.344 ;
     RECT  42.325 126.336 42.397 126.36 ;
     RECT  42.253 38.256 42.469 38.28 ;
     RECT  42.397 126.336 42.469 126.504 ;
     RECT  42.469 38.208 42.505 38.28 ;
     RECT  42.469 126.336 42.541 126.6 ;
     RECT  42.325 83.76 42.565 84.216 ;
     RECT  42.421 107.28 42.565 107.304 ;
     RECT  42.565 107.28 42.613 107.832 ;
     RECT  42.565 128.832 42.613 128.856 ;
     RECT  42.181 130.752 42.613 140.184 ;
     RECT  41.641 44.16 42.661 53.784 ;
     RECT  42.613 64.416 42.661 64.536 ;
     RECT  42.613 128.208 42.689 128.856 ;
     RECT  42.325 86.688 42.757 96.984 ;
     RECT  42.541 126.336 42.793 126.744 ;
     RECT  42.793 126.336 42.865 127.032 ;
     RECT  42.689 128.208 42.865 128.232 ;
     RECT  42.865 126.336 42.869 128.232 ;
     RECT  42.505 38.208 42.908 38.808 ;
     RECT  42.661 64.416 42.908 64.92 ;
     RECT  42.565 83.568 42.908 84.216 ;
     RECT  40.504 105.936 42.908 105.96 ;
     RECT  42.613 107.28 42.908 108.648 ;
     RECT  40.889 110.496 42.908 110.52 ;
     RECT  42.693 114 42.908 114.024 ;
     RECT  42.373 121.44 42.908 121.464 ;
     RECT  41.177 122.544 42.908 122.568 ;
     RECT  42.325 123.696 42.908 125.304 ;
     RECT  42.869 126.336 42.908 127.452 ;
     RECT  40.504 166.992 42.908 167.016 ;
     RECT  42.908 2.148 43.012 41.052 ;
     RECT  42.908 62.628 43.012 84.252 ;
     RECT  42.908 105.828 43.012 127.452 ;
     RECT  42.908 149.028 43.012 168.492 ;
     RECT  42.613 130.368 43.081 140.184 ;
     RECT  42.757 86.064 43.121 96.984 ;
     RECT  43.012 2.418 43.204 40.782 ;
     RECT  43.012 62.898 43.204 84.12 ;
     RECT  43.012 105.936 43.204 127.182 ;
     RECT  43.012 149.298 43.204 168.222 ;
     RECT  43.204 107.28 43.265 108.648 ;
     RECT  42.661 43.968 43.272 53.784 ;
     RECT  40.504 60.576 43.272 61.656 ;
     RECT  43.121 86.256 43.272 96.984 ;
     RECT  40.504 104.304 43.272 104.328 ;
     RECT  43.081 129.456 43.272 140.184 ;
     RECT  40.504 147.072 43.272 147.672 ;
     RECT  43.272 86.256 43.331 104.328 ;
     RECT  43.272 129.456 43.331 147.672 ;
     RECT  43.204 64.608 43.372 64.968 ;
     RECT  43.265 107.952 43.409 108.648 ;
     RECT  43.372 64.608 43.553 64.728 ;
     RECT  43.204 83.568 43.553 84.12 ;
     RECT  43.553 83.568 43.625 83.592 ;
     RECT  43.204 105.936 45.608 105.96 ;
     RECT  43.204 110.496 45.608 110.52 ;
     RECT  43.204 166.992 45.608 167.016 ;
     RECT  45.608 2.148 45.712 41.052 ;
     RECT  45.608 62.628 45.712 84.252 ;
     RECT  45.608 105.828 45.712 127.452 ;
     RECT  45.608 149.028 45.712 168.492 ;
     RECT  45.712 2.418 45.904 40.782 ;
     RECT  45.712 62.898 45.904 83.982 ;
     RECT  45.712 105.936 45.904 127.182 ;
     RECT  45.712 149.298 45.904 168.222 ;
     RECT  45.904 105.936 48.308 105.96 ;
     RECT  45.904 110.496 48.308 110.52 ;
     RECT  45.904 166.992 48.308 167.016 ;
     RECT  48.308 2.148 48.412 41.052 ;
     RECT  48.308 62.628 48.412 84.252 ;
     RECT  48.308 105.828 48.412 127.452 ;
     RECT  48.308 149.028 48.412 168.492 ;
     RECT  48.412 2.418 48.604 40.782 ;
     RECT  48.412 62.898 48.604 83.982 ;
     RECT  48.412 105.936 48.604 127.182 ;
     RECT  48.412 149.298 48.604 168.222 ;
     RECT  48.604 105.936 51.008 105.96 ;
     RECT  48.604 110.496 51.008 110.52 ;
     RECT  48.604 166.992 51.008 167.016 ;
     RECT  51.008 2.148 51.112 41.052 ;
     RECT  51.008 62.628 51.112 84.252 ;
     RECT  51.008 105.828 51.112 127.452 ;
     RECT  51.008 149.028 51.112 168.492 ;
     RECT  51.112 2.418 51.304 40.782 ;
     RECT  51.112 62.898 51.304 83.982 ;
     RECT  51.112 105.936 51.304 127.182 ;
     RECT  51.112 149.298 51.304 168.222 ;
     RECT  51.304 105.936 53.708 105.96 ;
     RECT  51.304 110.496 53.708 110.52 ;
     RECT  51.304 166.992 53.708 167.016 ;
     RECT  53.708 2.148 53.812 41.052 ;
     RECT  53.708 62.628 53.812 84.252 ;
     RECT  53.708 105.828 53.812 127.452 ;
     RECT  53.708 149.028 53.812 168.492 ;
     RECT  53.812 2.418 54.004 40.782 ;
     RECT  53.812 62.898 54.004 83.982 ;
     RECT  53.812 105.936 54.004 127.182 ;
     RECT  53.812 149.298 54.004 168.222 ;
     RECT  54.004 105.936 56.408 105.96 ;
     RECT  54.004 110.496 56.408 110.52 ;
     RECT  54.004 166.992 56.408 167.016 ;
     RECT  56.408 2.148 56.512 41.052 ;
     RECT  56.408 62.628 56.512 84.252 ;
     RECT  56.408 105.828 56.512 127.452 ;
     RECT  56.408 149.028 56.512 168.492 ;
     RECT  56.512 2.418 56.704 40.782 ;
     RECT  56.512 62.898 56.704 83.982 ;
     RECT  56.512 105.936 56.704 127.182 ;
     RECT  56.512 149.298 56.704 168.222 ;
     RECT  56.704 105.936 59.108 105.96 ;
     RECT  56.704 110.496 59.108 110.52 ;
     RECT  56.704 166.992 59.108 167.016 ;
     RECT  59.108 2.148 59.212 41.052 ;
     RECT  59.108 62.628 59.212 84.252 ;
     RECT  59.108 105.828 59.212 127.452 ;
     RECT  59.108 149.028 59.212 168.492 ;
     RECT  59.212 2.418 59.404 40.782 ;
     RECT  59.212 62.898 59.404 83.982 ;
     RECT  59.212 105.936 59.404 127.182 ;
     RECT  59.212 149.298 59.404 168.222 ;
     RECT  59.404 105.936 61.808 105.96 ;
     RECT  59.404 110.496 61.808 110.52 ;
     RECT  59.404 166.992 61.808 167.016 ;
     RECT  61.808 2.148 61.912 41.052 ;
     RECT  61.808 62.628 61.912 84.252 ;
     RECT  61.808 105.828 61.912 127.452 ;
     RECT  61.808 149.028 61.912 168.492 ;
     RECT  61.912 2.418 62.104 40.782 ;
     RECT  61.912 62.898 62.104 83.982 ;
     RECT  61.912 105.936 62.104 127.182 ;
     RECT  61.912 149.298 62.104 168.222 ;
     RECT  62.104 105.936 64.508 105.96 ;
     RECT  62.104 110.496 64.508 110.52 ;
     RECT  62.104 166.992 64.508 167.016 ;
     RECT  64.508 2.148 64.612 41.052 ;
     RECT  64.508 62.628 64.612 84.252 ;
     RECT  64.508 105.828 64.612 127.452 ;
     RECT  64.508 149.028 64.612 168.492 ;
     RECT  64.612 62.898 64.717 84.252 ;
     RECT  64.612 2.418 64.804 40.782 ;
     RECT  64.717 62.898 64.804 84.36 ;
     RECT  64.612 105.828 64.804 127.182 ;
     RECT  64.612 149.298 64.804 168.222 ;
     RECT  64.804 105.828 64.901 105.96 ;
     RECT  64.804 84.336 65.267 84.36 ;
     RECT  65.221 105.456 65.305 105.48 ;
     RECT  66.277 73.824 67.208 73.848 ;
     RECT  66.236 84.096 67.208 84.12 ;
     RECT  64.804 110.016 67.208 110.52 ;
     RECT  66.277 127.248 67.208 127.272 ;
     RECT  64.804 166.992 67.208 167.016 ;
     RECT  67.208 2.148 67.312 41.052 ;
     RECT  67.208 62.628 67.312 84.252 ;
     RECT  67.208 105.828 67.312 127.452 ;
     RECT  67.208 149.028 67.312 168.492 ;
     RECT  67.312 2.418 67.504 40.782 ;
     RECT  67.312 62.898 67.504 83.982 ;
     RECT  67.312 106.098 67.504 127.272 ;
     RECT  67.312 149.298 67.504 168.222 ;
     RECT  67.504 73.824 69.908 73.848 ;
     RECT  67.504 127.248 69.908 127.272 ;
     RECT  67.504 166.992 69.908 167.016 ;
     RECT  69.908 2.148 70.012 41.052 ;
     RECT  69.908 62.628 70.012 84.252 ;
     RECT  69.908 105.828 70.012 127.452 ;
     RECT  69.908 149.028 70.012 168.492 ;
     RECT  70.012 2.418 70.204 40.782 ;
     RECT  70.012 62.898 70.204 83.982 ;
     RECT  70.012 106.098 70.204 127.272 ;
     RECT  70.012 149.298 70.204 168.222 ;
     RECT  70.204 127.248 71.665 127.272 ;
     RECT  70.204 73.824 72.608 73.848 ;
     RECT  71.665 127.056 72.608 127.272 ;
     RECT  70.204 166.992 72.608 167.016 ;
     RECT  72.608 2.148 72.712 41.052 ;
     RECT  72.608 62.628 72.712 84.252 ;
     RECT  72.608 105.828 72.712 127.452 ;
     RECT  72.608 149.028 72.712 168.492 ;
     RECT  72.712 2.418 72.904 40.782 ;
     RECT  72.712 62.898 72.904 83.982 ;
     RECT  72.712 106.098 72.904 127.272 ;
     RECT  72.712 149.298 72.904 168.222 ;
     RECT  72.904 127.056 73.789 127.272 ;
     RECT  73.789 127.056 73.829 127.32 ;
     RECT  72.904 126 74.053 126.024 ;
     RECT  74.053 125.376 74.099 126.024 ;
     RECT  74.099 125.376 74.153 125.4 ;
     RECT  43.272 43.2 75.013 61.656 ;
     RECT  75.013 42.768 75.12 61.656 ;
     RECT  43.331 86.4 75.12 104.328 ;
     RECT  43.331 129.6 75.12 147.672 ;
     RECT  75.157 84.384 75.229 84.408 ;
     RECT  75.229 83.808 75.269 84.408 ;
     RECT  75.12 43.968 75.305 53.88 ;
     RECT  75.12 87.168 75.305 96.984 ;
     RECT  75.157 41.136 75.308 41.16 ;
     RECT  72.904 73.824 75.308 73.848 ;
     RECT  75.269 83.808 75.308 84.252 ;
     RECT  73.829 127.248 75.308 127.32 ;
     RECT  72.904 166.992 75.308 167.016 ;
     RECT  75.305 87.168 75.341 96.888 ;
     RECT  75.12 130.368 75.341 140.184 ;
     RECT  75.341 130.368 75.377 140.088 ;
     RECT  75.308 2.148 75.412 41.16 ;
     RECT  75.308 62.628 75.412 84.252 ;
     RECT  75.308 105.828 75.412 127.452 ;
     RECT  75.308 149.028 75.412 168.492 ;
     RECT  75.305 44.064 75.449 53.88 ;
     RECT  75.341 87.264 75.485 96.888 ;
     RECT  75.12 104.304 75.521 104.328 ;
     RECT  75.12 147.072 75.521 147.672 ;
     RECT  75.412 2.418 75.604 41.16 ;
     RECT  75.412 62.898 75.604 84.072 ;
     RECT  75.412 106.098 75.604 127.32 ;
     RECT  75.412 149.298 75.604 168.222 ;
     RECT  75.604 41.136 75.731 41.16 ;
     RECT  75.604 83.808 75.731 84.072 ;
     RECT  75.604 126 75.731 126.024 ;
     RECT  75.12 42.768 75.779 42.888 ;
     RECT  75.779 42.864 75.827 42.888 ;
     RECT  75.377 130.368 76.169 139.992 ;
     RECT  75.485 87.264 76.673 96.792 ;
     RECT  75.604 73.824 76.849 73.848 ;
     RECT  75.449 44.064 76.961 53.496 ;
     RECT  76.673 87.264 76.961 96.216 ;
     RECT  76.849 73.824 77.132 74.28 ;
     RECT  77.132 73.728 77.173 74.28 ;
     RECT  76.961 44.064 78.008 47.64 ;
     RECT  76.961 48.864 78.008 53.496 ;
     RECT  75.12 60.576 78.008 61.656 ;
     RECT  77.173 73.728 78.008 74.376 ;
     RECT  75.731 84.048 78.008 84.072 ;
     RECT  76.961 87.264 78.008 90.84 ;
     RECT  76.961 92.064 78.008 96.216 ;
     RECT  75.604 127.248 78.008 127.32 ;
     RECT  76.169 130.368 78.008 139.896 ;
     RECT  75.521 147.072 78.008 147.24 ;
     RECT  75.604 166.992 78.008 167.016 ;
     RECT  78.008 2.148 78.112 168.492 ;
     RECT  78.112 2.418 78.304 168.222 ;
     RECT  78.304 44.064 80.708 47.64 ;
     RECT  78.304 60.576 80.708 61.656 ;
     RECT  78.304 74.352 80.708 74.376 ;
     RECT  78.304 84.048 80.708 84.072 ;
     RECT  78.304 87.264 80.708 90.888 ;
     RECT  78.304 127.248 80.708 127.272 ;
     RECT  78.304 130.368 80.708 133.272 ;
     RECT  78.304 147.072 80.708 147.24 ;
     RECT  80.708 2.148 80.812 168.492 ;
     RECT  80.812 2.418 81.004 168.222 ;
     RECT  81.004 85.392 81.875 85.944 ;
     RECT  81.004 44.064 83.408 47.64 ;
     RECT  81.004 60.576 83.408 61.656 ;
     RECT  81.004 74.352 83.408 74.376 ;
     RECT  81.004 84.048 83.408 84.072 ;
     RECT  81.875 85.776 83.408 85.944 ;
     RECT  81.004 87.264 83.408 90.888 ;
     RECT  81.004 127.248 83.408 127.272 ;
     RECT  81.004 130.464 83.408 133.272 ;
     RECT  81.004 147.072 83.408 147.24 ;
     RECT  83.408 2.148 83.512 168.492 ;
     RECT  83.512 2.418 83.704 168.222 ;
     RECT  83.704 130.464 84.413 133.272 ;
     RECT  83.704 84.048 84.949 84.072 ;
     RECT  84.949 84.048 85.133 84.36 ;
     RECT  83.704 44.064 86.108 47.448 ;
     RECT  83.704 60.576 86.108 61.656 ;
     RECT  83.704 74.352 86.108 74.376 ;
     RECT  85.133 84.336 86.108 84.36 ;
     RECT  83.704 85.776 86.108 85.944 ;
     RECT  83.704 87.264 86.108 90.888 ;
     RECT  83.704 127.248 86.108 127.272 ;
     RECT  84.413 130.56 86.108 133.272 ;
     RECT  83.704 147.072 86.108 147.24 ;
     RECT  86.108 2.148 86.212 168.492 ;
     RECT  86.212 2.418 86.404 168.222 ;
     RECT  86.404 130.56 86.681 132.792 ;
     RECT  86.404 44.064 87.797 47.448 ;
     RECT  86.404 85.776 88.261 85.944 ;
     RECT  86.404 84.336 88.729 84.36 ;
     RECT  88.261 85.776 88.729 85.992 ;
     RECT  87.797 44.064 88.808 46.392 ;
     RECT  87.797 47.376 88.808 47.448 ;
     RECT  86.404 60.576 88.808 61.656 ;
     RECT  86.404 74.352 88.808 74.376 ;
     RECT  88.729 84.336 88.808 85.992 ;
     RECT  86.404 87.264 88.808 90.648 ;
     RECT  86.404 127.248 88.808 127.272 ;
     RECT  86.681 130.56 88.808 132.696 ;
     RECT  88.765 139.68 88.808 139.704 ;
     RECT  86.404 147.072 88.808 147.24 ;
     RECT  88.808 2.148 88.912 168.492 ;
     RECT  88.912 2.418 89.104 168.222 ;
     RECT  89.104 39.504 89.273 40.44 ;
     RECT  89.104 84.336 89.507 86.184 ;
     RECT  89.507 84.336 89.525 86.088 ;
     RECT  89.104 130.56 89.525 132.696 ;
     RECT  89.104 56.4 89.747 57.048 ;
     RECT  89.104 87.264 89.777 90.648 ;
     RECT  89.747 56.4 89.788 56.904 ;
     RECT  89.104 47.376 89.993 47.448 ;
     RECT  89.993 47.424 90.065 47.448 ;
     RECT  89.104 142.032 90.085 142.92 ;
     RECT  90.085 136.608 90.092 136.632 ;
     RECT  89.104 41.616 90.097 41.64 ;
     RECT  90.085 141.264 90.133 142.92 ;
     RECT  89.273 40.416 90.137 40.44 ;
     RECT  90.097 41.616 90.137 42.168 ;
     RECT  89.525 84.336 90.169 84.36 ;
     RECT  90.133 140.736 90.172 143.064 ;
     RECT  90.092 136.176 90.173 136.632 ;
     RECT  90.173 136.176 90.179 136.2 ;
     RECT  89.104 139.68 90.277 139.704 ;
     RECT  90.172 140.736 90.277 140.76 ;
     RECT  89.525 130.848 90.353 132.696 ;
     RECT  90.172 142.032 90.389 143.064 ;
     RECT  89.104 127.248 90.421 127.272 ;
     RECT  89.104 128.304 90.504 128.328 ;
     RECT  90.421 126.816 90.565 127.272 ;
     RECT  90.504 128.304 90.565 128.472 ;
     RECT  89.525 85.44 90.637 86.088 ;
     RECT  90.205 99.168 90.781 99.192 ;
     RECT  90.781 99.168 90.961 99.576 ;
     RECT  90.169 83.76 91.033 84.36 ;
     RECT  90.277 139.68 91.069 140.76 ;
     RECT  89.777 87.552 91.141 90.648 ;
     RECT  90.137 42.144 91.177 42.168 ;
     RECT  91.177 42.144 91.189 42.792 ;
     RECT  90.313 52.848 91.321 52.872 ;
     RECT  89.788 56.88 91.333 56.904 ;
     RECT  91.189 41.808 91.381 42.792 ;
     RECT  89.104 44.064 91.381 46.296 ;
     RECT  91.333 55.776 91.381 56.904 ;
     RECT  91.381 41.808 91.393 46.296 ;
     RECT  90.097 81.744 91.393 81.768 ;
     RECT  90.389 142.896 91.393 143.064 ;
     RECT  91.069 139.392 91.501 140.76 ;
     RECT  91.393 40.848 91.508 46.296 ;
     RECT  91.321 52.848 91.508 53.592 ;
     RECT  91.381 54.96 91.508 56.904 ;
     RECT  89.104 60.576 91.508 61.656 ;
     RECT  89.104 74.352 91.508 74.376 ;
     RECT  91.393 81.648 91.508 81.768 ;
     RECT  91.033 83.184 91.508 84.36 ;
     RECT  90.637 85.44 91.508 86.232 ;
     RECT  91.141 87.552 91.508 90.84 ;
     RECT  91.465 97.92 91.508 97.944 ;
     RECT  90.961 99.168 91.508 100.344 ;
     RECT  90.565 126.816 91.508 128.472 ;
     RECT  90.353 130.848 91.508 130.872 ;
     RECT  90.353 131.904 91.508 132.696 ;
     RECT  90.457 135.648 91.508 135.672 ;
     RECT  91.501 139.392 91.508 141.384 ;
     RECT  91.393 142.896 91.508 143.736 ;
     RECT  89.104 147.072 91.508 147.24 ;
     RECT  91.508 2.148 91.612 168.492 ;
     RECT  91.612 2.418 91.804 168.222 ;
     RECT  91.804 55.008 91.865 56.52 ;
     RECT  91.804 97.92 91.865 97.944 ;
     RECT  91.804 42.192 91.937 43.32 ;
     RECT  91.804 44.352 91.937 44.76 ;
     RECT  91.804 99.552 91.955 100.344 ;
     RECT  91.804 87.648 92.045 87.96 ;
     RECT  92.045 87.648 92.081 87.672 ;
     RECT  91.804 131.904 92.297 131.928 ;
     RECT  91.804 74.352 92.339 74.376 ;
     RECT  91.804 82.8 92.339 82.824 ;
     RECT  91.804 130.848 92.405 130.872 ;
     RECT  91.804 53.568 92.441 53.592 ;
     RECT  91.865 56.496 92.513 56.52 ;
     RECT  91.804 126.96 92.549 126.984 ;
     RECT  91.804 90.24 92.621 90.984 ;
     RECT  91.804 81.648 92.657 81.672 ;
     RECT  91.804 40.848 92.693 40.872 ;
     RECT  91.937 42.192 92.693 42.216 ;
     RECT  91.804 125.376 92.693 125.976 ;
     RECT  91.804 138.768 92.771 141.384 ;
     RECT  91.865 55.008 92.797 55.032 ;
     RECT  91.955 99.552 92.869 99.576 ;
     RECT  92.771 138.96 92.869 141.384 ;
     RECT  91.804 142.896 92.869 143.736 ;
     RECT  92.797 54.096 92.945 55.032 ;
     RECT  92.693 125.952 93.085 125.976 ;
     RECT  92.941 40.608 93.089 40.632 ;
     RECT  91.937 43.296 93.193 43.32 ;
     RECT  92.621 90.96 93.203 90.984 ;
     RECT  93.193 43.008 93.212 43.32 ;
     RECT  91.937 44.736 93.212 44.76 ;
     RECT  91.804 96.336 93.229 96.36 ;
     RECT  93.085 125.952 93.661 126.024 ;
     RECT  93.229 96.336 93.697 97.08 ;
     RECT  91.804 128.304 93.805 129 ;
     RECT  92.977 82.656 93.913 82.68 ;
     RECT  93.193 98.064 93.913 98.088 ;
     RECT  92.869 99.504 93.913 99.576 ;
     RECT  93.049 39.312 93.925 39.336 ;
     RECT  93.733 40.416 93.925 40.44 ;
     RECT  93.253 52.704 93.925 53.016 ;
     RECT  92.945 54.144 93.925 55.032 ;
     RECT  93.661 125.952 93.985 126.456 ;
     RECT  93.985 125.424 94.021 126.456 ;
     RECT  93.925 52.704 94.057 55.032 ;
     RECT  93.805 128.064 94.165 129 ;
     RECT  93.913 82.656 94.201 82.776 ;
     RECT  93.925 39.312 94.208 40.44 ;
     RECT  93.049 41.616 94.208 41.64 ;
     RECT  93.212 43.008 94.208 44.76 ;
     RECT  94.057 52.704 94.208 55.176 ;
     RECT  91.804 60.576 94.208 61.656 ;
     RECT  94.201 82.656 94.208 82.968 ;
     RECT  91.804 84.336 94.208 84.36 ;
     RECT  91.804 85.488 94.208 86.232 ;
     RECT  93.697 96.24 94.208 97.08 ;
     RECT  93.913 98.064 94.208 99.576 ;
     RECT  94.021 124.8 94.208 126.456 ;
     RECT  94.165 127.584 94.208 129 ;
     RECT  92.869 138.96 94.208 143.736 ;
     RECT  91.804 147.072 94.208 147.24 ;
     RECT  94.208 2.148 94.312 168.492 ;
     RECT  94.312 2.418 94.504 168.222 ;
     RECT  94.504 85.392 94.709 85.992 ;
     RECT  94.504 38.88 94.889 43.032 ;
     RECT  94.504 96.24 94.925 100.536 ;
     RECT  94.504 138.96 94.997 143.736 ;
     RECT  94.889 38.88 95.033 42.648 ;
     RECT  94.504 124.704 95.075 126.456 ;
     RECT  94.997 138.96 95.171 143.688 ;
     RECT  94.504 60.576 95.285 61.08 ;
     RECT  94.504 147.216 95.285 147.24 ;
     RECT  95.075 124.8 95.357 126.456 ;
     RECT  94.504 127.584 95.393 129 ;
     RECT  95.171 138.96 95.501 143.496 ;
     RECT  94.504 54.144 95.677 55.176 ;
     RECT  95.677 54.144 95.749 55.464 ;
     RECT  94.504 82.656 95.749 83.256 ;
     RECT  94.504 84.24 95.749 84.264 ;
     RECT  95.357 125.136 95.749 126.456 ;
     RECT  95.393 127.584 95.749 128.856 ;
     RECT  95.749 54 95.785 55.464 ;
     RECT  95.749 56.88 95.785 56.904 ;
     RECT  95.033 41.04 95.893 42.648 ;
     RECT  94.504 52.704 95.893 53.016 ;
     RECT  95.785 54 95.893 56.904 ;
     RECT  95.749 82.656 95.893 84.264 ;
     RECT  94.709 85.392 95.893 85.416 ;
     RECT  94.925 97.056 95.893 100.536 ;
     RECT  95.285 61.056 95.897 61.08 ;
     RECT  95.749 125.136 96.275 128.856 ;
     RECT  95.033 38.88 96.289 40.056 ;
     RECT  95.893 41.04 96.289 43.224 ;
     RECT  95.893 81.792 96.289 85.416 ;
     RECT  95.893 52.704 96.325 56.904 ;
     RECT  95.893 96.336 96.325 100.536 ;
     RECT  96.289 81.36 96.901 85.704 ;
     RECT  96.325 52.56 96.937 56.904 ;
     RECT  96.289 38.736 98.196 38.76 ;
     RECT  96.289 38.76 98.22 38.88 ;
     RECT  96.289 38.88 98.196 38.904 ;
     RECT  96.289 38.904 98.22 39.024 ;
     RECT  96.289 39.024 98.196 39.048 ;
     RECT  96.289 39.048 98.22 39.168 ;
     RECT  96.289 39.168 98.196 39.192 ;
     RECT  96.289 39.192 98.22 39.312 ;
     RECT  96.289 39.312 98.196 39.336 ;
     RECT  96.289 39.336 98.22 39.456 ;
     RECT  96.289 39.456 98.196 39.48 ;
     RECT  96.289 39.48 98.22 39.6 ;
     RECT  96.289 39.6 98.196 39.624 ;
     RECT  96.289 39.624 98.22 39.744 ;
     RECT  96.289 39.744 98.196 39.768 ;
     RECT  96.289 39.768 98.22 39.888 ;
     RECT  96.289 39.888 98.196 39.912 ;
     RECT  96.289 39.912 98.22 40.032 ;
     RECT  96.289 40.032 98.196 40.056 ;
     RECT  96.289 40.056 98.22 40.176 ;
     RECT  96.289 40.176 98.196 40.2 ;
     RECT  96.289 40.2 98.22 40.32 ;
     RECT  96.289 40.32 98.196 40.344 ;
     RECT  96.289 40.344 98.22 40.464 ;
     RECT  96.289 40.464 98.196 40.488 ;
     RECT  96.289 40.488 98.22 40.608 ;
     RECT  96.289 40.608 98.196 40.632 ;
     RECT  96.289 40.632 98.22 40.752 ;
     RECT  96.289 40.752 98.196 40.776 ;
     RECT  96.289 40.776 98.22 40.896 ;
     RECT  96.289 40.896 98.196 40.92 ;
     RECT  96.289 40.92 98.22 41.04 ;
     RECT  96.289 41.04 98.196 41.064 ;
     RECT  96.289 41.064 98.22 41.184 ;
     RECT  96.289 41.184 98.196 41.208 ;
     RECT  96.289 41.208 98.22 41.328 ;
     RECT  96.289 41.328 98.196 41.352 ;
     RECT  96.289 41.352 98.22 41.472 ;
     RECT  96.289 41.472 98.196 41.496 ;
     RECT  96.289 41.496 98.22 41.616 ;
     RECT  96.289 41.616 98.196 41.64 ;
     RECT  96.289 41.64 98.22 41.76 ;
     RECT  96.289 41.76 98.196 41.784 ;
     RECT  96.289 41.784 98.22 41.904 ;
     RECT  96.289 41.904 98.196 41.928 ;
     RECT  96.289 41.928 98.22 42.048 ;
     RECT  96.289 42.048 98.196 42.072 ;
     RECT  96.289 42.072 98.22 42.192 ;
     RECT  96.289 42.192 98.196 42.216 ;
     RECT  96.289 42.216 98.22 42.336 ;
     RECT  96.289 42.336 98.196 42.36 ;
     RECT  96.289 42.36 98.22 42.48 ;
     RECT  96.289 42.48 98.196 42.504 ;
     RECT  96.289 42.504 98.22 42.624 ;
     RECT  96.289 42.624 98.196 42.648 ;
     RECT  96.289 42.648 98.22 42.768 ;
     RECT  96.289 42.768 98.196 42.792 ;
     RECT  96.289 42.792 98.22 42.912 ;
     RECT  96.289 42.912 98.196 42.936 ;
     RECT  96.289 42.936 98.22 43.056 ;
     RECT  96.289 43.056 98.196 43.08 ;
     RECT  96.289 43.08 98.22 43.2 ;
     RECT  96.289 43.2 98.196 43.224 ;
     RECT  96.937 52.56 98.196 52.584 ;
     RECT  96.937 52.584 98.22 52.704 ;
     RECT  96.937 52.704 98.196 52.728 ;
     RECT  96.937 52.728 98.22 52.848 ;
     RECT  96.937 52.848 98.196 52.872 ;
     RECT  96.937 52.872 98.22 52.992 ;
     RECT  96.937 52.992 98.196 53.016 ;
     RECT  96.937 53.016 98.22 53.136 ;
     RECT  96.937 53.136 98.196 53.16 ;
     RECT  96.937 53.16 98.22 53.28 ;
     RECT  96.937 53.28 98.196 53.304 ;
     RECT  96.937 53.304 98.22 53.424 ;
     RECT  96.937 53.424 98.196 53.448 ;
     RECT  96.937 53.448 98.22 53.568 ;
     RECT  96.937 53.568 98.196 53.592 ;
     RECT  96.937 53.592 98.22 53.712 ;
     RECT  96.937 53.712 98.196 53.736 ;
     RECT  96.937 53.736 98.22 53.856 ;
     RECT  96.937 53.856 98.196 53.88 ;
     RECT  96.937 53.88 98.22 54 ;
     RECT  96.937 54 98.196 54.024 ;
     RECT  96.937 54.024 98.22 54.144 ;
     RECT  96.937 54.144 98.196 54.168 ;
     RECT  96.937 54.168 98.22 54.288 ;
     RECT  96.937 54.288 98.196 54.312 ;
     RECT  96.937 54.312 98.22 54.432 ;
     RECT  96.937 54.432 98.196 54.456 ;
     RECT  96.937 54.456 98.22 54.576 ;
     RECT  96.937 54.576 98.196 54.6 ;
     RECT  96.937 54.6 98.22 54.72 ;
     RECT  96.937 54.72 98.196 54.744 ;
     RECT  96.937 54.744 98.22 54.864 ;
     RECT  96.937 54.864 98.196 54.888 ;
     RECT  96.937 54.888 98.22 55.008 ;
     RECT  96.937 55.008 98.196 55.032 ;
     RECT  96.937 55.032 98.22 55.152 ;
     RECT  96.937 55.152 98.196 55.176 ;
     RECT  96.937 55.176 98.22 55.296 ;
     RECT  96.937 55.296 98.196 55.32 ;
     RECT  96.937 55.32 98.22 55.44 ;
     RECT  96.937 55.44 98.196 55.464 ;
     RECT  96.937 55.464 98.22 55.584 ;
     RECT  96.937 55.584 98.196 55.608 ;
     RECT  96.937 55.608 98.22 55.728 ;
     RECT  96.937 55.728 98.196 55.752 ;
     RECT  96.937 55.752 98.22 55.872 ;
     RECT  96.937 55.872 98.196 55.896 ;
     RECT  96.937 55.896 98.22 56.016 ;
     RECT  96.937 56.016 98.196 56.04 ;
     RECT  96.937 56.04 98.22 56.16 ;
     RECT  96.937 56.16 98.196 56.184 ;
     RECT  96.937 56.184 98.22 56.304 ;
     RECT  96.937 56.304 98.196 56.328 ;
     RECT  96.937 56.328 98.22 56.448 ;
     RECT  96.937 56.448 98.196 56.472 ;
     RECT  96.937 56.472 98.22 56.592 ;
     RECT  96.937 56.592 98.196 56.616 ;
     RECT  96.937 56.616 98.22 56.736 ;
     RECT  96.937 56.736 98.196 56.76 ;
     RECT  96.937 56.76 98.22 56.88 ;
     RECT  96.937 56.88 98.196 56.904 ;
     RECT  96.937 56.904 98.22 57.024 ;
     RECT  96.937 57.024 98.196 57.048 ;
     RECT  96.901 81.36 98.196 81.384 ;
     RECT  96.901 81.384 98.22 81.504 ;
     RECT  96.901 81.504 98.196 81.528 ;
     RECT  96.901 81.528 98.22 81.648 ;
     RECT  96.901 81.648 98.196 81.672 ;
     RECT  96.901 81.672 98.22 81.792 ;
     RECT  96.901 81.792 98.196 81.816 ;
     RECT  96.901 81.816 98.22 81.936 ;
     RECT  96.901 81.936 98.196 81.96 ;
     RECT  96.901 81.96 98.22 82.08 ;
     RECT  96.901 82.08 98.196 82.104 ;
     RECT  96.901 82.104 98.22 82.224 ;
     RECT  96.901 82.224 98.196 82.248 ;
     RECT  96.901 82.248 98.22 82.368 ;
     RECT  96.901 82.368 98.196 82.392 ;
     RECT  96.901 82.392 98.22 82.512 ;
     RECT  96.901 82.512 98.196 82.536 ;
     RECT  96.901 82.536 98.22 82.656 ;
     RECT  96.901 82.656 98.196 82.68 ;
     RECT  96.901 82.68 98.22 82.8 ;
     RECT  96.901 82.8 98.196 82.824 ;
     RECT  96.901 82.824 98.22 82.944 ;
     RECT  96.901 82.944 98.196 82.968 ;
     RECT  96.901 82.968 98.22 83.088 ;
     RECT  96.901 83.088 98.196 83.112 ;
     RECT  96.901 83.112 98.22 83.232 ;
     RECT  96.901 83.232 98.196 83.256 ;
     RECT  96.901 83.256 98.22 83.376 ;
     RECT  96.901 83.376 98.196 83.4 ;
     RECT  96.901 83.4 98.22 83.52 ;
     RECT  96.901 83.52 98.196 83.544 ;
     RECT  96.901 83.544 98.22 83.664 ;
     RECT  96.901 83.664 98.196 83.688 ;
     RECT  96.901 83.688 98.22 83.808 ;
     RECT  96.901 83.808 98.196 83.832 ;
     RECT  96.901 83.832 98.22 83.952 ;
     RECT  96.901 83.952 98.196 83.976 ;
     RECT  96.901 83.976 98.22 84.096 ;
     RECT  96.901 84.096 98.196 84.12 ;
     RECT  96.901 84.12 98.22 84.24 ;
     RECT  96.901 84.24 98.196 84.264 ;
     RECT  96.901 84.264 98.22 84.384 ;
     RECT  96.901 84.384 98.196 84.408 ;
     RECT  96.901 84.408 98.22 84.528 ;
     RECT  96.901 84.528 98.196 84.552 ;
     RECT  96.901 84.552 98.22 84.672 ;
     RECT  96.901 84.672 98.196 84.696 ;
     RECT  96.901 84.696 98.22 84.816 ;
     RECT  96.901 84.816 98.196 84.84 ;
     RECT  96.901 84.84 98.22 84.96 ;
     RECT  96.901 84.96 98.196 84.984 ;
     RECT  96.901 84.984 98.22 85.104 ;
     RECT  96.901 85.104 98.196 85.128 ;
     RECT  96.901 85.128 98.22 85.248 ;
     RECT  96.901 85.248 98.196 85.272 ;
     RECT  96.901 85.272 98.22 85.392 ;
     RECT  96.901 85.392 98.196 85.416 ;
     RECT  96.901 85.416 98.22 85.536 ;
     RECT  96.901 85.536 98.196 85.56 ;
     RECT  96.901 85.56 98.22 85.68 ;
     RECT  96.901 85.68 98.196 85.704 ;
     RECT  96.901 85.704 98.22 85.824 ;
     RECT  96.901 85.824 98.196 85.848 ;
     RECT  96.325 96.336 98.196 96.36 ;
     RECT  96.325 96.36 98.22 96.48 ;
     RECT  96.325 96.48 98.196 96.504 ;
     RECT  96.325 96.504 98.22 96.624 ;
     RECT  96.325 96.624 98.196 96.648 ;
     RECT  96.325 96.648 98.22 96.768 ;
     RECT  96.325 96.768 98.196 96.792 ;
     RECT  96.325 96.792 98.22 96.912 ;
     RECT  96.325 96.912 98.196 96.936 ;
     RECT  96.325 96.936 98.22 97.056 ;
     RECT  96.325 97.056 98.196 97.08 ;
     RECT  96.325 97.08 98.22 97.2 ;
     RECT  96.325 97.2 98.196 97.224 ;
     RECT  96.325 97.224 98.22 97.344 ;
     RECT  96.325 97.344 98.196 97.368 ;
     RECT  96.325 97.368 98.22 97.488 ;
     RECT  96.325 97.488 98.196 97.512 ;
     RECT  96.325 97.512 98.22 97.632 ;
     RECT  96.325 97.632 98.196 97.656 ;
     RECT  96.325 97.656 98.22 97.776 ;
     RECT  96.325 97.776 98.196 97.8 ;
     RECT  96.325 97.8 98.22 97.92 ;
     RECT  96.325 97.92 98.196 97.944 ;
     RECT  96.325 97.944 98.22 98.064 ;
     RECT  96.325 98.064 98.196 98.088 ;
     RECT  96.325 98.088 98.22 98.208 ;
     RECT  96.325 98.208 98.196 98.232 ;
     RECT  96.325 98.232 98.22 98.352 ;
     RECT  96.325 98.352 98.196 98.376 ;
     RECT  96.325 98.376 98.22 98.496 ;
     RECT  96.325 98.496 98.196 98.52 ;
     RECT  96.325 98.52 98.22 98.64 ;
     RECT  96.325 98.64 98.196 98.664 ;
     RECT  96.325 98.664 98.22 98.784 ;
     RECT  96.325 98.784 98.196 98.808 ;
     RECT  96.325 98.808 98.22 98.928 ;
     RECT  96.325 98.928 98.196 98.952 ;
     RECT  96.325 98.952 98.22 99.072 ;
     RECT  96.325 99.072 98.196 99.096 ;
     RECT  96.325 99.096 98.22 99.216 ;
     RECT  96.325 99.216 98.196 99.24 ;
     RECT  96.325 99.24 98.22 99.36 ;
     RECT  96.325 99.36 98.196 99.384 ;
     RECT  96.325 99.384 98.22 99.504 ;
     RECT  96.325 99.504 98.196 99.528 ;
     RECT  96.325 99.528 98.22 99.648 ;
     RECT  96.325 99.648 98.196 99.672 ;
     RECT  96.325 99.672 98.22 99.792 ;
     RECT  96.325 99.792 98.196 99.816 ;
     RECT  96.325 99.816 98.22 99.936 ;
     RECT  96.325 99.936 98.196 99.96 ;
     RECT  96.325 99.96 98.22 100.08 ;
     RECT  96.325 100.08 98.196 100.104 ;
     RECT  96.325 100.104 98.22 100.224 ;
     RECT  96.325 100.224 98.196 100.248 ;
     RECT  96.325 100.248 98.22 100.368 ;
     RECT  96.325 100.368 98.196 100.392 ;
     RECT  96.325 100.392 98.22 100.512 ;
     RECT  96.325 100.512 98.196 100.536 ;
     RECT  96.325 100.536 98.22 100.656 ;
     RECT  96.325 100.656 98.196 100.68 ;
     RECT  96.325 100.68 98.22 100.8 ;
     RECT  96.325 100.8 98.196 100.824 ;
     RECT  96.275 125.136 98.196 125.16 ;
     RECT  96.275 125.16 98.22 125.28 ;
     RECT  96.275 125.28 98.196 125.304 ;
     RECT  96.275 125.304 98.22 125.424 ;
     RECT  96.275 125.424 98.196 125.448 ;
     RECT  96.275 125.448 98.22 125.568 ;
     RECT  96.275 125.568 98.196 125.592 ;
     RECT  96.275 125.592 98.22 125.712 ;
     RECT  96.275 125.712 98.196 125.736 ;
     RECT  96.275 125.736 98.22 125.856 ;
     RECT  96.275 125.856 98.196 125.88 ;
     RECT  96.275 125.88 98.22 126 ;
     RECT  96.275 126 98.196 126.024 ;
     RECT  96.275 126.024 98.22 126.144 ;
     RECT  96.275 126.144 98.196 126.168 ;
     RECT  96.275 126.168 98.22 126.288 ;
     RECT  96.275 126.288 98.196 126.312 ;
     RECT  96.275 126.312 98.22 126.432 ;
     RECT  96.275 126.432 98.196 126.456 ;
     RECT  96.275 126.456 98.22 126.576 ;
     RECT  96.275 126.576 98.196 126.6 ;
     RECT  96.275 126.6 98.22 126.72 ;
     RECT  96.275 126.72 98.196 126.744 ;
     RECT  96.275 126.744 98.22 126.864 ;
     RECT  96.275 126.864 98.196 126.888 ;
     RECT  96.275 126.888 98.22 127.008 ;
     RECT  96.275 127.008 98.196 127.032 ;
     RECT  96.275 127.032 98.22 127.152 ;
     RECT  96.275 127.152 98.196 127.176 ;
     RECT  96.275 127.176 98.22 127.296 ;
     RECT  96.275 127.296 98.196 127.32 ;
     RECT  96.275 127.32 98.22 127.44 ;
     RECT  96.275 127.44 98.196 127.464 ;
     RECT  96.275 127.464 98.22 127.584 ;
     RECT  96.275 127.584 98.196 127.608 ;
     RECT  96.275 127.608 98.22 127.728 ;
     RECT  96.275 127.728 98.196 127.752 ;
     RECT  96.275 127.752 98.22 127.872 ;
     RECT  96.275 127.872 98.196 127.896 ;
     RECT  96.275 127.896 98.22 128.016 ;
     RECT  96.275 128.016 98.196 128.04 ;
     RECT  96.275 128.04 98.22 128.16 ;
     RECT  96.275 128.16 98.196 128.184 ;
     RECT  96.275 128.184 98.22 128.304 ;
     RECT  96.275 128.304 98.196 128.328 ;
     RECT  95.501 138.96 98.196 138.984 ;
     RECT  95.501 138.984 98.22 139.104 ;
     RECT  95.501 139.104 98.196 139.128 ;
     RECT  95.501 139.128 98.22 139.248 ;
     RECT  95.501 139.248 98.196 139.272 ;
     RECT  95.501 139.272 98.22 139.392 ;
     RECT  95.501 139.392 98.196 139.416 ;
     RECT  95.501 139.416 98.22 139.536 ;
     RECT  95.501 139.536 98.196 139.56 ;
     RECT  95.501 139.56 98.22 139.68 ;
     RECT  95.501 139.68 98.196 139.704 ;
     RECT  95.501 139.704 98.22 139.824 ;
     RECT  95.501 139.824 98.196 139.848 ;
     RECT  95.501 139.848 98.22 139.968 ;
     RECT  95.501 139.968 98.196 139.992 ;
     RECT  95.501 139.992 98.22 140.112 ;
     RECT  95.501 140.112 98.196 140.136 ;
     RECT  95.501 140.136 98.22 140.256 ;
     RECT  95.501 140.256 98.196 140.28 ;
     RECT  95.501 140.28 98.22 140.4 ;
     RECT  95.501 140.4 98.196 140.424 ;
     RECT  95.501 140.424 98.22 140.544 ;
     RECT  95.501 140.544 98.196 140.568 ;
     RECT  95.501 140.568 98.22 140.688 ;
     RECT  95.501 140.688 98.196 140.712 ;
     RECT  95.501 140.712 98.22 140.832 ;
     RECT  95.501 140.832 98.196 140.856 ;
     RECT  95.501 140.856 98.22 140.976 ;
     RECT  95.501 140.976 98.196 141 ;
     RECT  95.501 141 98.22 141.12 ;
     RECT  95.501 141.12 98.196 141.144 ;
     RECT  95.501 141.144 98.22 141.264 ;
     RECT  95.501 141.264 98.196 141.288 ;
     RECT  95.501 141.288 98.22 141.408 ;
     RECT  95.501 141.408 98.196 141.432 ;
     RECT  95.501 141.432 98.22 141.552 ;
     RECT  95.501 141.552 98.196 141.576 ;
     RECT  95.501 141.576 98.22 141.696 ;
     RECT  95.501 141.696 98.196 141.72 ;
     RECT  95.501 141.72 98.22 141.84 ;
     RECT  95.501 141.84 98.196 141.864 ;
     RECT  95.501 141.864 98.22 141.984 ;
     RECT  95.501 141.984 98.196 142.008 ;
     RECT  95.501 142.008 98.22 142.128 ;
     RECT  95.501 142.128 98.196 142.152 ;
     RECT  95.501 142.152 98.22 142.272 ;
     RECT  95.501 142.272 98.196 142.296 ;
     RECT  95.501 142.296 98.22 142.416 ;
     RECT  95.501 142.416 98.196 142.44 ;
     RECT  95.501 142.44 98.22 142.56 ;
     RECT  95.501 142.56 98.196 142.584 ;
     RECT  95.501 142.584 98.22 142.704 ;
     RECT  95.501 142.704 98.196 142.728 ;
     RECT  95.501 142.728 98.22 142.848 ;
     RECT  95.501 142.848 98.196 142.872 ;
     RECT  95.501 142.872 98.22 142.992 ;
     RECT  95.501 142.992 98.196 143.016 ;
     RECT  95.501 143.016 98.22 143.136 ;
     RECT  95.501 143.136 98.196 143.16 ;
     RECT  95.501 143.16 98.22 143.28 ;
     RECT  95.501 143.28 98.196 143.304 ;
     RECT  95.501 143.304 98.22 143.424 ;
     RECT  95.501 143.424 98.196 143.448 ;
     RECT  98.22 98.736 98.273 98.76 ;
    LAYER M5 ;
     RECT  2.4 2.137 2.52 2.151 ;
     RECT  5.1 2.137 5.22 2.151 ;
     RECT  7.8 2.137 7.92 2.151 ;
     RECT  10.5 2.137 10.62 2.151 ;
     RECT  13.2 2.137 13.32 2.151 ;
     RECT  15.9 2.137 16.02 2.151 ;
     RECT  18.6 2.137 18.72 2.151 ;
     RECT  21.3 2.137 21.42 2.151 ;
     RECT  24 2.137 24.12 2.151 ;
     RECT  26.7 2.137 26.82 2.151 ;
     RECT  29.4 2.137 29.52 2.151 ;
     RECT  32.1 2.137 32.22 2.151 ;
     RECT  34.8 2.137 34.92 2.151 ;
     RECT  37.5 2.137 37.62 2.151 ;
     RECT  40.2 2.137 40.32 2.151 ;
     RECT  42.9 2.137 43.02 2.151 ;
     RECT  45.6 2.137 45.72 2.151 ;
     RECT  48.3 2.137 48.42 2.151 ;
     RECT  51 2.137 51.12 2.151 ;
     RECT  53.7 2.137 53.82 2.151 ;
     RECT  56.4 2.137 56.52 2.151 ;
     RECT  59.1 2.137 59.22 2.151 ;
     RECT  61.8 2.137 61.92 2.151 ;
     RECT  64.5 2.137 64.62 2.151 ;
     RECT  67.2 2.137 67.32 2.151 ;
     RECT  69.9 2.137 70.02 2.151 ;
     RECT  72.6 2.137 72.72 2.151 ;
     RECT  75.3 2.137 75.42 2.151 ;
     RECT  78 2.137 78.12 2.151 ;
     RECT  80.7 2.137 80.82 2.151 ;
     RECT  83.4 2.137 83.52 2.151 ;
     RECT  86.1 2.137 86.22 2.151 ;
     RECT  88.8 2.137 88.92 2.151 ;
     RECT  91.5 2.137 91.62 2.151 ;
     RECT  94.2 2.137 94.32 2.151 ;
     RECT  2.4 2.151 2.712 32.437 ;
     RECT  5.1 2.151 5.412 33.013 ;
     RECT  2.4 32.437 3.432 33.731 ;
     RECT  5.1 33.013 6.264 34.115 ;
     RECT  5.1 34.115 5.412 35.077 ;
     RECT  7.8 2.151 8.112 35.557 ;
     RECT  2.4 33.731 2.712 36.085 ;
     RECT  2.304 36.085 2.712 36.275 ;
     RECT  7.8 35.557 8.28 36.997 ;
     RECT  42.9 2.151 43.212 38.197 ;
     RECT  42.528 38.197 43.212 38.675 ;
     RECT  94.2 2.151 94.512 39.637 ;
     RECT  93.936 39.637 94.512 39.829 ;
     RECT  93.936 39.829 95.16 39.877 ;
     RECT  6.432 36.997 8.28 40.451 ;
     RECT  93.936 39.877 95.784 40.451 ;
     RECT  6.816 40.451 8.28 40.883 ;
     RECT  94.2 40.451 95.784 41.075 ;
     RECT  7.392 40.883 8.28 41.123 ;
     RECT  75.3 2.151 75.612 41.125 ;
     RECT  12.192 40.981 12.216 41.557 ;
     RECT  13.2 2.151 13.512 41.557 ;
     RECT  4.512 35.077 5.412 41.651 ;
     RECT  91.5 2.151 91.812 41.797 ;
     RECT  96.288 41.605 96.312 42.227 ;
     RECT  75.3 41.125 75.72 42.757 ;
     RECT  91.2 41.797 91.812 42.803 ;
     RECT  75.3 42.757 75.768 42.853 ;
     RECT  7.8 41.123 8.112 43.285 ;
     RECT  94.2 41.075 94.512 43.765 ;
     RECT  7.104 43.285 8.112 44.483 ;
     RECT  42.624 38.675 43.212 45.347 ;
     RECT  3.84 43.285 3.864 45.587 ;
     RECT  12.192 41.557 13.512 46.547 ;
     RECT  78 2.151 78.312 46.837 ;
     RECT  78 46.837 78.696 47.123 ;
     RECT  40.2 2.151 40.512 47.653 ;
     RECT  75.3 42.853 75.816 47.939 ;
     RECT  75.3 47.939 75.768 48.419 ;
     RECT  40.2 47.653 40.632 48.659 ;
     RECT  40.2 48.659 40.512 49.525 ;
     RECT  40.08 49.525 40.512 50.243 ;
     RECT  37.5 2.151 37.812 50.629 ;
     RECT  37.5 50.629 38.664 51.541 ;
     RECT  93.264 43.765 94.512 52.739 ;
     RECT  93.936 52.739 94.512 53.795 ;
     RECT  40.2 50.243 40.512 54.517 ;
     RECT  40.2 54.517 40.92 55.237 ;
     RECT  37.5 51.541 38.904 55.475 ;
     RECT  91.392 42.803 91.812 55.765 ;
     RECT  88.8 2.151 89.112 56.389 ;
     RECT  91.344 55.765 91.812 56.915 ;
     RECT  88.8 56.389 89.736 57.059 ;
     RECT  40.2 55.237 41.016 60.659 ;
     RECT  78 47.123 78.312 60.661 ;
     RECT  38.88 55.475 38.904 60.707 ;
     RECT  91.392 56.915 91.812 60.707 ;
     RECT  40.2 60.659 40.968 61.667 ;
     RECT  42.672 45.347 43.212 64.405 ;
     RECT  42.624 64.405 43.212 64.547 ;
     RECT  42.672 64.547 43.212 64.933 ;
     RECT  67.2 2.151 67.512 73.813 ;
     RECT  91.5 60.707 91.812 74.341 ;
     RECT  77.184 60.661 78.312 74.387 ;
     RECT  21.3 2.151 21.612 74.869 ;
     RECT  5.1 41.651 5.412 75.781 ;
     RECT  7.8 44.483 8.112 76.885 ;
     RECT  5.1 75.781 5.544 77.557 ;
     RECT  12.192 46.547 12.216 77.603 ;
     RECT  5.1 77.557 6.264 77.893 ;
     RECT  4.512 77.893 6.264 78.707 ;
     RECT  5.1 78.707 6.264 80.099 ;
     RECT  5.1 80.099 5.928 80.149 ;
     RECT  40.2 61.667 40.512 81.157 ;
     RECT  42.672 64.933 43.32 83.557 ;
     RECT  42.576 83.557 43.32 83.749 ;
     RECT  75.3 48.419 75.612 83.797 ;
     RECT  42.336 83.749 43.32 84.181 ;
     RECT  64.5 2.151 64.812 84.325 ;
     RECT  4.848 80.149 5.928 85.139 ;
     RECT  80.7 2.151 81.012 85.381 ;
     RECT  91.5 74.341 92.328 85.429 ;
     RECT  88.8 57.059 89.112 85.477 ;
     RECT  80.7 85.381 81.864 85.811 ;
     RECT  88.8 85.477 89.496 86.195 ;
     RECT  41.76 84.181 43.32 86.291 ;
     RECT  3.792 86.341 3.816 87.011 ;
     RECT  5.1 85.139 5.928 87.251 ;
     RECT  40.2 81.157 40.632 88.309 ;
     RECT  39.984 88.309 40.632 88.403 ;
     RECT  7.8 76.885 8.616 89.459 ;
     RECT  91.152 85.429 92.328 90.659 ;
     RECT  91.152 90.659 91.944 90.851 ;
     RECT  39.984 88.403 40.512 91.235 ;
     RECT  75.3 83.797 75.72 91.523 ;
     RECT  40.032 91.235 40.512 93.445 ;
     RECT  39.792 93.445 40.512 94.981 ;
     RECT  39.36 94.981 40.512 95.125 ;
     RECT  41.76 86.291 43.212 95.125 ;
     RECT  93.168 90.949 93.192 96.371 ;
     RECT  94.2 53.795 94.512 98.053 ;
     RECT  94.032 98.053 94.512 99.059 ;
     RECT  37.5 55.475 37.812 99.973 ;
     RECT  91.5 90.851 91.944 100.355 ;
     RECT  37.5 99.973 38.04 104.293 ;
     RECT  39.36 95.125 43.212 104.339 ;
     RECT  64.5 84.325 65.256 105.491 ;
     RECT  40.032 104.339 40.512 105.925 ;
     RECT  41.76 104.339 43.212 107.941 ;
     RECT  37.5 104.293 38.184 108.757 ;
     RECT  39.456 105.925 40.512 108.757 ;
     RECT  37.5 108.757 40.512 108.949 ;
     RECT  41.76 107.941 43.32 108.949 ;
     RECT  37.5 108.949 43.32 110.675 ;
     RECT  37.5 110.675 40.776 114.517 ;
     RECT  41.76 110.675 43.32 114.517 ;
     RECT  37.5 114.517 43.32 114.611 ;
     RECT  37.5 114.611 41.016 117.539 ;
     RECT  5.1 87.251 5.412 118.597 ;
     RECT  6.624 118.501 6.648 118.931 ;
     RECT  34.8 2.151 35.112 119.077 ;
     RECT  36.144 110.485 36.168 119.077 ;
     RECT  21.3 74.869 22.488 119.171 ;
     RECT  5.1 118.597 5.544 119.507 ;
     RECT  7.8 89.459 8.112 119.653 ;
     RECT  34.8 119.077 36.168 119.747 ;
     RECT  34.8 119.747 35.112 121.141 ;
     RECT  36.144 119.747 36.168 121.141 ;
     RECT  42.624 114.611 43.32 121.429 ;
     RECT  34.8 121.141 36.168 122.243 ;
     RECT  36.144 122.243 36.168 122.341 ;
     RECT  37.5 117.539 38.04 122.341 ;
     RECT  7.8 119.653 8.28 122.485 ;
     RECT  0.144 122.389 0.168 122.531 ;
     RECT  6.912 122.485 8.28 122.821 ;
     RECT  5.1 119.507 5.412 123.061 ;
     RECT  6.912 122.821 8.328 123.061 ;
     RECT  5.1 123.061 8.328 123.349 ;
     RECT  36.144 122.341 38.04 123.443 ;
     RECT  42.384 121.429 43.32 123.685 ;
     RECT  42.336 123.685 43.32 124.069 ;
     RECT  39.024 117.539 41.016 124.213 ;
     RECT  42.144 124.069 43.32 124.213 ;
     RECT  94.2 99.059 94.512 124.693 ;
     RECT  94.2 124.693 95.064 124.789 ;
     RECT  36.144 123.443 36.168 125.365 ;
     RECT  37.5 123.443 38.04 125.365 ;
     RECT  94.032 124.789 95.064 125.459 ;
     RECT  94.2 125.459 95.064 125.747 ;
     RECT  39.024 124.213 43.32 125.891 ;
     RECT  75.3 91.523 75.612 125.989 ;
     RECT  74.064 125.365 74.088 126.035 ;
     RECT  36.144 125.365 38.04 126.419 ;
     RECT  91.5 100.355 91.812 126.805 ;
     RECT  88.8 86.195 89.112 127.237 ;
     RECT  90.576 126.805 91.812 127.237 ;
     RECT  66.288 73.813 67.512 127.283 ;
     RECT  78 74.387 78.312 127.285 ;
     RECT  4.512 123.349 8.328 127.715 ;
     RECT  96.288 127.717 96.312 127.861 ;
     RECT  96.24 127.861 96.312 128.291 ;
     RECT  96.24 128.291 96.264 128.293 ;
     RECT  88.8 127.237 91.812 128.339 ;
     RECT  95.664 128.293 96.264 128.867 ;
     RECT  37.5 126.419 38.04 128.965 ;
     RECT  39.024 125.891 41.016 128.965 ;
     RECT  42.144 125.891 43.32 129.491 ;
     RECT  4.512 127.715 6.312 129.683 ;
     RECT  4.512 129.683 5.412 129.923 ;
     RECT  36.144 126.419 36.168 129.973 ;
     RECT  37.5 128.965 41.016 129.973 ;
     RECT  7.8 127.715 8.328 130.883 ;
     RECT  34.8 122.243 35.112 130.933 ;
     RECT  36.144 129.973 41.016 130.933 ;
     RECT  83.4 2.151 83.712 131.077 ;
     RECT  82.656 131.077 83.712 131.315 ;
     RECT  77.472 127.285 78.312 132.373 ;
     RECT  86.1 2.151 86.412 132.373 ;
     RECT  77.472 132.373 78.696 132.515 ;
     RECT  86.1 132.373 86.664 132.515 ;
     RECT  42.144 129.491 43.212 133.667 ;
     RECT  75.3 125.989 75.72 134.531 ;
     RECT  34.8 130.933 41.016 135.635 ;
     RECT  90.144 128.339 91.812 135.683 ;
     RECT  37.5 135.635 41.016 136.019 ;
     RECT  90.144 135.683 90.168 136.597 ;
     RECT  34.8 135.635 36.072 138.611 ;
     RECT  91.5 135.683 91.812 138.757 ;
     RECT  91.5 138.757 92.76 138.949 ;
     RECT  94.2 125.747 94.512 138.949 ;
     RECT  91.5 138.949 94.512 139.475 ;
     RECT  95.76 138.997 95.784 139.525 ;
     RECT  95.52 139.525 95.784 139.715 ;
     RECT  93.408 139.475 94.512 140.629 ;
     RECT  95.52 139.715 95.544 140.629 ;
     RECT  93.408 140.629 95.544 140.725 ;
     RECT  90.096 136.597 90.168 140.771 ;
     RECT  93.408 140.725 95.784 141.587 ;
     RECT  93.408 141.587 95.112 141.731 ;
     RECT  88.8 128.339 89.112 142.453 ;
     RECT  90.096 140.771 90.12 142.453 ;
     RECT  93.408 141.731 94.512 142.499 ;
     RECT  96.288 141.973 96.312 142.547 ;
     RECT  37.5 136.019 38.04 142.789 ;
     RECT  39.072 136.019 41.016 142.789 ;
     RECT  88.8 142.453 90.168 142.931 ;
     RECT  94.2 142.499 94.512 142.981 ;
     RECT  90.144 142.931 90.168 143.075 ;
     RECT  37.5 142.789 41.016 143.123 ;
     RECT  37.5 143.123 40.872 143.171 ;
     RECT  94.2 142.981 95.16 143.699 ;
     RECT  37.5 143.171 40.776 147.683 ;
     RECT  37.5 147.683 40.512 149.075 ;
     RECT  37.5 149.075 38.232 165.011 ;
     RECT  37.5 165.011 37.992 166.405 ;
     RECT  77.472 132.515 78.312 167.027 ;
     RECT  37.5 166.405 38.232 167.219 ;
     RECT  2.4 36.275 2.712 168.489 ;
     RECT  5.1 129.923 5.412 168.489 ;
     RECT  7.8 130.883 8.112 168.489 ;
     RECT  10.5 2.151 10.812 168.489 ;
     RECT  13.2 46.547 13.512 168.489 ;
     RECT  15.9 2.151 16.212 168.489 ;
     RECT  18.6 2.151 18.912 168.489 ;
     RECT  21.3 119.171 21.612 168.489 ;
     RECT  24 2.151 24.312 168.489 ;
     RECT  26.7 2.151 27.012 168.489 ;
     RECT  29.4 2.151 29.712 168.489 ;
     RECT  32.1 2.151 32.412 168.489 ;
     RECT  34.8 138.611 35.112 168.489 ;
     RECT  39.456 149.075 40.512 168.489 ;
     RECT  42.9 133.667 43.212 168.489 ;
     RECT  45.6 2.151 45.912 168.489 ;
     RECT  48.3 2.151 48.612 168.489 ;
     RECT  51 2.151 51.312 168.489 ;
     RECT  53.7 2.151 54.012 168.489 ;
     RECT  56.4 2.151 56.712 168.489 ;
     RECT  59.1 2.151 59.412 168.489 ;
     RECT  61.8 2.151 62.112 168.489 ;
     RECT  64.5 105.491 64.812 168.489 ;
     RECT  67.2 127.283 67.512 168.489 ;
     RECT  69.9 2.151 70.212 168.489 ;
     RECT  72.6 2.151 72.912 168.489 ;
     RECT  75.3 134.531 75.612 168.489 ;
     RECT  78 167.027 78.312 168.489 ;
     RECT  80.7 85.811 81.012 168.489 ;
     RECT  83.4 131.315 83.712 168.489 ;
     RECT  86.1 132.515 86.412 168.489 ;
     RECT  88.8 142.931 89.112 168.489 ;
     RECT  91.5 139.475 91.812 168.489 ;
     RECT  94.2 143.699 94.512 168.489 ;
     RECT  2.4 168.489 2.52 168.503 ;
     RECT  5.1 168.489 5.22 168.503 ;
     RECT  7.8 168.489 7.92 168.503 ;
     RECT  10.5 168.489 10.62 168.503 ;
     RECT  13.2 168.489 13.32 168.503 ;
     RECT  15.9 168.489 16.02 168.503 ;
     RECT  18.6 168.489 18.72 168.503 ;
     RECT  21.3 168.489 21.42 168.503 ;
     RECT  24 168.489 24.12 168.503 ;
     RECT  26.7 168.489 26.82 168.503 ;
     RECT  29.4 168.489 29.52 168.503 ;
     RECT  32.1 168.489 32.22 168.503 ;
     RECT  34.8 168.489 34.92 168.503 ;
     RECT  37.5 167.219 37.992 168.503 ;
     RECT  39.456 168.489 40.32 168.503 ;
     RECT  42.9 168.489 43.02 168.503 ;
     RECT  45.6 168.489 45.72 168.503 ;
     RECT  48.3 168.489 48.42 168.503 ;
     RECT  51 168.489 51.12 168.503 ;
     RECT  53.7 168.489 53.82 168.503 ;
     RECT  56.4 168.489 56.52 168.503 ;
     RECT  59.1 168.489 59.22 168.503 ;
     RECT  61.8 168.489 61.92 168.503 ;
     RECT  64.5 168.489 64.62 168.503 ;
     RECT  67.2 168.489 67.32 168.503 ;
     RECT  69.9 168.489 70.02 168.503 ;
     RECT  72.6 168.489 72.72 168.503 ;
     RECT  75.3 168.489 75.42 168.503 ;
     RECT  78 168.489 78.12 168.503 ;
     RECT  80.7 168.489 80.82 168.503 ;
     RECT  83.4 168.489 83.52 168.503 ;
     RECT  86.1 168.489 86.22 168.503 ;
     RECT  88.8 168.489 88.92 168.503 ;
     RECT  91.5 168.489 91.62 168.503 ;
     RECT  94.2 168.489 94.32 168.503 ;
     RECT  39.456 168.503 39.48 170.483 ;
     RECT  37.968 168.503 37.992 170.531 ;
     RECT  5.412 36.997 6.432 40.451 ;
     RECT  5.412 40.451 6.816 40.883 ;
     RECT  10.812 40.981 12.192 77.603 ;
     RECT  12.216 40.981 13.2 41.557 ;
     RECT  2.712 43.285 3.84 45.587 ;
     RECT  3.864 43.285 5.1 45.587 ;
     RECT  91.812 43.765 93.264 52.739 ;
     RECT  12.216 46.547 13.2 77.603 ;
     RECT  40.08 50.243 40.2 50.629 ;
     RECT  38.664 50.629 40.2 51.541 ;
     RECT  38.904 51.541 40.2 60.707 ;
     RECT  37.812 55.475 38.88 60.707 ;
     RECT  64.812 73.813 66.288 84.325 ;
     RECT  22.488 74.869 24 119.171 ;
     RECT  4.848 78.707 5.1 80.149 ;
     RECT  40.632 84.181 41.76 88.403 ;
     RECT  65.256 84.325 66.288 105.491 ;
     RECT  4.848 85.139 5.1 86.341 ;
     RECT  2.712 86.341 3.792 87.011 ;
     RECT  3.816 86.341 5.1 87.011 ;
     RECT  40.512 88.403 41.76 95.125 ;
     RECT  91.944 90.659 92.328 90.949 ;
     RECT  91.944 90.949 93.168 96.371 ;
     RECT  93.192 90.949 94.2 96.371 ;
     RECT  38.04 99.973 39.36 104.293 ;
     RECT  38.184 104.293 39.36 104.339 ;
     RECT  40.512 104.339 41.76 108.949 ;
     RECT  64.812 105.491 66.288 127.283 ;
     RECT  38.184 105.925 39.456 108.757 ;
     RECT  35.112 110.485 36.144 119.077 ;
     RECT  36.168 110.485 37.5 122.341 ;
     RECT  40.776 110.675 41.76 114.517 ;
     RECT  38.04 117.539 39.024 128.965 ;
     RECT  5.412 118.501 6.624 118.597 ;
     RECT  6.648 118.501 7.8 118.931 ;
     RECT  5.544 118.597 6.624 118.931 ;
     RECT  35.112 119.747 36.144 121.141 ;
     RECT  41.016 121.429 42.384 123.685 ;
     RECT  35.112 122.243 36.144 130.933 ;
     RECT  5.412 122.485 6.912 123.061 ;
     RECT  36.168 123.443 37.5 125.365 ;
     RECT  41.016 123.685 42.336 124.069 ;
     RECT  41.016 124.069 42.144 124.213 ;
     RECT  72.912 125.365 74.064 126.035 ;
     RECT  74.088 125.365 75.3 126.035 ;
     RECT  41.016 125.891 42.144 133.667 ;
     RECT  36.168 126.419 37.5 129.973 ;
     RECT  89.112 126.805 90.576 127.237 ;
     RECT  6.312 127.715 7.8 129.683 ;
     RECT  94.512 128.293 95.664 128.867 ;
     RECT  89.112 128.339 90.144 136.597 ;
     RECT  36.072 135.635 37.5 138.611 ;
     RECT  90.168 135.683 91.5 140.771 ;
     RECT  38.04 136.019 39.072 142.789 ;
     RECT  89.112 136.597 90.096 142.453 ;
     RECT  92.76 138.757 94.2 138.949 ;
     RECT  94.512 138.997 95.76 139.525 ;
     RECT  94.512 139.525 95.52 140.629 ;
     RECT  95.544 139.715 95.784 140.725 ;
     RECT  90.12 140.771 91.5 142.453 ;
     RECT  95.112 141.587 95.784 141.731 ;
     RECT  94.512 141.731 95.784 141.973 ;
     RECT  94.512 141.973 96.288 142.547 ;
     RECT  90.168 142.453 91.5 143.075 ;
     RECT  94.512 142.547 95.16 142.981 ;
     RECT  89.112 142.931 90.144 143.075 ;
     RECT  38.232 149.075 39.456 165.011 ;
     RECT  37.992 165.011 39.456 166.405 ;
     RECT  38.232 166.405 39.456 167.219 ;
     RECT  37.992 167.219 39.456 170.483 ;
  END
END qfd_landh0d8sn_183_EW_98x171
END LIBRARY
